VERSION 5.8 ;
BUSBITCHARS "[]" ;
DIVIDERCHAR "/" ;
UNITS
    DATABASE MICRONS 1000 ;
END UNITS

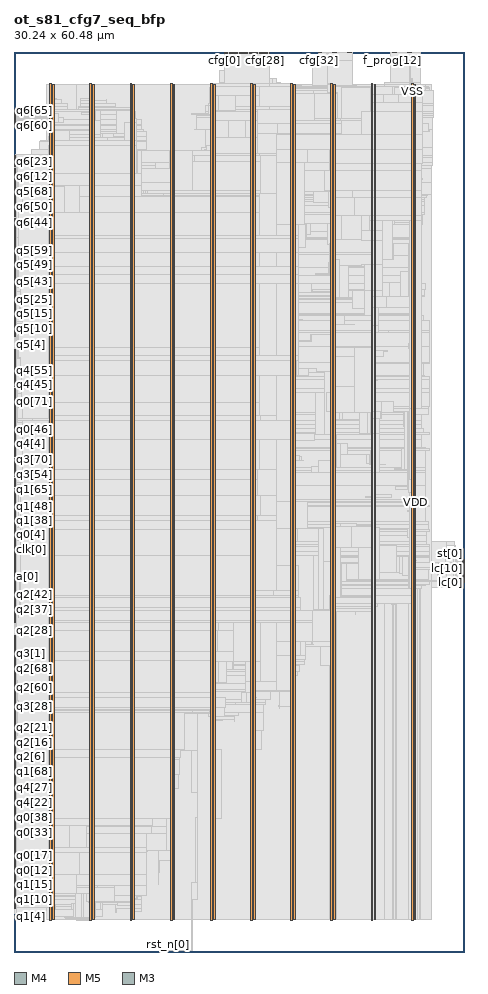
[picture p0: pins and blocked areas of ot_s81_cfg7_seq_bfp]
MACRO ot_s81_cfg7_seq_bfp
  FOREIGN ot_s81_cfg7_seq_bfp 0 0 ;
  CLASS BLOCK ;
  SIZE 30.24 BY 60.48 ;
  PIN a[0]
    DIRECTION OUTPUT ;
    USE SIGNAL ;
    PORT
      LAYER M4 ;
        RECT  0 25.2 0.084 25.224 ;
    END
  END a[0]
  PIN a[10]
    DIRECTION OUTPUT ;
    USE SIGNAL ;
    PORT
      LAYER M4 ;
        RECT  0 26.16 0.084 26.184 ;
    END
  END a[10]
  PIN a[11]
    DIRECTION OUTPUT ;
    USE SIGNAL ;
    PORT
      LAYER M4 ;
        RECT  0 26.256 0.084 26.28 ;
    END
  END a[11]
  PIN a[1]
    DIRECTION OUTPUT ;
    USE SIGNAL ;
    PORT
      LAYER M4 ;
        RECT  0 25.296 0.084 25.32 ;
    END
  END a[1]
  PIN a[2]
    DIRECTION OUTPUT ;
    USE SIGNAL ;
    PORT
      LAYER M4 ;
        RECT  0 25.392 0.084 25.416 ;
    END
  END a[2]
  PIN a[3]
    DIRECTION OUTPUT ;
    USE SIGNAL ;
    PORT
      LAYER M4 ;
        RECT  0 25.488 0.084 25.512 ;
    END
  END a[3]
  PIN a[4]
    DIRECTION OUTPUT ;
    USE SIGNAL ;
    PORT
      LAYER M4 ;
        RECT  0 25.584 0.084 25.608 ;
    END
  END a[4]
  PIN a[5]
    DIRECTION OUTPUT ;
    USE SIGNAL ;
    PORT
      LAYER M4 ;
        RECT  0 25.68 0.084 25.704 ;
    END
  END a[5]
  PIN a[6]
    DIRECTION OUTPUT ;
    USE SIGNAL ;
    PORT
      LAYER M4 ;
        RECT  0 25.776 0.084 25.8 ;
    END
  END a[6]
  PIN a[7]
    DIRECTION OUTPUT ;
    USE SIGNAL ;
    PORT
      LAYER M4 ;
        RECT  0 25.872 0.084 25.896 ;
    END
  END a[7]
  PIN a[8]
    DIRECTION OUTPUT ;
    USE SIGNAL ;
    PORT
      LAYER M4 ;
        RECT  0 25.968 0.084 25.992 ;
    END
  END a[8]
  PIN a[9]
    DIRECTION OUTPUT ;
    USE SIGNAL ;
    PORT
      LAYER M4 ;
        RECT  0 26.064 0.084 26.088 ;
    END
  END a[9]
  PIN ce0[0]
    DIRECTION OUTPUT ;
    USE SIGNAL ;
    PORT
      LAYER M4 ;
        RECT  0 26.352 0.084 26.376 ;
    END
  END ce0[0]
  PIN ce1[0]
    DIRECTION OUTPUT ;
    USE SIGNAL ;
    PORT
      LAYER M4 ;
        RECT  0 26.448 0.084 26.472 ;
    END
  END ce1[0]
  PIN ce2[0]
    DIRECTION OUTPUT ;
    USE SIGNAL ;
    PORT
      LAYER M4 ;
        RECT  0 26.544 0.084 26.568 ;
    END
  END ce2[0]
  PIN ce3[0]
    DIRECTION OUTPUT ;
    USE SIGNAL ;
    PORT
      LAYER M4 ;
        RECT  0 26.64 0.084 26.664 ;
    END
  END ce3[0]
  PIN ce4[0]
    DIRECTION OUTPUT ;
    USE SIGNAL ;
    PORT
      LAYER M4 ;
        RECT  0 26.736 0.084 26.76 ;
    END
  END ce4[0]
  PIN ce5[0]
    DIRECTION OUTPUT ;
    USE SIGNAL ;
    PORT
      LAYER M4 ;
        RECT  0 26.832 0.084 26.856 ;
    END
  END ce5[0]
  PIN ce6[0]
    DIRECTION OUTPUT ;
    USE SIGNAL ;
    PORT
      LAYER M4 ;
        RECT  0 26.928 0.084 26.952 ;
    END
  END ce6[0]
  PIN cfg[0]
    DIRECTION OUTPUT ;
    USE SIGNAL ;
    PORT
      LAYER M5 ;
        RECT  14.16 60.396 14.184 60.48 ;
    END
  END cfg[0]
  PIN cfg[10]
    DIRECTION OUTPUT ;
    USE SIGNAL ;
    PORT
      LAYER M5 ;
        RECT  15.12 60.396 15.144 60.48 ;
    END
  END cfg[10]
  PIN cfg[11]
    DIRECTION OUTPUT ;
    USE SIGNAL ;
    PORT
      LAYER M5 ;
        RECT  15.216 60.396 15.24 60.48 ;
    END
  END cfg[11]
  PIN cfg[12]
    DIRECTION OUTPUT ;
    USE SIGNAL ;
    PORT
      LAYER M5 ;
        RECT  15.312 60.396 15.336 60.48 ;
    END
  END cfg[12]
  PIN cfg[13]
    DIRECTION OUTPUT ;
    USE SIGNAL ;
    PORT
      LAYER M5 ;
        RECT  15.408 60.396 15.432 60.48 ;
    END
  END cfg[13]
  PIN cfg[14]
    DIRECTION OUTPUT ;
    USE SIGNAL ;
    PORT
      LAYER M5 ;
        RECT  15.504 60.396 15.528 60.48 ;
    END
  END cfg[14]
  PIN cfg[15]
    DIRECTION OUTPUT ;
    USE SIGNAL ;
    PORT
      LAYER M5 ;
        RECT  15.6 60.396 15.624 60.48 ;
    END
  END cfg[15]
  PIN cfg[16]
    DIRECTION OUTPUT ;
    USE SIGNAL ;
    PORT
      LAYER M5 ;
        RECT  15.696 60.396 15.72 60.48 ;
    END
  END cfg[16]
  PIN cfg[17]
    DIRECTION OUTPUT ;
    USE SIGNAL ;
    PORT
      LAYER M5 ;
        RECT  15.792 60.396 15.816 60.48 ;
    END
  END cfg[17]
  PIN cfg[18]
    DIRECTION OUTPUT ;
    USE SIGNAL ;
    PORT
      LAYER M5 ;
        RECT  15.888 60.396 15.912 60.48 ;
    END
  END cfg[18]
  PIN cfg[19]
    DIRECTION OUTPUT ;
    USE SIGNAL ;
    PORT
      LAYER M5 ;
        RECT  15.984 60.396 16.008 60.48 ;
    END
  END cfg[19]
  PIN cfg[1]
    DIRECTION OUTPUT ;
    USE SIGNAL ;
    PORT
      LAYER M5 ;
        RECT  14.256 60.396 14.28 60.48 ;
    END
  END cfg[1]
  PIN cfg[20]
    DIRECTION OUTPUT ;
    USE SIGNAL ;
    PORT
      LAYER M5 ;
        RECT  16.08 60.396 16.104 60.48 ;
    END
  END cfg[20]
  PIN cfg[21]
    DIRECTION OUTPUT ;
    USE SIGNAL ;
    PORT
      LAYER M5 ;
        RECT  16.176 60.396 16.2 60.48 ;
    END
  END cfg[21]
  PIN cfg[22]
    DIRECTION OUTPUT ;
    USE SIGNAL ;
    PORT
      LAYER M5 ;
        RECT  16.272 60.396 16.296 60.48 ;
    END
  END cfg[22]
  PIN cfg[23]
    DIRECTION OUTPUT ;
    USE SIGNAL ;
    PORT
      LAYER M5 ;
        RECT  16.368 60.396 16.392 60.48 ;
    END
  END cfg[23]
  PIN cfg[24]
    DIRECTION OUTPUT ;
    USE SIGNAL ;
    PORT
      LAYER M5 ;
        RECT  16.464 60.396 16.488 60.48 ;
    END
  END cfg[24]
  PIN cfg[25]
    DIRECTION OUTPUT ;
    USE SIGNAL ;
    PORT
      LAYER M5 ;
        RECT  16.56 60.396 16.584 60.48 ;
    END
  END cfg[25]
  PIN cfg[26]
    DIRECTION OUTPUT ;
    USE SIGNAL ;
    PORT
      LAYER M5 ;
        RECT  16.656 60.396 16.68 60.48 ;
    END
  END cfg[26]
  PIN cfg[27]
    DIRECTION OUTPUT ;
    USE SIGNAL ;
    PORT
      LAYER M5 ;
        RECT  16.752 60.396 16.776 60.48 ;
    END
  END cfg[27]
  PIN cfg[28]
    DIRECTION OUTPUT ;
    USE SIGNAL ;
    PORT
      LAYER M5 ;
        RECT  16.848 60.396 16.872 60.48 ;
    END
  END cfg[28]
  PIN cfg[29]
    DIRECTION OUTPUT ;
    USE SIGNAL ;
    PORT
      LAYER M5 ;
        RECT  16.944 60.396 16.968 60.48 ;
    END
  END cfg[29]
  PIN cfg[2]
    DIRECTION OUTPUT ;
    USE SIGNAL ;
    PORT
      LAYER M5 ;
        RECT  14.352 60.396 14.376 60.48 ;
    END
  END cfg[2]
  PIN cfg[30]
    DIRECTION OUTPUT ;
    USE SIGNAL ;
    PORT
      LAYER M5 ;
        RECT  17.04 60.396 17.064 60.48 ;
    END
  END cfg[30]
  PIN cfg[31]
    DIRECTION OUTPUT ;
    USE SIGNAL ;
    PORT
      LAYER M5 ;
        RECT  17.136 60.396 17.16 60.48 ;
    END
  END cfg[31]
  PIN cfg[32]
    DIRECTION OUTPUT ;
    USE SIGNAL ;
    PORT
      LAYER M3 ;
        RECT  20.484 60.443 20.502 60.48 ;
    END
  END cfg[32]
  PIN cfg[33]
    DIRECTION OUTPUT ;
    USE SIGNAL ;
    PORT
      LAYER M3 ;
        RECT  20.556 60.443 20.574 60.48 ;
    END
  END cfg[33]
  PIN cfg[34]
    DIRECTION OUTPUT ;
    USE SIGNAL ;
    PORT
      LAYER M3 ;
        RECT  20.628 60.443 20.646 60.48 ;
    END
  END cfg[34]
  PIN cfg[35]
    DIRECTION OUTPUT ;
    USE SIGNAL ;
    PORT
      LAYER M3 ;
        RECT  20.7 60.443 20.718 60.48 ;
    END
  END cfg[35]
  PIN cfg[36]
    DIRECTION OUTPUT ;
    USE SIGNAL ;
    PORT
      LAYER M3 ;
        RECT  20.772 60.443 20.79 60.48 ;
    END
  END cfg[36]
  PIN cfg[37]
    DIRECTION OUTPUT ;
    USE SIGNAL ;
    PORT
      LAYER M3 ;
        RECT  20.844 60.443 20.862 60.48 ;
    END
  END cfg[37]
  PIN cfg[38]
    DIRECTION OUTPUT ;
    USE SIGNAL ;
    PORT
      LAYER M3 ;
        RECT  20.916 60.443 20.934 60.48 ;
    END
  END cfg[38]
  PIN cfg[39]
    DIRECTION OUTPUT ;
    USE SIGNAL ;
    PORT
      LAYER M3 ;
        RECT  20.988 60.443 21.006 60.48 ;
    END
  END cfg[39]
  PIN cfg[3]
    DIRECTION OUTPUT ;
    USE SIGNAL ;
    PORT
      LAYER M5 ;
        RECT  14.448 60.396 14.472 60.48 ;
    END
  END cfg[3]
  PIN cfg[40]
    DIRECTION OUTPUT ;
    USE SIGNAL ;
    PORT
      LAYER M3 ;
        RECT  21.06 60.443 21.078 60.48 ;
    END
  END cfg[40]
  PIN cfg[41]
    DIRECTION OUTPUT ;
    USE SIGNAL ;
    PORT
      LAYER M3 ;
        RECT  21.132 60.443 21.15 60.48 ;
    END
  END cfg[41]
  PIN cfg[42]
    DIRECTION OUTPUT ;
    USE SIGNAL ;
    PORT
      LAYER M3 ;
        RECT  21.204 60.443 21.222 60.48 ;
    END
  END cfg[42]
  PIN cfg[43]
    DIRECTION OUTPUT ;
    USE SIGNAL ;
    PORT
      LAYER M3 ;
        RECT  21.276 60.443 21.294 60.48 ;
    END
  END cfg[43]
  PIN cfg[44]
    DIRECTION OUTPUT ;
    USE SIGNAL ;
    PORT
      LAYER M3 ;
        RECT  21.348 60.443 21.366 60.48 ;
    END
  END cfg[44]
  PIN cfg[45]
    DIRECTION OUTPUT ;
    USE SIGNAL ;
    PORT
      LAYER M3 ;
        RECT  21.42 60.443 21.438 60.48 ;
    END
  END cfg[45]
  PIN cfg[46]
    DIRECTION OUTPUT ;
    USE SIGNAL ;
    PORT
      LAYER M3 ;
        RECT  21.492 60.443 21.51 60.48 ;
    END
  END cfg[46]
  PIN cfg[47]
    DIRECTION OUTPUT ;
    USE SIGNAL ;
    PORT
      LAYER M3 ;
        RECT  21.564 60.443 21.582 60.48 ;
    END
  END cfg[47]
  PIN cfg[48]
    DIRECTION OUTPUT ;
    USE SIGNAL ;
    PORT
      LAYER M3 ;
        RECT  21.636 60.443 21.654 60.48 ;
    END
  END cfg[48]
  PIN cfg[49]
    DIRECTION OUTPUT ;
    USE SIGNAL ;
    PORT
      LAYER M3 ;
        RECT  21.708 60.443 21.726 60.48 ;
    END
  END cfg[49]
  PIN cfg[4]
    DIRECTION OUTPUT ;
    USE SIGNAL ;
    PORT
      LAYER M5 ;
        RECT  14.544 60.396 14.568 60.48 ;
    END
  END cfg[4]
  PIN cfg[50]
    DIRECTION OUTPUT ;
    USE SIGNAL ;
    PORT
      LAYER M3 ;
        RECT  21.78 60.443 21.798 60.48 ;
    END
  END cfg[50]
  PIN cfg[51]
    DIRECTION OUTPUT ;
    USE SIGNAL ;
    PORT
      LAYER M3 ;
        RECT  21.852 60.443 21.87 60.48 ;
    END
  END cfg[51]
  PIN cfg[52]
    DIRECTION OUTPUT ;
    USE SIGNAL ;
    PORT
      LAYER M3 ;
        RECT  21.924 60.443 21.942 60.48 ;
    END
  END cfg[52]
  PIN cfg[53]
    DIRECTION OUTPUT ;
    USE SIGNAL ;
    PORT
      LAYER M3 ;
        RECT  21.996 60.443 22.014 60.48 ;
    END
  END cfg[53]
  PIN cfg[5]
    DIRECTION OUTPUT ;
    USE SIGNAL ;
    PORT
      LAYER M5 ;
        RECT  14.64 60.396 14.664 60.48 ;
    END
  END cfg[5]
  PIN cfg[6]
    DIRECTION OUTPUT ;
    USE SIGNAL ;
    PORT
      LAYER M5 ;
        RECT  14.736 60.396 14.76 60.48 ;
    END
  END cfg[6]
  PIN cfg[7]
    DIRECTION OUTPUT ;
    USE SIGNAL ;
    PORT
      LAYER M5 ;
        RECT  14.832 60.396 14.856 60.48 ;
    END
  END cfg[7]
  PIN cfg[8]
    DIRECTION OUTPUT ;
    USE SIGNAL ;
    PORT
      LAYER M5 ;
        RECT  14.928 60.396 14.952 60.48 ;
    END
  END cfg[8]
  PIN cfg[9]
    DIRECTION OUTPUT ;
    USE SIGNAL ;
    PORT
      LAYER M5 ;
        RECT  15.024 60.396 15.048 60.48 ;
    END
  END cfg[9]
  PIN clk[0]
    DIRECTION INPUT ;
    USE SIGNAL ;
    PORT
      LAYER M4 ;
        RECT  0 27.024 0.084 27.048 ;
    END
  END clk[0]
  PIN f_prog[0]
    DIRECTION OUTPUT ;
    USE SIGNAL ;
    PORT
      LAYER M3 ;
        RECT  22.068 60.443 22.086 60.48 ;
    END
  END f_prog[0]
  PIN f_prog[10]
    DIRECTION OUTPUT ;
    USE SIGNAL ;
    PORT
      LAYER M3 ;
        RECT  25.308 60.443 25.326 60.48 ;
    END
  END f_prog[10]
  PIN f_prog[11]
    DIRECTION OUTPUT ;
    USE SIGNAL ;
    PORT
      LAYER M3 ;
        RECT  25.38 60.443 25.398 60.48 ;
    END
  END f_prog[11]
  PIN f_prog[12]
    DIRECTION OUTPUT ;
    USE SIGNAL ;
    PORT
      LAYER M3 ;
        RECT  25.452 60.443 25.47 60.48 ;
    END
  END f_prog[12]
  PIN f_prog[13]
    DIRECTION OUTPUT ;
    USE SIGNAL ;
    PORT
      LAYER M3 ;
        RECT  25.524 60.443 25.542 60.48 ;
    END
  END f_prog[13]
  PIN f_prog[14]
    DIRECTION OUTPUT ;
    USE SIGNAL ;
    PORT
      LAYER M3 ;
        RECT  25.596 60.443 25.614 60.48 ;
    END
  END f_prog[14]
  PIN f_prog[15]
    DIRECTION OUTPUT ;
    USE SIGNAL ;
    PORT
      LAYER M3 ;
        RECT  25.668 60.443 25.686 60.48 ;
    END
  END f_prog[15]
  PIN f_prog[16]
    DIRECTION OUTPUT ;
    USE SIGNAL ;
    PORT
      LAYER M3 ;
        RECT  25.74 60.443 25.758 60.48 ;
    END
  END f_prog[16]
  PIN f_prog[17]
    DIRECTION OUTPUT ;
    USE SIGNAL ;
    PORT
      LAYER M3 ;
        RECT  25.812 60.443 25.83 60.48 ;
    END
  END f_prog[17]
  PIN f_prog[18]
    DIRECTION OUTPUT ;
    USE SIGNAL ;
    PORT
      LAYER M3 ;
        RECT  25.884 60.443 25.902 60.48 ;
    END
  END f_prog[18]
  PIN f_prog[19]
    DIRECTION OUTPUT ;
    USE SIGNAL ;
    PORT
      LAYER M3 ;
        RECT  25.956 60.443 25.974 60.48 ;
    END
  END f_prog[19]
  PIN f_prog[1]
    DIRECTION OUTPUT ;
    USE SIGNAL ;
    PORT
      LAYER M3 ;
        RECT  22.14 60.443 22.158 60.48 ;
    END
  END f_prog[1]
  PIN f_prog[20]
    DIRECTION OUTPUT ;
    USE SIGNAL ;
    PORT
      LAYER M3 ;
        RECT  26.028 60.443 26.046 60.48 ;
    END
  END f_prog[20]
  PIN f_prog[21]
    DIRECTION OUTPUT ;
    USE SIGNAL ;
    PORT
      LAYER M3 ;
        RECT  26.1 60.443 26.118 60.48 ;
    END
  END f_prog[21]
  PIN f_prog[22]
    DIRECTION OUTPUT ;
    USE SIGNAL ;
    PORT
      LAYER M3 ;
        RECT  26.172 60.443 26.19 60.48 ;
    END
  END f_prog[22]
  PIN f_prog[23]
    DIRECTION OUTPUT ;
    USE SIGNAL ;
    PORT
      LAYER M3 ;
        RECT  26.244 60.443 26.262 60.48 ;
    END
  END f_prog[23]
  PIN f_prog[24]
    DIRECTION OUTPUT ;
    USE SIGNAL ;
    PORT
      LAYER M3 ;
        RECT  26.316 60.443 26.334 60.48 ;
    END
  END f_prog[24]
  PIN f_prog[25]
    DIRECTION OUTPUT ;
    USE SIGNAL ;
    PORT
      LAYER M3 ;
        RECT  26.388 60.443 26.406 60.48 ;
    END
  END f_prog[25]
  PIN f_prog[26]
    DIRECTION OUTPUT ;
    USE SIGNAL ;
    PORT
      LAYER M3 ;
        RECT  26.46 60.443 26.478 60.48 ;
    END
  END f_prog[26]
  PIN f_prog[27]
    DIRECTION OUTPUT ;
    USE SIGNAL ;
    PORT
      LAYER M3 ;
        RECT  26.532 60.443 26.55 60.48 ;
    END
  END f_prog[27]
  PIN f_prog[28]
    DIRECTION OUTPUT ;
    USE SIGNAL ;
    PORT
      LAYER M3 ;
        RECT  26.604 60.443 26.622 60.48 ;
    END
  END f_prog[28]
  PIN f_prog[29]
    DIRECTION OUTPUT ;
    USE SIGNAL ;
    PORT
      LAYER M3 ;
        RECT  26.676 60.443 26.694 60.48 ;
    END
  END f_prog[29]
  PIN f_prog[2]
    DIRECTION OUTPUT ;
    USE SIGNAL ;
    PORT
      LAYER M3 ;
        RECT  22.212 60.443 22.23 60.48 ;
    END
  END f_prog[2]
  PIN f_prog[30]
    DIRECTION OUTPUT ;
    USE SIGNAL ;
    PORT
      LAYER M3 ;
        RECT  26.748 60.443 26.766 60.48 ;
    END
  END f_prog[30]
  PIN f_prog[31]
    DIRECTION OUTPUT ;
    USE SIGNAL ;
    PORT
      LAYER M3 ;
        RECT  26.82 60.443 26.838 60.48 ;
    END
  END f_prog[31]
  PIN f_prog[32]
    DIRECTION OUTPUT ;
    USE SIGNAL ;
    PORT
      LAYER M3 ;
        RECT  26.892 60.443 26.91 60.48 ;
    END
  END f_prog[32]
  PIN f_prog[33]
    DIRECTION OUTPUT ;
    USE SIGNAL ;
    PORT
      LAYER M3 ;
        RECT  26.964 60.443 26.982 60.48 ;
    END
  END f_prog[33]
  PIN f_prog[34]
    DIRECTION OUTPUT ;
    USE SIGNAL ;
    PORT
      LAYER M3 ;
        RECT  27.036 60.443 27.054 60.48 ;
    END
  END f_prog[34]
  PIN f_prog[35]
    DIRECTION OUTPUT ;
    USE SIGNAL ;
    PORT
      LAYER M3 ;
        RECT  27.108 60.443 27.126 60.48 ;
    END
  END f_prog[35]
  PIN f_prog[36]
    DIRECTION OUTPUT ;
    USE SIGNAL ;
    PORT
      LAYER M3 ;
        RECT  27.18 60.443 27.198 60.48 ;
    END
  END f_prog[36]
  PIN f_prog[37]
    DIRECTION OUTPUT ;
    USE SIGNAL ;
    PORT
      LAYER M3 ;
        RECT  27.252 60.443 27.27 60.48 ;
    END
  END f_prog[37]
  PIN f_prog[3]
    DIRECTION OUTPUT ;
    USE SIGNAL ;
    PORT
      LAYER M3 ;
        RECT  22.284 60.443 22.302 60.48 ;
    END
  END f_prog[3]
  PIN f_prog[4]
    DIRECTION OUTPUT ;
    USE SIGNAL ;
    PORT
      LAYER M3 ;
        RECT  22.356 60.443 22.374 60.48 ;
    END
  END f_prog[4]
  PIN f_prog[5]
    DIRECTION OUTPUT ;
    USE SIGNAL ;
    PORT
      LAYER M3 ;
        RECT  22.428 60.443 22.446 60.48 ;
    END
  END f_prog[5]
  PIN f_prog[6]
    DIRECTION OUTPUT ;
    USE SIGNAL ;
    PORT
      LAYER M3 ;
        RECT  22.5 60.443 22.518 60.48 ;
    END
  END f_prog[6]
  PIN f_prog[7]
    DIRECTION OUTPUT ;
    USE SIGNAL ;
    PORT
      LAYER M3 ;
        RECT  22.572 60.443 22.59 60.48 ;
    END
  END f_prog[7]
  PIN f_prog[8]
    DIRECTION OUTPUT ;
    USE SIGNAL ;
    PORT
      LAYER M3 ;
        RECT  22.644 60.443 22.662 60.48 ;
    END
  END f_prog[8]
  PIN f_prog[9]
    DIRECTION OUTPUT ;
    USE SIGNAL ;
    PORT
      LAYER M3 ;
        RECT  22.716 60.443 22.734 60.48 ;
    END
  END f_prog[9]
  PIN go_e[0]
    DIRECTION OUTPUT ;
    USE SIGNAL ;
    PORT
      LAYER M3 ;
        RECT  27.324 60.443 27.342 60.48 ;
    END
  END go_e[0]
  PIN lc[0]
    DIRECTION INPUT ;
    USE SIGNAL ;
    PORT
      LAYER M4 ;
        RECT  30.156 24.816 30.24 24.84 ;
    END
  END lc[0]
  PIN lc[10]
    DIRECTION INPUT ;
    USE SIGNAL ;
    PORT
      LAYER M4 ;
        RECT  30.156 25.776 30.24 25.8 ;
    END
  END lc[10]
  PIN lc[11]
    DIRECTION INPUT ;
    USE SIGNAL ;
    PORT
      LAYER M4 ;
        RECT  30.156 25.872 30.24 25.896 ;
    END
  END lc[11]
  PIN lc[12]
    DIRECTION INPUT ;
    USE SIGNAL ;
    PORT
      LAYER M4 ;
        RECT  30.156 25.968 30.24 25.992 ;
    END
  END lc[12]
  PIN lc[13]
    DIRECTION INPUT ;
    USE SIGNAL ;
    PORT
      LAYER M4 ;
        RECT  30.156 26.064 30.24 26.088 ;
    END
  END lc[13]
  PIN lc[14]
    DIRECTION INPUT ;
    USE SIGNAL ;
    PORT
      LAYER M4 ;
        RECT  30.156 26.16 30.24 26.184 ;
    END
  END lc[14]
  PIN lc[1]
    DIRECTION INPUT ;
    USE SIGNAL ;
    PORT
      LAYER M4 ;
        RECT  30.156 24.912 30.24 24.936 ;
    END
  END lc[1]
  PIN lc[2]
    DIRECTION INPUT ;
    USE SIGNAL ;
    PORT
      LAYER M4 ;
        RECT  30.156 25.008 30.24 25.032 ;
    END
  END lc[2]
  PIN lc[3]
    DIRECTION INPUT ;
    USE SIGNAL ;
    PORT
      LAYER M4 ;
        RECT  30.156 25.104 30.24 25.128 ;
    END
  END lc[3]
  PIN lc[4]
    DIRECTION INPUT ;
    USE SIGNAL ;
    PORT
      LAYER M4 ;
        RECT  30.156 25.2 30.24 25.224 ;
    END
  END lc[4]
  PIN lc[5]
    DIRECTION INPUT ;
    USE SIGNAL ;
    PORT
      LAYER M4 ;
        RECT  30.156 25.296 30.24 25.32 ;
    END
  END lc[5]
  PIN lc[6]
    DIRECTION INPUT ;
    USE SIGNAL ;
    PORT
      LAYER M4 ;
        RECT  30.156 25.392 30.24 25.416 ;
    END
  END lc[6]
  PIN lc[7]
    DIRECTION INPUT ;
    USE SIGNAL ;
    PORT
      LAYER M4 ;
        RECT  30.156 25.488 30.24 25.512 ;
    END
  END lc[7]
  PIN lc[8]
    DIRECTION INPUT ;
    USE SIGNAL ;
    PORT
      LAYER M4 ;
        RECT  30.156 25.584 30.24 25.608 ;
    END
  END lc[8]
  PIN lc[9]
    DIRECTION INPUT ;
    USE SIGNAL ;
    PORT
      LAYER M4 ;
        RECT  30.156 25.68 30.24 25.704 ;
    END
  END lc[9]
  PIN q0[0]
    DIRECTION INPUT ;
    USE SIGNAL ;
    PORT
      LAYER M4 ;
        RECT  0 27.12 0.084 27.144 ;
    END
  END q0[0]
  PIN q0[10]
    DIRECTION INPUT ;
    USE SIGNAL ;
    PORT
      LAYER M4 ;
        RECT  0 28.08 0.084 28.104 ;
    END
  END q0[10]
  PIN q0[11]
    DIRECTION INPUT ;
    USE SIGNAL ;
    PORT
      LAYER M4 ;
        RECT  0 28.176 0.084 28.2 ;
    END
  END q0[11]
  PIN q0[12]
    DIRECTION INPUT ;
    USE SIGNAL ;
    PORT
      LAYER M4 ;
        RECT  0 6 0.084 6.024 ;
    END
  END q0[12]
  PIN q0[13]
    DIRECTION INPUT ;
    USE SIGNAL ;
    PORT
      LAYER M4 ;
        RECT  0 6.096 0.084 6.12 ;
    END
  END q0[13]
  PIN q0[14]
    DIRECTION INPUT ;
    USE SIGNAL ;
    PORT
      LAYER M4 ;
        RECT  0 6.192 0.084 6.216 ;
    END
  END q0[14]
  PIN q0[15]
    DIRECTION INPUT ;
    USE SIGNAL ;
    PORT
      LAYER M4 ;
        RECT  0 6.288 0.084 6.312 ;
    END
  END q0[15]
  PIN q0[16]
    DIRECTION INPUT ;
    USE SIGNAL ;
    PORT
      LAYER M4 ;
        RECT  0 6.384 0.084 6.408 ;
    END
  END q0[16]
  PIN q0[17]
    DIRECTION INPUT ;
    USE SIGNAL ;
    PORT
      LAYER M4 ;
        RECT  0 6.48 0.084 6.504 ;
    END
  END q0[17]
  PIN q0[18]
    DIRECTION INPUT ;
    USE SIGNAL ;
    PORT
      LAYER M4 ;
        RECT  0 6.576 0.084 6.6 ;
    END
  END q0[18]
  PIN q0[19]
    DIRECTION INPUT ;
    USE SIGNAL ;
    PORT
      LAYER M4 ;
        RECT  0 6.672 0.084 6.696 ;
    END
  END q0[19]
  PIN q0[1]
    DIRECTION INPUT ;
    USE SIGNAL ;
    PORT
      LAYER M4 ;
        RECT  0 27.216 0.084 27.24 ;
    END
  END q0[1]
  PIN q0[20]
    DIRECTION INPUT ;
    USE SIGNAL ;
    PORT
      LAYER M4 ;
        RECT  0 6.768 0.084 6.792 ;
    END
  END q0[20]
  PIN q0[21]
    DIRECTION INPUT ;
    USE SIGNAL ;
    PORT
      LAYER M4 ;
        RECT  0 6.864 0.084 6.888 ;
    END
  END q0[21]
  PIN q0[22]
    DIRECTION INPUT ;
    USE SIGNAL ;
    PORT
      LAYER M4 ;
        RECT  0 6.96 0.084 6.984 ;
    END
  END q0[22]
  PIN q0[23]
    DIRECTION INPUT ;
    USE SIGNAL ;
    PORT
      LAYER M4 ;
        RECT  0 7.056 0.084 7.08 ;
    END
  END q0[23]
  PIN q0[24]
    DIRECTION INPUT ;
    USE SIGNAL ;
    PORT
      LAYER M4 ;
        RECT  0 7.152 0.084 7.176 ;
    END
  END q0[24]
  PIN q0[25]
    DIRECTION INPUT ;
    USE SIGNAL ;
    PORT
      LAYER M4 ;
        RECT  0 7.248 0.084 7.272 ;
    END
  END q0[25]
  PIN q0[26]
    DIRECTION INPUT ;
    USE SIGNAL ;
    PORT
      LAYER M4 ;
        RECT  0 7.344 0.084 7.368 ;
    END
  END q0[26]
  PIN q0[27]
    DIRECTION INPUT ;
    USE SIGNAL ;
    PORT
      LAYER M4 ;
        RECT  0 7.44 0.084 7.464 ;
    END
  END q0[27]
  PIN q0[28]
    DIRECTION INPUT ;
    USE SIGNAL ;
    PORT
      LAYER M4 ;
        RECT  0 7.536 0.084 7.56 ;
    END
  END q0[28]
  PIN q0[29]
    DIRECTION INPUT ;
    USE SIGNAL ;
    PORT
      LAYER M4 ;
        RECT  0 7.632 0.084 7.656 ;
    END
  END q0[29]
  PIN q0[2]
    DIRECTION INPUT ;
    USE SIGNAL ;
    PORT
      LAYER M4 ;
        RECT  0 27.312 0.084 27.336 ;
    END
  END q0[2]
  PIN q0[30]
    DIRECTION INPUT ;
    USE SIGNAL ;
    PORT
      LAYER M4 ;
        RECT  0 7.728 0.084 7.752 ;
    END
  END q0[30]
  PIN q0[31]
    DIRECTION INPUT ;
    USE SIGNAL ;
    PORT
      LAYER M4 ;
        RECT  0 7.824 0.084 7.848 ;
    END
  END q0[31]
  PIN q0[32]
    DIRECTION INPUT ;
    USE SIGNAL ;
    PORT
      LAYER M4 ;
        RECT  0 7.92 0.084 7.944 ;
    END
  END q0[32]
  PIN q0[33]
    DIRECTION INPUT ;
    USE SIGNAL ;
    PORT
      LAYER M4 ;
        RECT  0 8.016 0.084 8.04 ;
    END
  END q0[33]
  PIN q0[34]
    DIRECTION INPUT ;
    USE SIGNAL ;
    PORT
      LAYER M4 ;
        RECT  0 8.112 0.084 8.136 ;
    END
  END q0[34]
  PIN q0[35]
    DIRECTION INPUT ;
    USE SIGNAL ;
    PORT
      LAYER M4 ;
        RECT  0 8.208 0.084 8.232 ;
    END
  END q0[35]
  PIN q0[36]
    DIRECTION INPUT ;
    USE SIGNAL ;
    PORT
      LAYER M4 ;
        RECT  0 8.304 0.084 8.328 ;
    END
  END q0[36]
  PIN q0[37]
    DIRECTION INPUT ;
    USE SIGNAL ;
    PORT
      LAYER M4 ;
        RECT  0 8.4 0.084 8.424 ;
    END
  END q0[37]
  PIN q0[38]
    DIRECTION INPUT ;
    USE SIGNAL ;
    PORT
      LAYER M4 ;
        RECT  0 8.496 0.084 8.52 ;
    END
  END q0[38]
  PIN q0[39]
    DIRECTION INPUT ;
    USE SIGNAL ;
    PORT
      LAYER M4 ;
        RECT  0 8.592 0.084 8.616 ;
    END
  END q0[39]
  PIN q0[3]
    DIRECTION INPUT ;
    USE SIGNAL ;
    PORT
      LAYER M4 ;
        RECT  0 27.408 0.084 27.432 ;
    END
  END q0[3]
  PIN q0[40]
    DIRECTION INPUT ;
    USE SIGNAL ;
    PORT
      LAYER M4 ;
        RECT  0 8.688 0.084 8.712 ;
    END
  END q0[40]
  PIN q0[41]
    DIRECTION INPUT ;
    USE SIGNAL ;
    PORT
      LAYER M4 ;
        RECT  0 8.784 0.084 8.808 ;
    END
  END q0[41]
  PIN q0[42]
    DIRECTION INPUT ;
    USE SIGNAL ;
    PORT
      LAYER M4 ;
        RECT  0 8.88 0.084 8.904 ;
    END
  END q0[42]
  PIN q0[43]
    DIRECTION INPUT ;
    USE SIGNAL ;
    PORT
      LAYER M4 ;
        RECT  0 8.976 0.084 9 ;
    END
  END q0[43]
  PIN q0[44]
    DIRECTION INPUT ;
    USE SIGNAL ;
    PORT
      LAYER M4 ;
        RECT  0 34.416 0.084 34.44 ;
    END
  END q0[44]
  PIN q0[45]
    DIRECTION INPUT ;
    USE SIGNAL ;
    PORT
      LAYER M4 ;
        RECT  0 34.512 0.084 34.536 ;
    END
  END q0[45]
  PIN q0[46]
    DIRECTION INPUT ;
    USE SIGNAL ;
    PORT
      LAYER M4 ;
        RECT  0 34.608 0.084 34.632 ;
    END
  END q0[46]
  PIN q0[47]
    DIRECTION INPUT ;
    USE SIGNAL ;
    PORT
      LAYER M4 ;
        RECT  0 34.704 0.084 34.728 ;
    END
  END q0[47]
  PIN q0[48]
    DIRECTION INPUT ;
    USE SIGNAL ;
    PORT
      LAYER M4 ;
        RECT  0 34.8 0.084 34.824 ;
    END
  END q0[48]
  PIN q0[49]
    DIRECTION INPUT ;
    USE SIGNAL ;
    PORT
      LAYER M4 ;
        RECT  0 34.896 0.084 34.92 ;
    END
  END q0[49]
  PIN q0[4]
    DIRECTION INPUT ;
    USE SIGNAL ;
    PORT
      LAYER M4 ;
        RECT  0 27.504 0.084 27.528 ;
    END
  END q0[4]
  PIN q0[50]
    DIRECTION INPUT ;
    USE SIGNAL ;
    PORT
      LAYER M4 ;
        RECT  0 34.992 0.084 35.016 ;
    END
  END q0[50]
  PIN q0[51]
    DIRECTION INPUT ;
    USE SIGNAL ;
    PORT
      LAYER M4 ;
        RECT  0 35.088 0.084 35.112 ;
    END
  END q0[51]
  PIN q0[52]
    DIRECTION INPUT ;
    USE SIGNAL ;
    PORT
      LAYER M4 ;
        RECT  0 35.184 0.084 35.208 ;
    END
  END q0[52]
  PIN q0[53]
    DIRECTION INPUT ;
    USE SIGNAL ;
    PORT
      LAYER M4 ;
        RECT  0 35.28 0.084 35.304 ;
    END
  END q0[53]
  PIN q0[54]
    DIRECTION INPUT ;
    USE SIGNAL ;
    PORT
      LAYER M4 ;
        RECT  0 35.376 0.084 35.4 ;
    END
  END q0[54]
  PIN q0[55]
    DIRECTION INPUT ;
    USE SIGNAL ;
    PORT
      LAYER M4 ;
        RECT  0 35.472 0.084 35.496 ;
    END
  END q0[55]
  PIN q0[56]
    DIRECTION INPUT ;
    USE SIGNAL ;
    PORT
      LAYER M4 ;
        RECT  0 35.568 0.084 35.592 ;
    END
  END q0[56]
  PIN q0[57]
    DIRECTION INPUT ;
    USE SIGNAL ;
    PORT
      LAYER M4 ;
        RECT  0 35.664 0.084 35.688 ;
    END
  END q0[57]
  PIN q0[58]
    DIRECTION INPUT ;
    USE SIGNAL ;
    PORT
      LAYER M4 ;
        RECT  0 35.76 0.084 35.784 ;
    END
  END q0[58]
  PIN q0[59]
    DIRECTION INPUT ;
    USE SIGNAL ;
    PORT
      LAYER M4 ;
        RECT  0 35.856 0.084 35.88 ;
    END
  END q0[59]
  PIN q0[5]
    DIRECTION INPUT ;
    USE SIGNAL ;
    PORT
      LAYER M4 ;
        RECT  0 27.6 0.084 27.624 ;
    END
  END q0[5]
  PIN q0[60]
    DIRECTION INPUT ;
    USE SIGNAL ;
    PORT
      LAYER M4 ;
        RECT  0 35.952 0.084 35.976 ;
    END
  END q0[60]
  PIN q0[61]
    DIRECTION INPUT ;
    USE SIGNAL ;
    PORT
      LAYER M4 ;
        RECT  0 36.048 0.084 36.072 ;
    END
  END q0[61]
  PIN q0[62]
    DIRECTION INPUT ;
    USE SIGNAL ;
    PORT
      LAYER M4 ;
        RECT  0 36.144 0.084 36.168 ;
    END
  END q0[62]
  PIN q0[63]
    DIRECTION INPUT ;
    USE SIGNAL ;
    PORT
      LAYER M4 ;
        RECT  0 36.24 0.084 36.264 ;
    END
  END q0[63]
  PIN q0[64]
    DIRECTION INPUT ;
    USE SIGNAL ;
    PORT
      LAYER M4 ;
        RECT  0 36.336 0.084 36.36 ;
    END
  END q0[64]
  PIN q0[65]
    DIRECTION INPUT ;
    USE SIGNAL ;
    PORT
      LAYER M4 ;
        RECT  0 36.432 0.084 36.456 ;
    END
  END q0[65]
  PIN q0[66]
    DIRECTION INPUT ;
    USE SIGNAL ;
    PORT
      LAYER M4 ;
        RECT  0 36.528 0.084 36.552 ;
    END
  END q0[66]
  PIN q0[67]
    DIRECTION INPUT ;
    USE SIGNAL ;
    PORT
      LAYER M4 ;
        RECT  0 36.624 0.084 36.648 ;
    END
  END q0[67]
  PIN q0[68]
    DIRECTION INPUT ;
    USE SIGNAL ;
    PORT
      LAYER M4 ;
        RECT  0 36.72 0.084 36.744 ;
    END
  END q0[68]
  PIN q0[69]
    DIRECTION INPUT ;
    USE SIGNAL ;
    PORT
      LAYER M4 ;
        RECT  0 36.816 0.084 36.84 ;
    END
  END q0[69]
  PIN q0[6]
    DIRECTION INPUT ;
    USE SIGNAL ;
    PORT
      LAYER M4 ;
        RECT  0 27.696 0.084 27.72 ;
    END
  END q0[6]
  PIN q0[70]
    DIRECTION INPUT ;
    USE SIGNAL ;
    PORT
      LAYER M4 ;
        RECT  0 36.912 0.084 36.936 ;
    END
  END q0[70]
  PIN q0[71]
    DIRECTION INPUT ;
    USE SIGNAL ;
    PORT
      LAYER M4 ;
        RECT  0 37.008 0.084 37.032 ;
    END
  END q0[71]
  PIN q0[7]
    DIRECTION INPUT ;
    USE SIGNAL ;
    PORT
      LAYER M4 ;
        RECT  0 27.792 0.084 27.816 ;
    END
  END q0[7]
  PIN q0[8]
    DIRECTION INPUT ;
    USE SIGNAL ;
    PORT
      LAYER M4 ;
        RECT  0 27.888 0.084 27.912 ;
    END
  END q0[8]
  PIN q0[9]
    DIRECTION INPUT ;
    USE SIGNAL ;
    PORT
      LAYER M4 ;
        RECT  0 27.984 0.084 28.008 ;
    END
  END q0[9]
  PIN q1[0]
    DIRECTION INPUT ;
    USE SIGNAL ;
    PORT
      LAYER M4 ;
        RECT  0 37.104 0.084 37.128 ;
    END
  END q1[0]
  PIN q1[10]
    DIRECTION INPUT ;
    USE SIGNAL ;
    PORT
      LAYER M4 ;
        RECT  0 3.504 0.084 3.528 ;
    END
  END q1[10]
  PIN q1[11]
    DIRECTION INPUT ;
    USE SIGNAL ;
    PORT
      LAYER M4 ;
        RECT  0 3.6 0.084 3.624 ;
    END
  END q1[11]
  PIN q1[12]
    DIRECTION INPUT ;
    USE SIGNAL ;
    PORT
      LAYER M4 ;
        RECT  0 3.696 0.084 3.72 ;
    END
  END q1[12]
  PIN q1[13]
    DIRECTION INPUT ;
    USE SIGNAL ;
    PORT
      LAYER M4 ;
        RECT  0 3.792 0.084 3.816 ;
    END
  END q1[13]
  PIN q1[14]
    DIRECTION INPUT ;
    USE SIGNAL ;
    PORT
      LAYER M4 ;
        RECT  0 3.888 0.084 3.912 ;
    END
  END q1[14]
  PIN q1[15]
    DIRECTION INPUT ;
    USE SIGNAL ;
    PORT
      LAYER M4 ;
        RECT  0 3.984 0.084 4.008 ;
    END
  END q1[15]
  PIN q1[16]
    DIRECTION INPUT ;
    USE SIGNAL ;
    PORT
      LAYER M4 ;
        RECT  0 4.08 0.084 4.104 ;
    END
  END q1[16]
  PIN q1[17]
    DIRECTION INPUT ;
    USE SIGNAL ;
    PORT
      LAYER M4 ;
        RECT  0 4.176 0.084 4.2 ;
    END
  END q1[17]
  PIN q1[18]
    DIRECTION INPUT ;
    USE SIGNAL ;
    PORT
      LAYER M4 ;
        RECT  0 4.272 0.084 4.296 ;
    END
  END q1[18]
  PIN q1[19]
    DIRECTION INPUT ;
    USE SIGNAL ;
    PORT
      LAYER M4 ;
        RECT  0 4.368 0.084 4.392 ;
    END
  END q1[19]
  PIN q1[1]
    DIRECTION INPUT ;
    USE SIGNAL ;
    PORT
      LAYER M4 ;
        RECT  0 37.2 0.084 37.224 ;
    END
  END q1[1]
  PIN q1[20]
    DIRECTION INPUT ;
    USE SIGNAL ;
    PORT
      LAYER M4 ;
        RECT  0 4.464 0.084 4.488 ;
    END
  END q1[20]
  PIN q1[21]
    DIRECTION INPUT ;
    USE SIGNAL ;
    PORT
      LAYER M4 ;
        RECT  0 4.56 0.084 4.584 ;
    END
  END q1[21]
  PIN q1[22]
    DIRECTION INPUT ;
    USE SIGNAL ;
    PORT
      LAYER M4 ;
        RECT  0 4.656 0.084 4.68 ;
    END
  END q1[22]
  PIN q1[23]
    DIRECTION INPUT ;
    USE SIGNAL ;
    PORT
      LAYER M4 ;
        RECT  0 4.752 0.084 4.776 ;
    END
  END q1[23]
  PIN q1[24]
    DIRECTION INPUT ;
    USE SIGNAL ;
    PORT
      LAYER M4 ;
        RECT  0 4.848 0.084 4.872 ;
    END
  END q1[24]
  PIN q1[25]
    DIRECTION INPUT ;
    USE SIGNAL ;
    PORT
      LAYER M4 ;
        RECT  0 4.944 0.084 4.968 ;
    END
  END q1[25]
  PIN q1[26]
    DIRECTION INPUT ;
    USE SIGNAL ;
    PORT
      LAYER M4 ;
        RECT  0 5.04 0.084 5.064 ;
    END
  END q1[26]
  PIN q1[27]
    DIRECTION INPUT ;
    USE SIGNAL ;
    PORT
      LAYER M4 ;
        RECT  0 5.136 0.084 5.16 ;
    END
  END q1[27]
  PIN q1[28]
    DIRECTION INPUT ;
    USE SIGNAL ;
    PORT
      LAYER M4 ;
        RECT  0 5.232 0.084 5.256 ;
    END
  END q1[28]
  PIN q1[29]
    DIRECTION INPUT ;
    USE SIGNAL ;
    PORT
      LAYER M4 ;
        RECT  0 5.328 0.084 5.352 ;
    END
  END q1[29]
  PIN q1[2]
    DIRECTION INPUT ;
    USE SIGNAL ;
    PORT
      LAYER M4 ;
        RECT  0 37.296 0.084 37.32 ;
    END
  END q1[2]
  PIN q1[30]
    DIRECTION INPUT ;
    USE SIGNAL ;
    PORT
      LAYER M4 ;
        RECT  0 5.424 0.084 5.448 ;
    END
  END q1[30]
  PIN q1[31]
    DIRECTION INPUT ;
    USE SIGNAL ;
    PORT
      LAYER M4 ;
        RECT  0 5.52 0.084 5.544 ;
    END
  END q1[31]
  PIN q1[32]
    DIRECTION INPUT ;
    USE SIGNAL ;
    PORT
      LAYER M4 ;
        RECT  0 5.616 0.084 5.64 ;
    END
  END q1[32]
  PIN q1[33]
    DIRECTION INPUT ;
    USE SIGNAL ;
    PORT
      LAYER M4 ;
        RECT  0 5.712 0.084 5.736 ;
    END
  END q1[33]
  PIN q1[34]
    DIRECTION INPUT ;
    USE SIGNAL ;
    PORT
      LAYER M4 ;
        RECT  0 5.808 0.084 5.832 ;
    END
  END q1[34]
  PIN q1[35]
    DIRECTION INPUT ;
    USE SIGNAL ;
    PORT
      LAYER M4 ;
        RECT  0 5.904 0.084 5.928 ;
    END
  END q1[35]
  PIN q1[36]
    DIRECTION INPUT ;
    USE SIGNAL ;
    PORT
      LAYER M4 ;
        RECT  0 28.272 0.084 28.296 ;
    END
  END q1[36]
  PIN q1[37]
    DIRECTION INPUT ;
    USE SIGNAL ;
    PORT
      LAYER M4 ;
        RECT  0 28.368 0.084 28.392 ;
    END
  END q1[37]
  PIN q1[38]
    DIRECTION INPUT ;
    USE SIGNAL ;
    PORT
      LAYER M4 ;
        RECT  0 28.464 0.084 28.488 ;
    END
  END q1[38]
  PIN q1[39]
    DIRECTION INPUT ;
    USE SIGNAL ;
    PORT
      LAYER M4 ;
        RECT  0 28.56 0.084 28.584 ;
    END
  END q1[39]
  PIN q1[3]
    DIRECTION INPUT ;
    USE SIGNAL ;
    PORT
      LAYER M4 ;
        RECT  0 37.392 0.084 37.416 ;
    END
  END q1[3]
  PIN q1[40]
    DIRECTION INPUT ;
    USE SIGNAL ;
    PORT
      LAYER M4 ;
        RECT  0 28.656 0.084 28.68 ;
    END
  END q1[40]
  PIN q1[41]
    DIRECTION INPUT ;
    USE SIGNAL ;
    PORT
      LAYER M4 ;
        RECT  0 28.752 0.084 28.776 ;
    END
  END q1[41]
  PIN q1[42]
    DIRECTION INPUT ;
    USE SIGNAL ;
    PORT
      LAYER M4 ;
        RECT  0 28.848 0.084 28.872 ;
    END
  END q1[42]
  PIN q1[43]
    DIRECTION INPUT ;
    USE SIGNAL ;
    PORT
      LAYER M4 ;
        RECT  0 28.944 0.084 28.968 ;
    END
  END q1[43]
  PIN q1[44]
    DIRECTION INPUT ;
    USE SIGNAL ;
    PORT
      LAYER M4 ;
        RECT  0 29.04 0.084 29.064 ;
    END
  END q1[44]
  PIN q1[45]
    DIRECTION INPUT ;
    USE SIGNAL ;
    PORT
      LAYER M4 ;
        RECT  0 29.136 0.084 29.16 ;
    END
  END q1[45]
  PIN q1[46]
    DIRECTION INPUT ;
    USE SIGNAL ;
    PORT
      LAYER M4 ;
        RECT  0 29.232 0.084 29.256 ;
    END
  END q1[46]
  PIN q1[47]
    DIRECTION INPUT ;
    USE SIGNAL ;
    PORT
      LAYER M4 ;
        RECT  0 29.328 0.084 29.352 ;
    END
  END q1[47]
  PIN q1[48]
    DIRECTION INPUT ;
    USE SIGNAL ;
    PORT
      LAYER M4 ;
        RECT  0 29.424 0.084 29.448 ;
    END
  END q1[48]
  PIN q1[49]
    DIRECTION INPUT ;
    USE SIGNAL ;
    PORT
      LAYER M4 ;
        RECT  0 29.52 0.084 29.544 ;
    END
  END q1[49]
  PIN q1[4]
    DIRECTION INPUT ;
    USE SIGNAL ;
    PORT
      LAYER M4 ;
        RECT  0 2.928 0.084 2.952 ;
    END
  END q1[4]
  PIN q1[50]
    DIRECTION INPUT ;
    USE SIGNAL ;
    PORT
      LAYER M4 ;
        RECT  0 29.616 0.084 29.64 ;
    END
  END q1[50]
  PIN q1[51]
    DIRECTION INPUT ;
    USE SIGNAL ;
    PORT
      LAYER M4 ;
        RECT  0 29.712 0.084 29.736 ;
    END
  END q1[51]
  PIN q1[52]
    DIRECTION INPUT ;
    USE SIGNAL ;
    PORT
      LAYER M4 ;
        RECT  0 29.808 0.084 29.832 ;
    END
  END q1[52]
  PIN q1[53]
    DIRECTION INPUT ;
    USE SIGNAL ;
    PORT
      LAYER M4 ;
        RECT  0 29.904 0.084 29.928 ;
    END
  END q1[53]
  PIN q1[54]
    DIRECTION INPUT ;
    USE SIGNAL ;
    PORT
      LAYER M4 ;
        RECT  0 30 0.084 30.024 ;
    END
  END q1[54]
  PIN q1[55]
    DIRECTION INPUT ;
    USE SIGNAL ;
    PORT
      LAYER M4 ;
        RECT  0 30.096 0.084 30.12 ;
    END
  END q1[55]
  PIN q1[56]
    DIRECTION INPUT ;
    USE SIGNAL ;
    PORT
      LAYER M4 ;
        RECT  0 30.192 0.084 30.216 ;
    END
  END q1[56]
  PIN q1[57]
    DIRECTION INPUT ;
    USE SIGNAL ;
    PORT
      LAYER M4 ;
        RECT  0 30.288 0.084 30.312 ;
    END
  END q1[57]
  PIN q1[58]
    DIRECTION INPUT ;
    USE SIGNAL ;
    PORT
      LAYER M4 ;
        RECT  0 30.384 0.084 30.408 ;
    END
  END q1[58]
  PIN q1[59]
    DIRECTION INPUT ;
    USE SIGNAL ;
    PORT
      LAYER M4 ;
        RECT  0 30.48 0.084 30.504 ;
    END
  END q1[59]
  PIN q1[5]
    DIRECTION INPUT ;
    USE SIGNAL ;
    PORT
      LAYER M4 ;
        RECT  0 3.024 0.084 3.048 ;
    END
  END q1[5]
  PIN q1[60]
    DIRECTION INPUT ;
    USE SIGNAL ;
    PORT
      LAYER M4 ;
        RECT  0 30.576 0.084 30.6 ;
    END
  END q1[60]
  PIN q1[61]
    DIRECTION INPUT ;
    USE SIGNAL ;
    PORT
      LAYER M4 ;
        RECT  0 30.672 0.084 30.696 ;
    END
  END q1[61]
  PIN q1[62]
    DIRECTION INPUT ;
    USE SIGNAL ;
    PORT
      LAYER M4 ;
        RECT  0 30.768 0.084 30.792 ;
    END
  END q1[62]
  PIN q1[63]
    DIRECTION INPUT ;
    USE SIGNAL ;
    PORT
      LAYER M4 ;
        RECT  0 30.864 0.084 30.888 ;
    END
  END q1[63]
  PIN q1[64]
    DIRECTION INPUT ;
    USE SIGNAL ;
    PORT
      LAYER M4 ;
        RECT  0 30.96 0.084 30.984 ;
    END
  END q1[64]
  PIN q1[65]
    DIRECTION INPUT ;
    USE SIGNAL ;
    PORT
      LAYER M4 ;
        RECT  0 31.056 0.084 31.08 ;
    END
  END q1[65]
  PIN q1[66]
    DIRECTION INPUT ;
    USE SIGNAL ;
    PORT
      LAYER M4 ;
        RECT  0 31.152 0.084 31.176 ;
    END
  END q1[66]
  PIN q1[67]
    DIRECTION INPUT ;
    USE SIGNAL ;
    PORT
      LAYER M4 ;
        RECT  0 31.248 0.084 31.272 ;
    END
  END q1[67]
  PIN q1[68]
    DIRECTION INPUT ;
    USE SIGNAL ;
    PORT
      LAYER M4 ;
        RECT  0 12.144 0.084 12.168 ;
    END
  END q1[68]
  PIN q1[69]
    DIRECTION INPUT ;
    USE SIGNAL ;
    PORT
      LAYER M4 ;
        RECT  0 12.24 0.084 12.264 ;
    END
  END q1[69]
  PIN q1[6]
    DIRECTION INPUT ;
    USE SIGNAL ;
    PORT
      LAYER M4 ;
        RECT  0 3.12 0.084 3.144 ;
    END
  END q1[6]
  PIN q1[70]
    DIRECTION INPUT ;
    USE SIGNAL ;
    PORT
      LAYER M4 ;
        RECT  0 12.336 0.084 12.36 ;
    END
  END q1[70]
  PIN q1[71]
    DIRECTION INPUT ;
    USE SIGNAL ;
    PORT
      LAYER M4 ;
        RECT  0 12.432 0.084 12.456 ;
    END
  END q1[71]
  PIN q1[7]
    DIRECTION INPUT ;
    USE SIGNAL ;
    PORT
      LAYER M4 ;
        RECT  0 3.216 0.084 3.24 ;
    END
  END q1[7]
  PIN q1[8]
    DIRECTION INPUT ;
    USE SIGNAL ;
    PORT
      LAYER M4 ;
        RECT  0 3.312 0.084 3.336 ;
    END
  END q1[8]
  PIN q1[9]
    DIRECTION INPUT ;
    USE SIGNAL ;
    PORT
      LAYER M4 ;
        RECT  0 3.408 0.084 3.432 ;
    END
  END q1[9]
  PIN q2[0]
    DIRECTION INPUT ;
    USE SIGNAL ;
    PORT
      LAYER M4 ;
        RECT  0 12.528 0.084 12.552 ;
    END
  END q2[0]
  PIN q2[10]
    DIRECTION INPUT ;
    USE SIGNAL ;
    PORT
      LAYER M4 ;
        RECT  0 13.488 0.084 13.512 ;
    END
  END q2[10]
  PIN q2[11]
    DIRECTION INPUT ;
    USE SIGNAL ;
    PORT
      LAYER M4 ;
        RECT  0 13.584 0.084 13.608 ;
    END
  END q2[11]
  PIN q2[12]
    DIRECTION INPUT ;
    USE SIGNAL ;
    PORT
      LAYER M4 ;
        RECT  0 13.68 0.084 13.704 ;
    END
  END q2[12]
  PIN q2[13]
    DIRECTION INPUT ;
    USE SIGNAL ;
    PORT
      LAYER M4 ;
        RECT  0 13.776 0.084 13.8 ;
    END
  END q2[13]
  PIN q2[14]
    DIRECTION INPUT ;
    USE SIGNAL ;
    PORT
      LAYER M4 ;
        RECT  0 13.872 0.084 13.896 ;
    END
  END q2[14]
  PIN q2[15]
    DIRECTION INPUT ;
    USE SIGNAL ;
    PORT
      LAYER M4 ;
        RECT  0 13.968 0.084 13.992 ;
    END
  END q2[15]
  PIN q2[16]
    DIRECTION INPUT ;
    USE SIGNAL ;
    PORT
      LAYER M4 ;
        RECT  0 14.064 0.084 14.088 ;
    END
  END q2[16]
  PIN q2[17]
    DIRECTION INPUT ;
    USE SIGNAL ;
    PORT
      LAYER M4 ;
        RECT  0 14.16 0.084 14.184 ;
    END
  END q2[17]
  PIN q2[18]
    DIRECTION INPUT ;
    USE SIGNAL ;
    PORT
      LAYER M4 ;
        RECT  0 14.256 0.084 14.28 ;
    END
  END q2[18]
  PIN q2[19]
    DIRECTION INPUT ;
    USE SIGNAL ;
    PORT
      LAYER M4 ;
        RECT  0 14.352 0.084 14.376 ;
    END
  END q2[19]
  PIN q2[1]
    DIRECTION INPUT ;
    USE SIGNAL ;
    PORT
      LAYER M4 ;
        RECT  0 12.624 0.084 12.648 ;
    END
  END q2[1]
  PIN q2[20]
    DIRECTION INPUT ;
    USE SIGNAL ;
    PORT
      LAYER M4 ;
        RECT  0 14.448 0.084 14.472 ;
    END
  END q2[20]
  PIN q2[21]
    DIRECTION INPUT ;
    USE SIGNAL ;
    PORT
      LAYER M4 ;
        RECT  0 14.544 0.084 14.568 ;
    END
  END q2[21]
  PIN q2[22]
    DIRECTION INPUT ;
    USE SIGNAL ;
    PORT
      LAYER M4 ;
        RECT  0 14.64 0.084 14.664 ;
    END
  END q2[22]
  PIN q2[23]
    DIRECTION INPUT ;
    USE SIGNAL ;
    PORT
      LAYER M4 ;
        RECT  0 14.736 0.084 14.76 ;
    END
  END q2[23]
  PIN q2[24]
    DIRECTION INPUT ;
    USE SIGNAL ;
    PORT
      LAYER M4 ;
        RECT  0 14.832 0.084 14.856 ;
    END
  END q2[24]
  PIN q2[25]
    DIRECTION INPUT ;
    USE SIGNAL ;
    PORT
      LAYER M4 ;
        RECT  0 14.928 0.084 14.952 ;
    END
  END q2[25]
  PIN q2[26]
    DIRECTION INPUT ;
    USE SIGNAL ;
    PORT
      LAYER M4 ;
        RECT  0 15.024 0.084 15.048 ;
    END
  END q2[26]
  PIN q2[27]
    DIRECTION INPUT ;
    USE SIGNAL ;
    PORT
      LAYER M4 ;
        RECT  0 15.12 0.084 15.144 ;
    END
  END q2[27]
  PIN q2[28]
    DIRECTION INPUT ;
    USE SIGNAL ;
    PORT
      LAYER M4 ;
        RECT  0 22.128 0.084 22.152 ;
    END
  END q2[28]
  PIN q2[29]
    DIRECTION INPUT ;
    USE SIGNAL ;
    PORT
      LAYER M4 ;
        RECT  0 22.224 0.084 22.248 ;
    END
  END q2[29]
  PIN q2[2]
    DIRECTION INPUT ;
    USE SIGNAL ;
    PORT
      LAYER M4 ;
        RECT  0 12.72 0.084 12.744 ;
    END
  END q2[2]
  PIN q2[30]
    DIRECTION INPUT ;
    USE SIGNAL ;
    PORT
      LAYER M4 ;
        RECT  0 22.32 0.084 22.344 ;
    END
  END q2[30]
  PIN q2[31]
    DIRECTION INPUT ;
    USE SIGNAL ;
    PORT
      LAYER M4 ;
        RECT  0 22.416 0.084 22.44 ;
    END
  END q2[31]
  PIN q2[32]
    DIRECTION INPUT ;
    USE SIGNAL ;
    PORT
      LAYER M4 ;
        RECT  0 22.512 0.084 22.536 ;
    END
  END q2[32]
  PIN q2[33]
    DIRECTION INPUT ;
    USE SIGNAL ;
    PORT
      LAYER M4 ;
        RECT  0 22.608 0.084 22.632 ;
    END
  END q2[33]
  PIN q2[34]
    DIRECTION INPUT ;
    USE SIGNAL ;
    PORT
      LAYER M4 ;
        RECT  0 22.704 0.084 22.728 ;
    END
  END q2[34]
  PIN q2[35]
    DIRECTION INPUT ;
    USE SIGNAL ;
    PORT
      LAYER M4 ;
        RECT  0 22.8 0.084 22.824 ;
    END
  END q2[35]
  PIN q2[36]
    DIRECTION INPUT ;
    USE SIGNAL ;
    PORT
      LAYER M4 ;
        RECT  0 22.896 0.084 22.92 ;
    END
  END q2[36]
  PIN q2[37]
    DIRECTION INPUT ;
    USE SIGNAL ;
    PORT
      LAYER M4 ;
        RECT  0 22.992 0.084 23.016 ;
    END
  END q2[37]
  PIN q2[38]
    DIRECTION INPUT ;
    USE SIGNAL ;
    PORT
      LAYER M4 ;
        RECT  0 23.088 0.084 23.112 ;
    END
  END q2[38]
  PIN q2[39]
    DIRECTION INPUT ;
    USE SIGNAL ;
    PORT
      LAYER M4 ;
        RECT  0 23.184 0.084 23.208 ;
    END
  END q2[39]
  PIN q2[3]
    DIRECTION INPUT ;
    USE SIGNAL ;
    PORT
      LAYER M4 ;
        RECT  0 12.816 0.084 12.84 ;
    END
  END q2[3]
  PIN q2[40]
    DIRECTION INPUT ;
    USE SIGNAL ;
    PORT
      LAYER M4 ;
        RECT  0 23.28 0.084 23.304 ;
    END
  END q2[40]
  PIN q2[41]
    DIRECTION INPUT ;
    USE SIGNAL ;
    PORT
      LAYER M4 ;
        RECT  0 23.376 0.084 23.4 ;
    END
  END q2[41]
  PIN q2[42]
    DIRECTION INPUT ;
    USE SIGNAL ;
    PORT
      LAYER M4 ;
        RECT  0 23.472 0.084 23.496 ;
    END
  END q2[42]
  PIN q2[43]
    DIRECTION INPUT ;
    USE SIGNAL ;
    PORT
      LAYER M4 ;
        RECT  0 23.568 0.084 23.592 ;
    END
  END q2[43]
  PIN q2[44]
    DIRECTION INPUT ;
    USE SIGNAL ;
    PORT
      LAYER M4 ;
        RECT  0 23.664 0.084 23.688 ;
    END
  END q2[44]
  PIN q2[45]
    DIRECTION INPUT ;
    USE SIGNAL ;
    PORT
      LAYER M4 ;
        RECT  0 23.76 0.084 23.784 ;
    END
  END q2[45]
  PIN q2[46]
    DIRECTION INPUT ;
    USE SIGNAL ;
    PORT
      LAYER M4 ;
        RECT  0 23.856 0.084 23.88 ;
    END
  END q2[46]
  PIN q2[47]
    DIRECTION INPUT ;
    USE SIGNAL ;
    PORT
      LAYER M4 ;
        RECT  0 23.952 0.084 23.976 ;
    END
  END q2[47]
  PIN q2[48]
    DIRECTION INPUT ;
    USE SIGNAL ;
    PORT
      LAYER M4 ;
        RECT  0 24.048 0.084 24.072 ;
    END
  END q2[48]
  PIN q2[49]
    DIRECTION INPUT ;
    USE SIGNAL ;
    PORT
      LAYER M4 ;
        RECT  0 24.144 0.084 24.168 ;
    END
  END q2[49]
  PIN q2[4]
    DIRECTION INPUT ;
    USE SIGNAL ;
    PORT
      LAYER M4 ;
        RECT  0 12.912 0.084 12.936 ;
    END
  END q2[4]
  PIN q2[50]
    DIRECTION INPUT ;
    USE SIGNAL ;
    PORT
      LAYER M4 ;
        RECT  0 24.24 0.084 24.264 ;
    END
  END q2[50]
  PIN q2[51]
    DIRECTION INPUT ;
    USE SIGNAL ;
    PORT
      LAYER M4 ;
        RECT  0 24.336 0.084 24.36 ;
    END
  END q2[51]
  PIN q2[52]
    DIRECTION INPUT ;
    USE SIGNAL ;
    PORT
      LAYER M4 ;
        RECT  0 24.432 0.084 24.456 ;
    END
  END q2[52]
  PIN q2[53]
    DIRECTION INPUT ;
    USE SIGNAL ;
    PORT
      LAYER M4 ;
        RECT  0 24.528 0.084 24.552 ;
    END
  END q2[53]
  PIN q2[54]
    DIRECTION INPUT ;
    USE SIGNAL ;
    PORT
      LAYER M4 ;
        RECT  0 24.624 0.084 24.648 ;
    END
  END q2[54]
  PIN q2[55]
    DIRECTION INPUT ;
    USE SIGNAL ;
    PORT
      LAYER M4 ;
        RECT  0 24.72 0.084 24.744 ;
    END
  END q2[55]
  PIN q2[56]
    DIRECTION INPUT ;
    USE SIGNAL ;
    PORT
      LAYER M4 ;
        RECT  0 24.816 0.084 24.84 ;
    END
  END q2[56]
  PIN q2[57]
    DIRECTION INPUT ;
    USE SIGNAL ;
    PORT
      LAYER M4 ;
        RECT  0 24.912 0.084 24.936 ;
    END
  END q2[57]
  PIN q2[58]
    DIRECTION INPUT ;
    USE SIGNAL ;
    PORT
      LAYER M4 ;
        RECT  0 25.008 0.084 25.032 ;
    END
  END q2[58]
  PIN q2[59]
    DIRECTION INPUT ;
    USE SIGNAL ;
    PORT
      LAYER M4 ;
        RECT  0 25.104 0.084 25.128 ;
    END
  END q2[59]
  PIN q2[5]
    DIRECTION INPUT ;
    USE SIGNAL ;
    PORT
      LAYER M4 ;
        RECT  0 13.008 0.084 13.032 ;
    END
  END q2[5]
  PIN q2[60]
    DIRECTION INPUT ;
    USE SIGNAL ;
    PORT
      LAYER M4 ;
        RECT  0 18.288 0.084 18.312 ;
    END
  END q2[60]
  PIN q2[61]
    DIRECTION INPUT ;
    USE SIGNAL ;
    PORT
      LAYER M4 ;
        RECT  0 18.384 0.084 18.408 ;
    END
  END q2[61]
  PIN q2[62]
    DIRECTION INPUT ;
    USE SIGNAL ;
    PORT
      LAYER M4 ;
        RECT  0 18.48 0.084 18.504 ;
    END
  END q2[62]
  PIN q2[63]
    DIRECTION INPUT ;
    USE SIGNAL ;
    PORT
      LAYER M4 ;
        RECT  0 18.576 0.084 18.6 ;
    END
  END q2[63]
  PIN q2[64]
    DIRECTION INPUT ;
    USE SIGNAL ;
    PORT
      LAYER M4 ;
        RECT  0 18.672 0.084 18.696 ;
    END
  END q2[64]
  PIN q2[65]
    DIRECTION INPUT ;
    USE SIGNAL ;
    PORT
      LAYER M4 ;
        RECT  0 18.768 0.084 18.792 ;
    END
  END q2[65]
  PIN q2[66]
    DIRECTION INPUT ;
    USE SIGNAL ;
    PORT
      LAYER M4 ;
        RECT  0 18.864 0.084 18.888 ;
    END
  END q2[66]
  PIN q2[67]
    DIRECTION INPUT ;
    USE SIGNAL ;
    PORT
      LAYER M4 ;
        RECT  0 18.96 0.084 18.984 ;
    END
  END q2[67]
  PIN q2[68]
    DIRECTION INPUT ;
    USE SIGNAL ;
    PORT
      LAYER M4 ;
        RECT  0 19.056 0.084 19.08 ;
    END
  END q2[68]
  PIN q2[69]
    DIRECTION INPUT ;
    USE SIGNAL ;
    PORT
      LAYER M4 ;
        RECT  0 19.152 0.084 19.176 ;
    END
  END q2[69]
  PIN q2[6]
    DIRECTION INPUT ;
    USE SIGNAL ;
    PORT
      LAYER M4 ;
        RECT  0 13.104 0.084 13.128 ;
    END
  END q2[6]
  PIN q2[70]
    DIRECTION INPUT ;
    USE SIGNAL ;
    PORT
      LAYER M4 ;
        RECT  0 19.248 0.084 19.272 ;
    END
  END q2[70]
  PIN q2[71]
    DIRECTION INPUT ;
    USE SIGNAL ;
    PORT
      LAYER M4 ;
        RECT  0 19.344 0.084 19.368 ;
    END
  END q2[71]
  PIN q2[7]
    DIRECTION INPUT ;
    USE SIGNAL ;
    PORT
      LAYER M4 ;
        RECT  0 13.2 0.084 13.224 ;
    END
  END q2[7]
  PIN q2[8]
    DIRECTION INPUT ;
    USE SIGNAL ;
    PORT
      LAYER M4 ;
        RECT  0 13.296 0.084 13.32 ;
    END
  END q2[8]
  PIN q2[9]
    DIRECTION INPUT ;
    USE SIGNAL ;
    PORT
      LAYER M4 ;
        RECT  0 13.392 0.084 13.416 ;
    END
  END q2[9]
  PIN q3[0]
    DIRECTION INPUT ;
    USE SIGNAL ;
    PORT
      LAYER M4 ;
        RECT  0 19.44 0.084 19.464 ;
    END
  END q3[0]
  PIN q3[10]
    DIRECTION INPUT ;
    USE SIGNAL ;
    PORT
      LAYER M4 ;
        RECT  0 20.4 0.084 20.424 ;
    END
  END q3[10]
  PIN q3[11]
    DIRECTION INPUT ;
    USE SIGNAL ;
    PORT
      LAYER M4 ;
        RECT  0 20.496 0.084 20.52 ;
    END
  END q3[11]
  PIN q3[12]
    DIRECTION INPUT ;
    USE SIGNAL ;
    PORT
      LAYER M4 ;
        RECT  0 20.592 0.084 20.616 ;
    END
  END q3[12]
  PIN q3[13]
    DIRECTION INPUT ;
    USE SIGNAL ;
    PORT
      LAYER M4 ;
        RECT  0 20.688 0.084 20.712 ;
    END
  END q3[13]
  PIN q3[14]
    DIRECTION INPUT ;
    USE SIGNAL ;
    PORT
      LAYER M4 ;
        RECT  0 20.784 0.084 20.808 ;
    END
  END q3[14]
  PIN q3[15]
    DIRECTION INPUT ;
    USE SIGNAL ;
    PORT
      LAYER M4 ;
        RECT  0 20.88 0.084 20.904 ;
    END
  END q3[15]
  PIN q3[16]
    DIRECTION INPUT ;
    USE SIGNAL ;
    PORT
      LAYER M4 ;
        RECT  0 20.976 0.084 21 ;
    END
  END q3[16]
  PIN q3[17]
    DIRECTION INPUT ;
    USE SIGNAL ;
    PORT
      LAYER M4 ;
        RECT  0 21.072 0.084 21.096 ;
    END
  END q3[17]
  PIN q3[18]
    DIRECTION INPUT ;
    USE SIGNAL ;
    PORT
      LAYER M4 ;
        RECT  0 21.168 0.084 21.192 ;
    END
  END q3[18]
  PIN q3[19]
    DIRECTION INPUT ;
    USE SIGNAL ;
    PORT
      LAYER M4 ;
        RECT  0 21.264 0.084 21.288 ;
    END
  END q3[19]
  PIN q3[1]
    DIRECTION INPUT ;
    USE SIGNAL ;
    PORT
      LAYER M4 ;
        RECT  0 19.536 0.084 19.56 ;
    END
  END q3[1]
  PIN q3[20]
    DIRECTION INPUT ;
    USE SIGNAL ;
    PORT
      LAYER M4 ;
        RECT  0 15.216 0.084 15.24 ;
    END
  END q3[20]
  PIN q3[21]
    DIRECTION INPUT ;
    USE SIGNAL ;
    PORT
      LAYER M4 ;
        RECT  0 15.312 0.084 15.336 ;
    END
  END q3[21]
  PIN q3[22]
    DIRECTION INPUT ;
    USE SIGNAL ;
    PORT
      LAYER M4 ;
        RECT  0 15.408 0.084 15.432 ;
    END
  END q3[22]
  PIN q3[23]
    DIRECTION INPUT ;
    USE SIGNAL ;
    PORT
      LAYER M4 ;
        RECT  0 15.504 0.084 15.528 ;
    END
  END q3[23]
  PIN q3[24]
    DIRECTION INPUT ;
    USE SIGNAL ;
    PORT
      LAYER M4 ;
        RECT  0 15.6 0.084 15.624 ;
    END
  END q3[24]
  PIN q3[25]
    DIRECTION INPUT ;
    USE SIGNAL ;
    PORT
      LAYER M4 ;
        RECT  0 15.696 0.084 15.72 ;
    END
  END q3[25]
  PIN q3[26]
    DIRECTION INPUT ;
    USE SIGNAL ;
    PORT
      LAYER M4 ;
        RECT  0 15.792 0.084 15.816 ;
    END
  END q3[26]
  PIN q3[27]
    DIRECTION INPUT ;
    USE SIGNAL ;
    PORT
      LAYER M4 ;
        RECT  0 15.888 0.084 15.912 ;
    END
  END q3[27]
  PIN q3[28]
    DIRECTION INPUT ;
    USE SIGNAL ;
    PORT
      LAYER M4 ;
        RECT  0 15.984 0.084 16.008 ;
    END
  END q3[28]
  PIN q3[29]
    DIRECTION INPUT ;
    USE SIGNAL ;
    PORT
      LAYER M4 ;
        RECT  0 16.08 0.084 16.104 ;
    END
  END q3[29]
  PIN q3[2]
    DIRECTION INPUT ;
    USE SIGNAL ;
    PORT
      LAYER M4 ;
        RECT  0 19.632 0.084 19.656 ;
    END
  END q3[2]
  PIN q3[30]
    DIRECTION INPUT ;
    USE SIGNAL ;
    PORT
      LAYER M4 ;
        RECT  0 16.176 0.084 16.2 ;
    END
  END q3[30]
  PIN q3[31]
    DIRECTION INPUT ;
    USE SIGNAL ;
    PORT
      LAYER M4 ;
        RECT  0 16.272 0.084 16.296 ;
    END
  END q3[31]
  PIN q3[32]
    DIRECTION INPUT ;
    USE SIGNAL ;
    PORT
      LAYER M4 ;
        RECT  0 16.368 0.084 16.392 ;
    END
  END q3[32]
  PIN q3[33]
    DIRECTION INPUT ;
    USE SIGNAL ;
    PORT
      LAYER M4 ;
        RECT  0 16.464 0.084 16.488 ;
    END
  END q3[33]
  PIN q3[34]
    DIRECTION INPUT ;
    USE SIGNAL ;
    PORT
      LAYER M4 ;
        RECT  0 16.56 0.084 16.584 ;
    END
  END q3[34]
  PIN q3[35]
    DIRECTION INPUT ;
    USE SIGNAL ;
    PORT
      LAYER M4 ;
        RECT  0 16.656 0.084 16.68 ;
    END
  END q3[35]
  PIN q3[36]
    DIRECTION INPUT ;
    USE SIGNAL ;
    PORT
      LAYER M4 ;
        RECT  0 16.752 0.084 16.776 ;
    END
  END q3[36]
  PIN q3[37]
    DIRECTION INPUT ;
    USE SIGNAL ;
    PORT
      LAYER M4 ;
        RECT  0 16.848 0.084 16.872 ;
    END
  END q3[37]
  PIN q3[38]
    DIRECTION INPUT ;
    USE SIGNAL ;
    PORT
      LAYER M4 ;
        RECT  0 16.944 0.084 16.968 ;
    END
  END q3[38]
  PIN q3[39]
    DIRECTION INPUT ;
    USE SIGNAL ;
    PORT
      LAYER M4 ;
        RECT  0 17.04 0.084 17.064 ;
    END
  END q3[39]
  PIN q3[3]
    DIRECTION INPUT ;
    USE SIGNAL ;
    PORT
      LAYER M4 ;
        RECT  0 19.728 0.084 19.752 ;
    END
  END q3[3]
  PIN q3[40]
    DIRECTION INPUT ;
    USE SIGNAL ;
    PORT
      LAYER M4 ;
        RECT  0 17.136 0.084 17.16 ;
    END
  END q3[40]
  PIN q3[41]
    DIRECTION INPUT ;
    USE SIGNAL ;
    PORT
      LAYER M4 ;
        RECT  0 17.232 0.084 17.256 ;
    END
  END q3[41]
  PIN q3[42]
    DIRECTION INPUT ;
    USE SIGNAL ;
    PORT
      LAYER M4 ;
        RECT  0 17.328 0.084 17.352 ;
    END
  END q3[42]
  PIN q3[43]
    DIRECTION INPUT ;
    USE SIGNAL ;
    PORT
      LAYER M4 ;
        RECT  0 17.424 0.084 17.448 ;
    END
  END q3[43]
  PIN q3[44]
    DIRECTION INPUT ;
    USE SIGNAL ;
    PORT
      LAYER M4 ;
        RECT  0 17.52 0.084 17.544 ;
    END
  END q3[44]
  PIN q3[45]
    DIRECTION INPUT ;
    USE SIGNAL ;
    PORT
      LAYER M4 ;
        RECT  0 17.616 0.084 17.64 ;
    END
  END q3[45]
  PIN q3[46]
    DIRECTION INPUT ;
    USE SIGNAL ;
    PORT
      LAYER M4 ;
        RECT  0 17.712 0.084 17.736 ;
    END
  END q3[46]
  PIN q3[47]
    DIRECTION INPUT ;
    USE SIGNAL ;
    PORT
      LAYER M4 ;
        RECT  0 17.808 0.084 17.832 ;
    END
  END q3[47]
  PIN q3[48]
    DIRECTION INPUT ;
    USE SIGNAL ;
    PORT
      LAYER M4 ;
        RECT  0 17.904 0.084 17.928 ;
    END
  END q3[48]
  PIN q3[49]
    DIRECTION INPUT ;
    USE SIGNAL ;
    PORT
      LAYER M4 ;
        RECT  0 18 0.084 18.024 ;
    END
  END q3[49]
  PIN q3[4]
    DIRECTION INPUT ;
    USE SIGNAL ;
    PORT
      LAYER M4 ;
        RECT  0 19.824 0.084 19.848 ;
    END
  END q3[4]
  PIN q3[50]
    DIRECTION INPUT ;
    USE SIGNAL ;
    PORT
      LAYER M4 ;
        RECT  0 18.096 0.084 18.12 ;
    END
  END q3[50]
  PIN q3[51]
    DIRECTION INPUT ;
    USE SIGNAL ;
    PORT
      LAYER M4 ;
        RECT  0 18.192 0.084 18.216 ;
    END
  END q3[51]
  PIN q3[52]
    DIRECTION INPUT ;
    USE SIGNAL ;
    PORT
      LAYER M4 ;
        RECT  0 31.344 0.084 31.368 ;
    END
  END q3[52]
  PIN q3[53]
    DIRECTION INPUT ;
    USE SIGNAL ;
    PORT
      LAYER M4 ;
        RECT  0 31.44 0.084 31.464 ;
    END
  END q3[53]
  PIN q3[54]
    DIRECTION INPUT ;
    USE SIGNAL ;
    PORT
      LAYER M4 ;
        RECT  0 31.536 0.084 31.56 ;
    END
  END q3[54]
  PIN q3[55]
    DIRECTION INPUT ;
    USE SIGNAL ;
    PORT
      LAYER M4 ;
        RECT  0 31.632 0.084 31.656 ;
    END
  END q3[55]
  PIN q3[56]
    DIRECTION INPUT ;
    USE SIGNAL ;
    PORT
      LAYER M4 ;
        RECT  0 31.728 0.084 31.752 ;
    END
  END q3[56]
  PIN q3[57]
    DIRECTION INPUT ;
    USE SIGNAL ;
    PORT
      LAYER M4 ;
        RECT  0 31.824 0.084 31.848 ;
    END
  END q3[57]
  PIN q3[58]
    DIRECTION INPUT ;
    USE SIGNAL ;
    PORT
      LAYER M4 ;
        RECT  0 31.92 0.084 31.944 ;
    END
  END q3[58]
  PIN q3[59]
    DIRECTION INPUT ;
    USE SIGNAL ;
    PORT
      LAYER M4 ;
        RECT  0 32.016 0.084 32.04 ;
    END
  END q3[59]
  PIN q3[5]
    DIRECTION INPUT ;
    USE SIGNAL ;
    PORT
      LAYER M4 ;
        RECT  0 19.92 0.084 19.944 ;
    END
  END q3[5]
  PIN q3[60]
    DIRECTION INPUT ;
    USE SIGNAL ;
    PORT
      LAYER M4 ;
        RECT  0 32.112 0.084 32.136 ;
    END
  END q3[60]
  PIN q3[61]
    DIRECTION INPUT ;
    USE SIGNAL ;
    PORT
      LAYER M4 ;
        RECT  0 32.208 0.084 32.232 ;
    END
  END q3[61]
  PIN q3[62]
    DIRECTION INPUT ;
    USE SIGNAL ;
    PORT
      LAYER M4 ;
        RECT  0 32.304 0.084 32.328 ;
    END
  END q3[62]
  PIN q3[63]
    DIRECTION INPUT ;
    USE SIGNAL ;
    PORT
      LAYER M4 ;
        RECT  0 32.4 0.084 32.424 ;
    END
  END q3[63]
  PIN q3[64]
    DIRECTION INPUT ;
    USE SIGNAL ;
    PORT
      LAYER M4 ;
        RECT  0 32.496 0.084 32.52 ;
    END
  END q3[64]
  PIN q3[65]
    DIRECTION INPUT ;
    USE SIGNAL ;
    PORT
      LAYER M4 ;
        RECT  0 32.592 0.084 32.616 ;
    END
  END q3[65]
  PIN q3[66]
    DIRECTION INPUT ;
    USE SIGNAL ;
    PORT
      LAYER M4 ;
        RECT  0 32.688 0.084 32.712 ;
    END
  END q3[66]
  PIN q3[67]
    DIRECTION INPUT ;
    USE SIGNAL ;
    PORT
      LAYER M4 ;
        RECT  0 32.784 0.084 32.808 ;
    END
  END q3[67]
  PIN q3[68]
    DIRECTION INPUT ;
    USE SIGNAL ;
    PORT
      LAYER M4 ;
        RECT  0 32.88 0.084 32.904 ;
    END
  END q3[68]
  PIN q3[69]
    DIRECTION INPUT ;
    USE SIGNAL ;
    PORT
      LAYER M4 ;
        RECT  0 32.976 0.084 33 ;
    END
  END q3[69]
  PIN q3[6]
    DIRECTION INPUT ;
    USE SIGNAL ;
    PORT
      LAYER M4 ;
        RECT  0 20.016 0.084 20.04 ;
    END
  END q3[6]
  PIN q3[70]
    DIRECTION INPUT ;
    USE SIGNAL ;
    PORT
      LAYER M4 ;
        RECT  0 33.072 0.084 33.096 ;
    END
  END q3[70]
  PIN q3[71]
    DIRECTION INPUT ;
    USE SIGNAL ;
    PORT
      LAYER M4 ;
        RECT  0 33.168 0.084 33.192 ;
    END
  END q3[71]
  PIN q3[7]
    DIRECTION INPUT ;
    USE SIGNAL ;
    PORT
      LAYER M4 ;
        RECT  0 20.112 0.084 20.136 ;
    END
  END q3[7]
  PIN q3[8]
    DIRECTION INPUT ;
    USE SIGNAL ;
    PORT
      LAYER M4 ;
        RECT  0 20.208 0.084 20.232 ;
    END
  END q3[8]
  PIN q3[9]
    DIRECTION INPUT ;
    USE SIGNAL ;
    PORT
      LAYER M4 ;
        RECT  0 20.304 0.084 20.328 ;
    END
  END q3[9]
  PIN q4[0]
    DIRECTION INPUT ;
    USE SIGNAL ;
    PORT
      LAYER M4 ;
        RECT  0 33.264 0.084 33.288 ;
    END
  END q4[0]
  PIN q4[10]
    DIRECTION INPUT ;
    USE SIGNAL ;
    PORT
      LAYER M4 ;
        RECT  0 34.224 0.084 34.248 ;
    END
  END q4[10]
  PIN q4[11]
    DIRECTION INPUT ;
    USE SIGNAL ;
    PORT
      LAYER M4 ;
        RECT  0 34.32 0.084 34.344 ;
    END
  END q4[11]
  PIN q4[12]
    DIRECTION INPUT ;
    USE SIGNAL ;
    PORT
      LAYER M4 ;
        RECT  0 9.072 0.084 9.096 ;
    END
  END q4[12]
  PIN q4[13]
    DIRECTION INPUT ;
    USE SIGNAL ;
    PORT
      LAYER M4 ;
        RECT  0 9.168 0.084 9.192 ;
    END
  END q4[13]
  PIN q4[14]
    DIRECTION INPUT ;
    USE SIGNAL ;
    PORT
      LAYER M4 ;
        RECT  0 9.264 0.084 9.288 ;
    END
  END q4[14]
  PIN q4[15]
    DIRECTION INPUT ;
    USE SIGNAL ;
    PORT
      LAYER M4 ;
        RECT  0 9.36 0.084 9.384 ;
    END
  END q4[15]
  PIN q4[16]
    DIRECTION INPUT ;
    USE SIGNAL ;
    PORT
      LAYER M4 ;
        RECT  0 9.456 0.084 9.48 ;
    END
  END q4[16]
  PIN q4[17]
    DIRECTION INPUT ;
    USE SIGNAL ;
    PORT
      LAYER M4 ;
        RECT  0 9.552 0.084 9.576 ;
    END
  END q4[17]
  PIN q4[18]
    DIRECTION INPUT ;
    USE SIGNAL ;
    PORT
      LAYER M4 ;
        RECT  0 9.648 0.084 9.672 ;
    END
  END q4[18]
  PIN q4[19]
    DIRECTION INPUT ;
    USE SIGNAL ;
    PORT
      LAYER M4 ;
        RECT  0 9.744 0.084 9.768 ;
    END
  END q4[19]
  PIN q4[1]
    DIRECTION INPUT ;
    USE SIGNAL ;
    PORT
      LAYER M4 ;
        RECT  0 33.36 0.084 33.384 ;
    END
  END q4[1]
  PIN q4[20]
    DIRECTION INPUT ;
    USE SIGNAL ;
    PORT
      LAYER M4 ;
        RECT  0 9.84 0.084 9.864 ;
    END
  END q4[20]
  PIN q4[21]
    DIRECTION INPUT ;
    USE SIGNAL ;
    PORT
      LAYER M4 ;
        RECT  0 9.936 0.084 9.96 ;
    END
  END q4[21]
  PIN q4[22]
    DIRECTION INPUT ;
    USE SIGNAL ;
    PORT
      LAYER M4 ;
        RECT  0 10.032 0.084 10.056 ;
    END
  END q4[22]
  PIN q4[23]
    DIRECTION INPUT ;
    USE SIGNAL ;
    PORT
      LAYER M4 ;
        RECT  0 10.128 0.084 10.152 ;
    END
  END q4[23]
  PIN q4[24]
    DIRECTION INPUT ;
    USE SIGNAL ;
    PORT
      LAYER M4 ;
        RECT  0 10.224 0.084 10.248 ;
    END
  END q4[24]
  PIN q4[25]
    DIRECTION INPUT ;
    USE SIGNAL ;
    PORT
      LAYER M4 ;
        RECT  0 10.32 0.084 10.344 ;
    END
  END q4[25]
  PIN q4[26]
    DIRECTION INPUT ;
    USE SIGNAL ;
    PORT
      LAYER M4 ;
        RECT  0 10.416 0.084 10.44 ;
    END
  END q4[26]
  PIN q4[27]
    DIRECTION INPUT ;
    USE SIGNAL ;
    PORT
      LAYER M4 ;
        RECT  0 10.512 0.084 10.536 ;
    END
  END q4[27]
  PIN q4[28]
    DIRECTION INPUT ;
    USE SIGNAL ;
    PORT
      LAYER M4 ;
        RECT  0 10.608 0.084 10.632 ;
    END
  END q4[28]
  PIN q4[29]
    DIRECTION INPUT ;
    USE SIGNAL ;
    PORT
      LAYER M4 ;
        RECT  0 10.704 0.084 10.728 ;
    END
  END q4[29]
  PIN q4[2]
    DIRECTION INPUT ;
    USE SIGNAL ;
    PORT
      LAYER M4 ;
        RECT  0 33.456 0.084 33.48 ;
    END
  END q4[2]
  PIN q4[30]
    DIRECTION INPUT ;
    USE SIGNAL ;
    PORT
      LAYER M4 ;
        RECT  0 10.8 0.084 10.824 ;
    END
  END q4[30]
  PIN q4[31]
    DIRECTION INPUT ;
    USE SIGNAL ;
    PORT
      LAYER M4 ;
        RECT  0 10.896 0.084 10.92 ;
    END
  END q4[31]
  PIN q4[32]
    DIRECTION INPUT ;
    USE SIGNAL ;
    PORT
      LAYER M4 ;
        RECT  0 10.992 0.084 11.016 ;
    END
  END q4[32]
  PIN q4[33]
    DIRECTION INPUT ;
    USE SIGNAL ;
    PORT
      LAYER M4 ;
        RECT  0 11.088 0.084 11.112 ;
    END
  END q4[33]
  PIN q4[34]
    DIRECTION INPUT ;
    USE SIGNAL ;
    PORT
      LAYER M4 ;
        RECT  0 11.184 0.084 11.208 ;
    END
  END q4[34]
  PIN q4[35]
    DIRECTION INPUT ;
    USE SIGNAL ;
    PORT
      LAYER M4 ;
        RECT  0 11.28 0.084 11.304 ;
    END
  END q4[35]
  PIN q4[36]
    DIRECTION INPUT ;
    USE SIGNAL ;
    PORT
      LAYER M4 ;
        RECT  0 11.376 0.084 11.4 ;
    END
  END q4[36]
  PIN q4[37]
    DIRECTION INPUT ;
    USE SIGNAL ;
    PORT
      LAYER M4 ;
        RECT  0 11.472 0.084 11.496 ;
    END
  END q4[37]
  PIN q4[38]
    DIRECTION INPUT ;
    USE SIGNAL ;
    PORT
      LAYER M4 ;
        RECT  0 11.568 0.084 11.592 ;
    END
  END q4[38]
  PIN q4[39]
    DIRECTION INPUT ;
    USE SIGNAL ;
    PORT
      LAYER M4 ;
        RECT  0 11.664 0.084 11.688 ;
    END
  END q4[39]
  PIN q4[3]
    DIRECTION INPUT ;
    USE SIGNAL ;
    PORT
      LAYER M4 ;
        RECT  0 33.552 0.084 33.576 ;
    END
  END q4[3]
  PIN q4[40]
    DIRECTION INPUT ;
    USE SIGNAL ;
    PORT
      LAYER M4 ;
        RECT  0 11.76 0.084 11.784 ;
    END
  END q4[40]
  PIN q4[41]
    DIRECTION INPUT ;
    USE SIGNAL ;
    PORT
      LAYER M4 ;
        RECT  0 11.856 0.084 11.88 ;
    END
  END q4[41]
  PIN q4[42]
    DIRECTION INPUT ;
    USE SIGNAL ;
    PORT
      LAYER M4 ;
        RECT  0 11.952 0.084 11.976 ;
    END
  END q4[42]
  PIN q4[43]
    DIRECTION INPUT ;
    USE SIGNAL ;
    PORT
      LAYER M4 ;
        RECT  0 12.048 0.084 12.072 ;
    END
  END q4[43]
  PIN q4[44]
    DIRECTION INPUT ;
    USE SIGNAL ;
    PORT
      LAYER M4 ;
        RECT  0 37.488 0.084 37.512 ;
    END
  END q4[44]
  PIN q4[45]
    DIRECTION INPUT ;
    USE SIGNAL ;
    PORT
      LAYER M4 ;
        RECT  0 37.584 0.084 37.608 ;
    END
  END q4[45]
  PIN q4[46]
    DIRECTION INPUT ;
    USE SIGNAL ;
    PORT
      LAYER M4 ;
        RECT  0 37.68 0.084 37.704 ;
    END
  END q4[46]
  PIN q4[47]
    DIRECTION INPUT ;
    USE SIGNAL ;
    PORT
      LAYER M4 ;
        RECT  0 37.776 0.084 37.8 ;
    END
  END q4[47]
  PIN q4[48]
    DIRECTION INPUT ;
    USE SIGNAL ;
    PORT
      LAYER M4 ;
        RECT  0 37.872 0.084 37.896 ;
    END
  END q4[48]
  PIN q4[49]
    DIRECTION INPUT ;
    USE SIGNAL ;
    PORT
      LAYER M4 ;
        RECT  0 37.968 0.084 37.992 ;
    END
  END q4[49]
  PIN q4[4]
    DIRECTION INPUT ;
    USE SIGNAL ;
    PORT
      LAYER M4 ;
        RECT  0 33.648 0.084 33.672 ;
    END
  END q4[4]
  PIN q4[50]
    DIRECTION INPUT ;
    USE SIGNAL ;
    PORT
      LAYER M4 ;
        RECT  0 38.064 0.084 38.088 ;
    END
  END q4[50]
  PIN q4[51]
    DIRECTION INPUT ;
    USE SIGNAL ;
    PORT
      LAYER M4 ;
        RECT  0 38.16 0.084 38.184 ;
    END
  END q4[51]
  PIN q4[52]
    DIRECTION INPUT ;
    USE SIGNAL ;
    PORT
      LAYER M4 ;
        RECT  0 38.256 0.084 38.28 ;
    END
  END q4[52]
  PIN q4[53]
    DIRECTION INPUT ;
    USE SIGNAL ;
    PORT
      LAYER M4 ;
        RECT  0 38.352 0.084 38.376 ;
    END
  END q4[53]
  PIN q4[54]
    DIRECTION INPUT ;
    USE SIGNAL ;
    PORT
      LAYER M4 ;
        RECT  0 38.448 0.084 38.472 ;
    END
  END q4[54]
  PIN q4[55]
    DIRECTION INPUT ;
    USE SIGNAL ;
    PORT
      LAYER M4 ;
        RECT  0 38.544 0.084 38.568 ;
    END
  END q4[55]
  PIN q4[56]
    DIRECTION INPUT ;
    USE SIGNAL ;
    PORT
      LAYER M4 ;
        RECT  0 38.64 0.084 38.664 ;
    END
  END q4[56]
  PIN q4[57]
    DIRECTION INPUT ;
    USE SIGNAL ;
    PORT
      LAYER M4 ;
        RECT  0 38.736 0.084 38.76 ;
    END
  END q4[57]
  PIN q4[58]
    DIRECTION INPUT ;
    USE SIGNAL ;
    PORT
      LAYER M4 ;
        RECT  0 38.832 0.084 38.856 ;
    END
  END q4[58]
  PIN q4[59]
    DIRECTION INPUT ;
    USE SIGNAL ;
    PORT
      LAYER M4 ;
        RECT  0 38.928 0.084 38.952 ;
    END
  END q4[59]
  PIN q4[5]
    DIRECTION INPUT ;
    USE SIGNAL ;
    PORT
      LAYER M4 ;
        RECT  0 33.744 0.084 33.768 ;
    END
  END q4[5]
  PIN q4[60]
    DIRECTION INPUT ;
    USE SIGNAL ;
    PORT
      LAYER M4 ;
        RECT  0 39.024 0.084 39.048 ;
    END
  END q4[60]
  PIN q4[61]
    DIRECTION INPUT ;
    USE SIGNAL ;
    PORT
      LAYER M4 ;
        RECT  0 39.12 0.084 39.144 ;
    END
  END q4[61]
  PIN q4[62]
    DIRECTION INPUT ;
    USE SIGNAL ;
    PORT
      LAYER M4 ;
        RECT  0 39.216 0.084 39.24 ;
    END
  END q4[62]
  PIN q4[63]
    DIRECTION INPUT ;
    USE SIGNAL ;
    PORT
      LAYER M4 ;
        RECT  0 39.312 0.084 39.336 ;
    END
  END q4[63]
  PIN q4[64]
    DIRECTION INPUT ;
    USE SIGNAL ;
    PORT
      LAYER M4 ;
        RECT  0 39.408 0.084 39.432 ;
    END
  END q4[64]
  PIN q4[65]
    DIRECTION INPUT ;
    USE SIGNAL ;
    PORT
      LAYER M4 ;
        RECT  0 39.504 0.084 39.528 ;
    END
  END q4[65]
  PIN q4[66]
    DIRECTION INPUT ;
    USE SIGNAL ;
    PORT
      LAYER M4 ;
        RECT  0 39.6 0.084 39.624 ;
    END
  END q4[66]
  PIN q4[67]
    DIRECTION INPUT ;
    USE SIGNAL ;
    PORT
      LAYER M4 ;
        RECT  0 39.696 0.084 39.72 ;
    END
  END q4[67]
  PIN q4[68]
    DIRECTION INPUT ;
    USE SIGNAL ;
    PORT
      LAYER M4 ;
        RECT  0 39.792 0.084 39.816 ;
    END
  END q4[68]
  PIN q4[69]
    DIRECTION INPUT ;
    USE SIGNAL ;
    PORT
      LAYER M4 ;
        RECT  0 39.888 0.084 39.912 ;
    END
  END q4[69]
  PIN q4[6]
    DIRECTION INPUT ;
    USE SIGNAL ;
    PORT
      LAYER M4 ;
        RECT  0 33.84 0.084 33.864 ;
    END
  END q4[6]
  PIN q4[70]
    DIRECTION INPUT ;
    USE SIGNAL ;
    PORT
      LAYER M4 ;
        RECT  0 39.984 0.084 40.008 ;
    END
  END q4[70]
  PIN q4[71]
    DIRECTION INPUT ;
    USE SIGNAL ;
    PORT
      LAYER M4 ;
        RECT  0 40.08 0.084 40.104 ;
    END
  END q4[71]
  PIN q4[7]
    DIRECTION INPUT ;
    USE SIGNAL ;
    PORT
      LAYER M4 ;
        RECT  0 33.936 0.084 33.96 ;
    END
  END q4[7]
  PIN q4[8]
    DIRECTION INPUT ;
    USE SIGNAL ;
    PORT
      LAYER M4 ;
        RECT  0 34.032 0.084 34.056 ;
    END
  END q4[8]
  PIN q4[9]
    DIRECTION INPUT ;
    USE SIGNAL ;
    PORT
      LAYER M4 ;
        RECT  0 34.128 0.084 34.152 ;
    END
  END q4[9]
  PIN q5[0]
    DIRECTION INPUT ;
    USE SIGNAL ;
    PORT
      LAYER M4 ;
        RECT  0 40.176 0.084 40.2 ;
    END
  END q5[0]
  PIN q5[10]
    DIRECTION INPUT ;
    USE SIGNAL ;
    PORT
      LAYER M4 ;
        RECT  0 41.904 0.084 41.928 ;
    END
  END q5[10]
  PIN q5[11]
    DIRECTION INPUT ;
    USE SIGNAL ;
    PORT
      LAYER M4 ;
        RECT  0 42 0.084 42.024 ;
    END
  END q5[11]
  PIN q5[12]
    DIRECTION INPUT ;
    USE SIGNAL ;
    PORT
      LAYER M4 ;
        RECT  0 42.096 0.084 42.12 ;
    END
  END q5[12]
  PIN q5[13]
    DIRECTION INPUT ;
    USE SIGNAL ;
    PORT
      LAYER M4 ;
        RECT  0 42.192 0.084 42.216 ;
    END
  END q5[13]
  PIN q5[14]
    DIRECTION INPUT ;
    USE SIGNAL ;
    PORT
      LAYER M4 ;
        RECT  0 42.288 0.084 42.312 ;
    END
  END q5[14]
  PIN q5[15]
    DIRECTION INPUT ;
    USE SIGNAL ;
    PORT
      LAYER M4 ;
        RECT  0 42.384 0.084 42.408 ;
    END
  END q5[15]
  PIN q5[16]
    DIRECTION INPUT ;
    USE SIGNAL ;
    PORT
      LAYER M4 ;
        RECT  0 42.48 0.084 42.504 ;
    END
  END q5[16]
  PIN q5[17]
    DIRECTION INPUT ;
    USE SIGNAL ;
    PORT
      LAYER M4 ;
        RECT  0 42.576 0.084 42.6 ;
    END
  END q5[17]
  PIN q5[18]
    DIRECTION INPUT ;
    USE SIGNAL ;
    PORT
      LAYER M4 ;
        RECT  0 42.672 0.084 42.696 ;
    END
  END q5[18]
  PIN q5[19]
    DIRECTION INPUT ;
    USE SIGNAL ;
    PORT
      LAYER M4 ;
        RECT  0 42.768 0.084 42.792 ;
    END
  END q5[19]
  PIN q5[1]
    DIRECTION INPUT ;
    USE SIGNAL ;
    PORT
      LAYER M4 ;
        RECT  0 40.272 0.084 40.296 ;
    END
  END q5[1]
  PIN q5[20]
    DIRECTION INPUT ;
    USE SIGNAL ;
    PORT
      LAYER M4 ;
        RECT  0 42.864 0.084 42.888 ;
    END
  END q5[20]
  PIN q5[21]
    DIRECTION INPUT ;
    USE SIGNAL ;
    PORT
      LAYER M4 ;
        RECT  0 42.96 0.084 42.984 ;
    END
  END q5[21]
  PIN q5[22]
    DIRECTION INPUT ;
    USE SIGNAL ;
    PORT
      LAYER M4 ;
        RECT  0 43.056 0.084 43.08 ;
    END
  END q5[22]
  PIN q5[23]
    DIRECTION INPUT ;
    USE SIGNAL ;
    PORT
      LAYER M4 ;
        RECT  0 43.152 0.084 43.176 ;
    END
  END q5[23]
  PIN q5[24]
    DIRECTION INPUT ;
    USE SIGNAL ;
    PORT
      LAYER M4 ;
        RECT  0 43.248 0.084 43.272 ;
    END
  END q5[24]
  PIN q5[25]
    DIRECTION INPUT ;
    USE SIGNAL ;
    PORT
      LAYER M4 ;
        RECT  0 43.344 0.084 43.368 ;
    END
  END q5[25]
  PIN q5[26]
    DIRECTION INPUT ;
    USE SIGNAL ;
    PORT
      LAYER M4 ;
        RECT  0 43.44 0.084 43.464 ;
    END
  END q5[26]
  PIN q5[27]
    DIRECTION INPUT ;
    USE SIGNAL ;
    PORT
      LAYER M4 ;
        RECT  0 43.536 0.084 43.56 ;
    END
  END q5[27]
  PIN q5[28]
    DIRECTION INPUT ;
    USE SIGNAL ;
    PORT
      LAYER M4 ;
        RECT  0 43.632 0.084 43.656 ;
    END
  END q5[28]
  PIN q5[29]
    DIRECTION INPUT ;
    USE SIGNAL ;
    PORT
      LAYER M4 ;
        RECT  0 43.728 0.084 43.752 ;
    END
  END q5[29]
  PIN q5[2]
    DIRECTION INPUT ;
    USE SIGNAL ;
    PORT
      LAYER M4 ;
        RECT  0 40.368 0.084 40.392 ;
    END
  END q5[2]
  PIN q5[30]
    DIRECTION INPUT ;
    USE SIGNAL ;
    PORT
      LAYER M4 ;
        RECT  0 43.824 0.084 43.848 ;
    END
  END q5[30]
  PIN q5[31]
    DIRECTION INPUT ;
    USE SIGNAL ;
    PORT
      LAYER M4 ;
        RECT  0 43.92 0.084 43.944 ;
    END
  END q5[31]
  PIN q5[32]
    DIRECTION INPUT ;
    USE SIGNAL ;
    PORT
      LAYER M4 ;
        RECT  0 44.016 0.084 44.04 ;
    END
  END q5[32]
  PIN q5[33]
    DIRECTION INPUT ;
    USE SIGNAL ;
    PORT
      LAYER M4 ;
        RECT  0 44.112 0.084 44.136 ;
    END
  END q5[33]
  PIN q5[34]
    DIRECTION INPUT ;
    USE SIGNAL ;
    PORT
      LAYER M4 ;
        RECT  0 44.208 0.084 44.232 ;
    END
  END q5[34]
  PIN q5[35]
    DIRECTION INPUT ;
    USE SIGNAL ;
    PORT
      LAYER M4 ;
        RECT  0 44.304 0.084 44.328 ;
    END
  END q5[35]
  PIN q5[36]
    DIRECTION INPUT ;
    USE SIGNAL ;
    PORT
      LAYER M4 ;
        RECT  0 44.4 0.084 44.424 ;
    END
  END q5[36]
  PIN q5[37]
    DIRECTION INPUT ;
    USE SIGNAL ;
    PORT
      LAYER M4 ;
        RECT  0 44.496 0.084 44.52 ;
    END
  END q5[37]
  PIN q5[38]
    DIRECTION INPUT ;
    USE SIGNAL ;
    PORT
      LAYER M4 ;
        RECT  0 44.592 0.084 44.616 ;
    END
  END q5[38]
  PIN q5[39]
    DIRECTION INPUT ;
    USE SIGNAL ;
    PORT
      LAYER M4 ;
        RECT  0 44.688 0.084 44.712 ;
    END
  END q5[39]
  PIN q5[3]
    DIRECTION INPUT ;
    USE SIGNAL ;
    PORT
      LAYER M4 ;
        RECT  0 40.464 0.084 40.488 ;
    END
  END q5[3]
  PIN q5[40]
    DIRECTION INPUT ;
    USE SIGNAL ;
    PORT
      LAYER M4 ;
        RECT  0 44.784 0.084 44.808 ;
    END
  END q5[40]
  PIN q5[41]
    DIRECTION INPUT ;
    USE SIGNAL ;
    PORT
      LAYER M4 ;
        RECT  0 44.88 0.084 44.904 ;
    END
  END q5[41]
  PIN q5[42]
    DIRECTION INPUT ;
    USE SIGNAL ;
    PORT
      LAYER M4 ;
        RECT  0 44.976 0.084 45 ;
    END
  END q5[42]
  PIN q5[43]
    DIRECTION INPUT ;
    USE SIGNAL ;
    PORT
      LAYER M4 ;
        RECT  0 45.072 0.084 45.096 ;
    END
  END q5[43]
  PIN q5[44]
    DIRECTION INPUT ;
    USE SIGNAL ;
    PORT
      LAYER M4 ;
        RECT  0 45.168 0.084 45.192 ;
    END
  END q5[44]
  PIN q5[45]
    DIRECTION INPUT ;
    USE SIGNAL ;
    PORT
      LAYER M4 ;
        RECT  0 45.264 0.084 45.288 ;
    END
  END q5[45]
  PIN q5[46]
    DIRECTION INPUT ;
    USE SIGNAL ;
    PORT
      LAYER M4 ;
        RECT  0 45.36 0.084 45.384 ;
    END
  END q5[46]
  PIN q5[47]
    DIRECTION INPUT ;
    USE SIGNAL ;
    PORT
      LAYER M4 ;
        RECT  0 45.456 0.084 45.48 ;
    END
  END q5[47]
  PIN q5[48]
    DIRECTION INPUT ;
    USE SIGNAL ;
    PORT
      LAYER M4 ;
        RECT  0 45.552 0.084 45.576 ;
    END
  END q5[48]
  PIN q5[49]
    DIRECTION INPUT ;
    USE SIGNAL ;
    PORT
      LAYER M4 ;
        RECT  0 45.648 0.084 45.672 ;
    END
  END q5[49]
  PIN q5[4]
    DIRECTION INPUT ;
    USE SIGNAL ;
    PORT
      LAYER M4 ;
        RECT  0 41.328 0.084 41.352 ;
    END
  END q5[4]
  PIN q5[50]
    DIRECTION INPUT ;
    USE SIGNAL ;
    PORT
      LAYER M4 ;
        RECT  0 45.744 0.084 45.768 ;
    END
  END q5[50]
  PIN q5[51]
    DIRECTION INPUT ;
    USE SIGNAL ;
    PORT
      LAYER M4 ;
        RECT  0 45.84 0.084 45.864 ;
    END
  END q5[51]
  PIN q5[52]
    DIRECTION INPUT ;
    USE SIGNAL ;
    PORT
      LAYER M4 ;
        RECT  0 45.936 0.084 45.96 ;
    END
  END q5[52]
  PIN q5[53]
    DIRECTION INPUT ;
    USE SIGNAL ;
    PORT
      LAYER M4 ;
        RECT  0 46.032 0.084 46.056 ;
    END
  END q5[53]
  PIN q5[54]
    DIRECTION INPUT ;
    USE SIGNAL ;
    PORT
      LAYER M4 ;
        RECT  0 46.128 0.084 46.152 ;
    END
  END q5[54]
  PIN q5[55]
    DIRECTION INPUT ;
    USE SIGNAL ;
    PORT
      LAYER M4 ;
        RECT  0 46.224 0.084 46.248 ;
    END
  END q5[55]
  PIN q5[56]
    DIRECTION INPUT ;
    USE SIGNAL ;
    PORT
      LAYER M4 ;
        RECT  0 46.32 0.084 46.344 ;
    END
  END q5[56]
  PIN q5[57]
    DIRECTION INPUT ;
    USE SIGNAL ;
    PORT
      LAYER M4 ;
        RECT  0 46.416 0.084 46.44 ;
    END
  END q5[57]
  PIN q5[58]
    DIRECTION INPUT ;
    USE SIGNAL ;
    PORT
      LAYER M4 ;
        RECT  0 46.512 0.084 46.536 ;
    END
  END q5[58]
  PIN q5[59]
    DIRECTION INPUT ;
    USE SIGNAL ;
    PORT
      LAYER M4 ;
        RECT  0 46.608 0.084 46.632 ;
    END
  END q5[59]
  PIN q5[5]
    DIRECTION INPUT ;
    USE SIGNAL ;
    PORT
      LAYER M4 ;
        RECT  0 41.424 0.084 41.448 ;
    END
  END q5[5]
  PIN q5[60]
    DIRECTION INPUT ;
    USE SIGNAL ;
    PORT
      LAYER M4 ;
        RECT  0 46.704 0.084 46.728 ;
    END
  END q5[60]
  PIN q5[61]
    DIRECTION INPUT ;
    USE SIGNAL ;
    PORT
      LAYER M4 ;
        RECT  0 46.8 0.084 46.824 ;
    END
  END q5[61]
  PIN q5[62]
    DIRECTION INPUT ;
    USE SIGNAL ;
    PORT
      LAYER M4 ;
        RECT  0 46.896 0.084 46.92 ;
    END
  END q5[62]
  PIN q5[63]
    DIRECTION INPUT ;
    USE SIGNAL ;
    PORT
      LAYER M4 ;
        RECT  0 46.992 0.084 47.016 ;
    END
  END q5[63]
  PIN q5[64]
    DIRECTION INPUT ;
    USE SIGNAL ;
    PORT
      LAYER M4 ;
        RECT  0 47.088 0.084 47.112 ;
    END
  END q5[64]
  PIN q5[65]
    DIRECTION INPUT ;
    USE SIGNAL ;
    PORT
      LAYER M4 ;
        RECT  0 47.184 0.084 47.208 ;
    END
  END q5[65]
  PIN q5[66]
    DIRECTION INPUT ;
    USE SIGNAL ;
    PORT
      LAYER M4 ;
        RECT  0 47.28 0.084 47.304 ;
    END
  END q5[66]
  PIN q5[67]
    DIRECTION INPUT ;
    USE SIGNAL ;
    PORT
      LAYER M4 ;
        RECT  0 47.376 0.084 47.4 ;
    END
  END q5[67]
  PIN q5[68]
    DIRECTION INPUT ;
    USE SIGNAL ;
    PORT
      LAYER M4 ;
        RECT  0 50.544 0.084 50.568 ;
    END
  END q5[68]
  PIN q5[69]
    DIRECTION INPUT ;
    USE SIGNAL ;
    PORT
      LAYER M4 ;
        RECT  0 50.64 0.084 50.664 ;
    END
  END q5[69]
  PIN q5[6]
    DIRECTION INPUT ;
    USE SIGNAL ;
    PORT
      LAYER M4 ;
        RECT  0 41.52 0.084 41.544 ;
    END
  END q5[6]
  PIN q5[70]
    DIRECTION INPUT ;
    USE SIGNAL ;
    PORT
      LAYER M4 ;
        RECT  0 50.736 0.084 50.76 ;
    END
  END q5[70]
  PIN q5[71]
    DIRECTION INPUT ;
    USE SIGNAL ;
    PORT
      LAYER M4 ;
        RECT  0 50.832 0.084 50.856 ;
    END
  END q5[71]
  PIN q5[7]
    DIRECTION INPUT ;
    USE SIGNAL ;
    PORT
      LAYER M4 ;
        RECT  0 41.616 0.084 41.64 ;
    END
  END q5[7]
  PIN q5[8]
    DIRECTION INPUT ;
    USE SIGNAL ;
    PORT
      LAYER M4 ;
        RECT  0 41.712 0.084 41.736 ;
    END
  END q5[8]
  PIN q5[9]
    DIRECTION INPUT ;
    USE SIGNAL ;
    PORT
      LAYER M4 ;
        RECT  0 41.808 0.084 41.832 ;
    END
  END q5[9]
  PIN q6[0]
    DIRECTION INPUT ;
    USE SIGNAL ;
    PORT
      LAYER M4 ;
        RECT  0 50.928 0.084 50.952 ;
    END
  END q6[0]
  PIN q6[10]
    DIRECTION INPUT ;
    USE SIGNAL ;
    PORT
      LAYER M4 ;
        RECT  0 51.888 0.084 51.912 ;
    END
  END q6[10]
  PIN q6[11]
    DIRECTION INPUT ;
    USE SIGNAL ;
    PORT
      LAYER M4 ;
        RECT  0 51.984 0.084 52.008 ;
    END
  END q6[11]
  PIN q6[12]
    DIRECTION INPUT ;
    USE SIGNAL ;
    PORT
      LAYER M4 ;
        RECT  0 52.08 0.084 52.104 ;
    END
  END q6[12]
  PIN q6[13]
    DIRECTION INPUT ;
    USE SIGNAL ;
    PORT
      LAYER M4 ;
        RECT  0 52.176 0.084 52.2 ;
    END
  END q6[13]
  PIN q6[14]
    DIRECTION INPUT ;
    USE SIGNAL ;
    PORT
      LAYER M4 ;
        RECT  0 52.272 0.084 52.296 ;
    END
  END q6[14]
  PIN q6[15]
    DIRECTION INPUT ;
    USE SIGNAL ;
    PORT
      LAYER M4 ;
        RECT  0 52.368 0.084 52.392 ;
    END
  END q6[15]
  PIN q6[16]
    DIRECTION INPUT ;
    USE SIGNAL ;
    PORT
      LAYER M4 ;
        RECT  0 52.464 0.084 52.488 ;
    END
  END q6[16]
  PIN q6[17]
    DIRECTION INPUT ;
    USE SIGNAL ;
    PORT
      LAYER M4 ;
        RECT  0 52.56 0.084 52.584 ;
    END
  END q6[17]
  PIN q6[18]
    DIRECTION INPUT ;
    USE SIGNAL ;
    PORT
      LAYER M4 ;
        RECT  0 52.656 0.084 52.68 ;
    END
  END q6[18]
  PIN q6[19]
    DIRECTION INPUT ;
    USE SIGNAL ;
    PORT
      LAYER M4 ;
        RECT  0 52.752 0.084 52.776 ;
    END
  END q6[19]
  PIN q6[1]
    DIRECTION INPUT ;
    USE SIGNAL ;
    PORT
      LAYER M4 ;
        RECT  0 51.024 0.084 51.048 ;
    END
  END q6[1]
  PIN q6[20]
    DIRECTION INPUT ;
    USE SIGNAL ;
    PORT
      LAYER M4 ;
        RECT  0 52.848 0.084 52.872 ;
    END
  END q6[20]
  PIN q6[21]
    DIRECTION INPUT ;
    USE SIGNAL ;
    PORT
      LAYER M4 ;
        RECT  0 52.944 0.084 52.968 ;
    END
  END q6[21]
  PIN q6[22]
    DIRECTION INPUT ;
    USE SIGNAL ;
    PORT
      LAYER M4 ;
        RECT  0 53.04 0.084 53.064 ;
    END
  END q6[22]
  PIN q6[23]
    DIRECTION INPUT ;
    USE SIGNAL ;
    PORT
      LAYER M4 ;
        RECT  0 53.136 0.084 53.16 ;
    END
  END q6[23]
  PIN q6[24]
    DIRECTION INPUT ;
    USE SIGNAL ;
    PORT
      LAYER M4 ;
        RECT  0 53.232 0.084 53.256 ;
    END
  END q6[24]
  PIN q6[25]
    DIRECTION INPUT ;
    USE SIGNAL ;
    PORT
      LAYER M4 ;
        RECT  0 53.328 0.084 53.352 ;
    END
  END q6[25]
  PIN q6[26]
    DIRECTION INPUT ;
    USE SIGNAL ;
    PORT
      LAYER M4 ;
        RECT  0 53.424 0.084 53.448 ;
    END
  END q6[26]
  PIN q6[27]
    DIRECTION INPUT ;
    USE SIGNAL ;
    PORT
      LAYER M4 ;
        RECT  0 53.52 0.084 53.544 ;
    END
  END q6[27]
  PIN q6[28]
    DIRECTION INPUT ;
    USE SIGNAL ;
    PORT
      LAYER M4 ;
        RECT  0 47.472 0.084 47.496 ;
    END
  END q6[28]
  PIN q6[29]
    DIRECTION INPUT ;
    USE SIGNAL ;
    PORT
      LAYER M4 ;
        RECT  0 47.568 0.084 47.592 ;
    END
  END q6[29]
  PIN q6[2]
    DIRECTION INPUT ;
    USE SIGNAL ;
    PORT
      LAYER M4 ;
        RECT  0 51.12 0.084 51.144 ;
    END
  END q6[2]
  PIN q6[30]
    DIRECTION INPUT ;
    USE SIGNAL ;
    PORT
      LAYER M4 ;
        RECT  0 47.664 0.084 47.688 ;
    END
  END q6[30]
  PIN q6[31]
    DIRECTION INPUT ;
    USE SIGNAL ;
    PORT
      LAYER M4 ;
        RECT  0 47.76 0.084 47.784 ;
    END
  END q6[31]
  PIN q6[32]
    DIRECTION INPUT ;
    USE SIGNAL ;
    PORT
      LAYER M4 ;
        RECT  0 47.856 0.084 47.88 ;
    END
  END q6[32]
  PIN q6[33]
    DIRECTION INPUT ;
    USE SIGNAL ;
    PORT
      LAYER M4 ;
        RECT  0 47.952 0.084 47.976 ;
    END
  END q6[33]
  PIN q6[34]
    DIRECTION INPUT ;
    USE SIGNAL ;
    PORT
      LAYER M4 ;
        RECT  0 48.048 0.084 48.072 ;
    END
  END q6[34]
  PIN q6[35]
    DIRECTION INPUT ;
    USE SIGNAL ;
    PORT
      LAYER M4 ;
        RECT  0 48.144 0.084 48.168 ;
    END
  END q6[35]
  PIN q6[36]
    DIRECTION INPUT ;
    USE SIGNAL ;
    PORT
      LAYER M4 ;
        RECT  0 48.24 0.084 48.264 ;
    END
  END q6[36]
  PIN q6[37]
    DIRECTION INPUT ;
    USE SIGNAL ;
    PORT
      LAYER M4 ;
        RECT  0 48.336 0.084 48.36 ;
    END
  END q6[37]
  PIN q6[38]
    DIRECTION INPUT ;
    USE SIGNAL ;
    PORT
      LAYER M4 ;
        RECT  0 48.432 0.084 48.456 ;
    END
  END q6[38]
  PIN q6[39]
    DIRECTION INPUT ;
    USE SIGNAL ;
    PORT
      LAYER M4 ;
        RECT  0 48.528 0.084 48.552 ;
    END
  END q6[39]
  PIN q6[3]
    DIRECTION INPUT ;
    USE SIGNAL ;
    PORT
      LAYER M4 ;
        RECT  0 51.216 0.084 51.24 ;
    END
  END q6[3]
  PIN q6[40]
    DIRECTION INPUT ;
    USE SIGNAL ;
    PORT
      LAYER M4 ;
        RECT  0 48.624 0.084 48.648 ;
    END
  END q6[40]
  PIN q6[41]
    DIRECTION INPUT ;
    USE SIGNAL ;
    PORT
      LAYER M4 ;
        RECT  0 48.72 0.084 48.744 ;
    END
  END q6[41]
  PIN q6[42]
    DIRECTION INPUT ;
    USE SIGNAL ;
    PORT
      LAYER M4 ;
        RECT  0 48.816 0.084 48.84 ;
    END
  END q6[42]
  PIN q6[43]
    DIRECTION INPUT ;
    USE SIGNAL ;
    PORT
      LAYER M4 ;
        RECT  0 48.912 0.084 48.936 ;
    END
  END q6[43]
  PIN q6[44]
    DIRECTION INPUT ;
    USE SIGNAL ;
    PORT
      LAYER M4 ;
        RECT  0 49.008 0.084 49.032 ;
    END
  END q6[44]
  PIN q6[45]
    DIRECTION INPUT ;
    USE SIGNAL ;
    PORT
      LAYER M4 ;
        RECT  0 49.104 0.084 49.128 ;
    END
  END q6[45]
  PIN q6[46]
    DIRECTION INPUT ;
    USE SIGNAL ;
    PORT
      LAYER M4 ;
        RECT  0 49.2 0.084 49.224 ;
    END
  END q6[46]
  PIN q6[47]
    DIRECTION INPUT ;
    USE SIGNAL ;
    PORT
      LAYER M4 ;
        RECT  0 49.296 0.084 49.32 ;
    END
  END q6[47]
  PIN q6[48]
    DIRECTION INPUT ;
    USE SIGNAL ;
    PORT
      LAYER M4 ;
        RECT  0 49.392 0.084 49.416 ;
    END
  END q6[48]
  PIN q6[49]
    DIRECTION INPUT ;
    USE SIGNAL ;
    PORT
      LAYER M4 ;
        RECT  0 49.488 0.084 49.512 ;
    END
  END q6[49]
  PIN q6[4]
    DIRECTION INPUT ;
    USE SIGNAL ;
    PORT
      LAYER M4 ;
        RECT  0 51.312 0.084 51.336 ;
    END
  END q6[4]
  PIN q6[50]
    DIRECTION INPUT ;
    USE SIGNAL ;
    PORT
      LAYER M4 ;
        RECT  0 49.584 0.084 49.608 ;
    END
  END q6[50]
  PIN q6[51]
    DIRECTION INPUT ;
    USE SIGNAL ;
    PORT
      LAYER M4 ;
        RECT  0 49.68 0.084 49.704 ;
    END
  END q6[51]
  PIN q6[52]
    DIRECTION INPUT ;
    USE SIGNAL ;
    PORT
      LAYER M4 ;
        RECT  0 49.776 0.084 49.8 ;
    END
  END q6[52]
  PIN q6[53]
    DIRECTION INPUT ;
    USE SIGNAL ;
    PORT
      LAYER M4 ;
        RECT  0 49.872 0.084 49.896 ;
    END
  END q6[53]
  PIN q6[54]
    DIRECTION INPUT ;
    USE SIGNAL ;
    PORT
      LAYER M4 ;
        RECT  0 49.968 0.084 49.992 ;
    END
  END q6[54]
  PIN q6[55]
    DIRECTION INPUT ;
    USE SIGNAL ;
    PORT
      LAYER M4 ;
        RECT  0 50.064 0.084 50.088 ;
    END
  END q6[55]
  PIN q6[56]
    DIRECTION INPUT ;
    USE SIGNAL ;
    PORT
      LAYER M4 ;
        RECT  0 50.16 0.084 50.184 ;
    END
  END q6[56]
  PIN q6[57]
    DIRECTION INPUT ;
    USE SIGNAL ;
    PORT
      LAYER M4 ;
        RECT  0 50.256 0.084 50.28 ;
    END
  END q6[57]
  PIN q6[58]
    DIRECTION INPUT ;
    USE SIGNAL ;
    PORT
      LAYER M4 ;
        RECT  0 50.352 0.084 50.376 ;
    END
  END q6[58]
  PIN q6[59]
    DIRECTION INPUT ;
    USE SIGNAL ;
    PORT
      LAYER M4 ;
        RECT  0 50.448 0.084 50.472 ;
    END
  END q6[59]
  PIN q6[5]
    DIRECTION INPUT ;
    USE SIGNAL ;
    PORT
      LAYER M4 ;
        RECT  0 51.408 0.084 51.432 ;
    END
  END q6[5]
  PIN q6[60]
    DIRECTION INPUT ;
    USE SIGNAL ;
    PORT
      LAYER M4 ;
        RECT  0 55.536 0.084 55.56 ;
    END
  END q6[60]
  PIN q6[61]
    DIRECTION INPUT ;
    USE SIGNAL ;
    PORT
      LAYER M4 ;
        RECT  0 55.632 0.084 55.656 ;
    END
  END q6[61]
  PIN q6[62]
    DIRECTION INPUT ;
    USE SIGNAL ;
    PORT
      LAYER M4 ;
        RECT  0 55.728 0.084 55.752 ;
    END
  END q6[62]
  PIN q6[63]
    DIRECTION INPUT ;
    USE SIGNAL ;
    PORT
      LAYER M4 ;
        RECT  0 55.824 0.084 55.848 ;
    END
  END q6[63]
  PIN q6[64]
    DIRECTION INPUT ;
    USE SIGNAL ;
    PORT
      LAYER M4 ;
        RECT  0 55.92 0.084 55.944 ;
    END
  END q6[64]
  PIN q6[65]
    DIRECTION INPUT ;
    USE SIGNAL ;
    PORT
      LAYER M4 ;
        RECT  0 56.016 0.084 56.04 ;
    END
  END q6[65]
  PIN q6[66]
    DIRECTION INPUT ;
    USE SIGNAL ;
    PORT
      LAYER M4 ;
        RECT  0 56.112 0.084 56.136 ;
    END
  END q6[66]
  PIN q6[67]
    DIRECTION INPUT ;
    USE SIGNAL ;
    PORT
      LAYER M4 ;
        RECT  0 56.208 0.084 56.232 ;
    END
  END q6[67]
  PIN q6[68]
    DIRECTION INPUT ;
    USE SIGNAL ;
    PORT
      LAYER M4 ;
        RECT  0 56.304 0.084 56.328 ;
    END
  END q6[68]
  PIN q6[69]
    DIRECTION INPUT ;
    USE SIGNAL ;
    PORT
      LAYER M4 ;
        RECT  0 56.4 0.084 56.424 ;
    END
  END q6[69]
  PIN q6[6]
    DIRECTION INPUT ;
    USE SIGNAL ;
    PORT
      LAYER M4 ;
        RECT  0 51.504 0.084 51.528 ;
    END
  END q6[6]
  PIN q6[70]
    DIRECTION INPUT ;
    USE SIGNAL ;
    PORT
      LAYER M4 ;
        RECT  0 56.496 0.084 56.52 ;
    END
  END q6[70]
  PIN q6[71]
    DIRECTION INPUT ;
    USE SIGNAL ;
    PORT
      LAYER M4 ;
        RECT  0 56.592 0.084 56.616 ;
    END
  END q6[71]
  PIN q6[7]
    DIRECTION INPUT ;
    USE SIGNAL ;
    PORT
      LAYER M4 ;
        RECT  0 51.6 0.084 51.624 ;
    END
  END q6[7]
  PIN q6[8]
    DIRECTION INPUT ;
    USE SIGNAL ;
    PORT
      LAYER M4 ;
        RECT  0 51.696 0.084 51.72 ;
    END
  END q6[8]
  PIN q6[9]
    DIRECTION INPUT ;
    USE SIGNAL ;
    PORT
      LAYER M4 ;
        RECT  0 51.792 0.084 51.816 ;
    END
  END q6[9]
  PIN rst_n[0]
    DIRECTION INPUT ;
    USE SIGNAL ;
    PORT
      LAYER M5 ;
        RECT  10.32 0 10.344 0.084 ;
    END
    PORT
      LAYER M5 ;
        RECT  10.32 0.016 10.344 0.131 ;
    END
  END rst_n[0]
  PIN st[0]
    DIRECTION OUTPUT ;
    USE SIGNAL ;
    PORT
      LAYER M4 ;
        RECT  30.156 26.256 30.24 26.28 ;
    END
  END st[0]
  PIN st[1]
    DIRECTION OUTPUT ;
    USE SIGNAL ;
    PORT
      LAYER M4 ;
        RECT  30.156 26.352 30.24 26.376 ;
    END
  END st[1]
  PIN VDD
    DIRECTION INOUT ;
    USE POWER ;
    PORT
      LAYER M5 ;
        RECT  26.892 2.151 27.012 58.329 ;
        RECT  24.192 2.151 24.312 58.329 ;
        RECT  21.492 2.151 21.612 58.329 ;
        RECT  18.792 2.151 18.912 58.329 ;
        RECT  16.092 2.151 16.212 58.329 ;
        RECT  13.392 2.151 13.512 58.329 ;
        RECT  10.692 2.151 10.812 58.329 ;
        RECT  7.992 2.151 8.112 58.329 ;
        RECT  5.292 2.151 5.412 58.329 ;
        RECT  2.592 2.151 2.712 58.329 ;
    END
  END VDD
  PIN VSS
    DIRECTION INOUT ;
    USE GROUND ;
    PORT
      LAYER M5 ;
        RECT  26.7 2.137 26.82 58.343 ;
        RECT  24 2.137 24.12 58.343 ;
        RECT  21.3 2.137 21.42 58.343 ;
        RECT  18.6 2.137 18.72 58.343 ;
        RECT  15.9 2.137 16.02 58.343 ;
        RECT  13.2 2.137 13.32 58.343 ;
        RECT  10.5 2.137 10.62 58.343 ;
        RECT  7.8 2.137 7.92 58.343 ;
        RECT  5.1 2.137 5.22 58.343 ;
        RECT  2.4 2.137 2.52 58.343 ;
    END
  END VSS
  # OT_OBS_CLOSED layer=M5 d_um=1.536 added=80
  OBS
    LAYER RVTN ;
     RECT  2.16 2.16 28.08 2.295 ;
     RECT  2.16 2.565 28.08 2.835 ;
     RECT  2.16 3.105 28.08 3.375 ;
     RECT  2.16 3.645 28.08 3.915 ;
     RECT  2.16 4.185 28.08 4.455 ;
     RECT  2.16 4.725 28.08 4.995 ;
     RECT  2.16 5.265 28.08 5.535 ;
     RECT  2.16 5.805 28.08 6.075 ;
     RECT  2.16 6.345 28.08 6.615 ;
     RECT  2.16 6.885 28.08 7.155 ;
     RECT  2.16 7.425 28.08 7.695 ;
     RECT  2.16 7.965 28.08 8.235 ;
     RECT  2.16 8.505 28.08 8.775 ;
     RECT  2.16 9.045 28.08 9.315 ;
     RECT  2.16 9.585 28.08 9.855 ;
     RECT  2.16 10.125 28.08 10.395 ;
     RECT  2.16 10.665 28.08 10.935 ;
     RECT  2.16 11.205 28.08 11.475 ;
     RECT  2.16 11.745 28.08 12.015 ;
     RECT  2.16 12.285 28.08 12.555 ;
     RECT  2.16 12.825 28.08 13.095 ;
     RECT  2.16 13.365 28.08 13.635 ;
     RECT  2.16 13.905 28.08 14.175 ;
     RECT  2.16 14.445 28.08 14.715 ;
     RECT  2.16 14.985 28.08 15.255 ;
     RECT  2.16 15.525 28.08 15.795 ;
     RECT  2.16 16.065 28.08 16.335 ;
     RECT  2.16 16.605 28.08 16.875 ;
     RECT  2.16 17.145 28.08 17.415 ;
     RECT  2.16 17.685 28.08 17.955 ;
     RECT  2.16 18.225 28.08 18.495 ;
     RECT  2.16 18.765 28.08 19.035 ;
     RECT  2.16 19.305 28.08 19.575 ;
     RECT  2.16 19.845 28.08 20.115 ;
     RECT  2.16 20.385 28.08 20.655 ;
     RECT  2.16 20.925 28.08 21.195 ;
     RECT  2.16 21.465 28.08 21.735 ;
     RECT  2.16 22.005 28.08 22.275 ;
     RECT  2.16 22.545 28.08 22.815 ;
     RECT  2.16 23.085 28.08 23.355 ;
     RECT  2.16 23.625 28.08 23.895 ;
     RECT  2.16 24.165 28.08 24.435 ;
     RECT  2.16 24.705 28.08 24.975 ;
     RECT  2.16 25.245 28.08 25.515 ;
     RECT  2.16 25.785 28.08 26.055 ;
     RECT  2.16 26.325 28.08 26.595 ;
     RECT  2.16 26.865 28.08 27.135 ;
     RECT  2.16 27.405 28.08 27.675 ;
     RECT  2.16 27.945 28.08 28.215 ;
     RECT  2.16 28.485 28.08 28.755 ;
     RECT  2.16 29.025 28.08 29.295 ;
     RECT  2.16 29.565 28.08 29.835 ;
     RECT  2.16 30.105 28.08 30.375 ;
     RECT  2.16 30.645 28.08 30.915 ;
     RECT  2.16 31.185 28.08 31.455 ;
     RECT  2.16 31.725 28.08 31.995 ;
     RECT  2.16 32.265 28.08 32.535 ;
     RECT  2.16 32.805 28.08 33.075 ;
     RECT  2.16 33.345 28.08 33.615 ;
     RECT  2.16 33.885 28.08 34.155 ;
     RECT  2.16 34.425 28.08 34.695 ;
     RECT  2.16 34.965 28.08 35.235 ;
     RECT  2.16 35.505 28.08 35.775 ;
     RECT  2.16 36.045 28.08 36.315 ;
     RECT  2.16 36.585 28.08 36.855 ;
     RECT  2.16 37.125 28.08 37.395 ;
     RECT  2.16 37.665 28.08 37.935 ;
     RECT  2.16 38.205 28.08 38.475 ;
     RECT  2.16 38.745 28.08 39.015 ;
     RECT  2.16 39.285 28.08 39.555 ;
     RECT  2.16 39.825 28.08 40.095 ;
     RECT  2.16 40.365 28.08 40.635 ;
     RECT  2.16 40.905 28.08 41.175 ;
     RECT  2.16 41.445 28.08 41.715 ;
     RECT  2.16 41.985 28.08 42.255 ;
     RECT  2.16 42.525 28.08 42.795 ;
     RECT  2.16 43.065 28.08 43.335 ;
     RECT  2.16 43.605 28.08 43.875 ;
     RECT  2.16 44.145 28.08 44.415 ;
     RECT  2.16 44.685 28.08 44.955 ;
     RECT  2.16 45.225 28.08 45.495 ;
     RECT  2.16 45.765 28.08 46.035 ;
     RECT  2.16 46.305 28.08 46.575 ;
     RECT  2.16 46.845 28.08 47.115 ;
     RECT  2.16 47.385 28.08 47.655 ;
     RECT  2.16 47.925 28.08 48.195 ;
     RECT  2.16 48.465 28.08 48.735 ;
     RECT  2.16 49.005 28.08 49.275 ;
     RECT  2.16 49.545 28.08 49.815 ;
     RECT  2.16 50.085 28.08 50.355 ;
     RECT  2.16 50.625 28.08 50.895 ;
     RECT  2.16 51.165 28.08 51.435 ;
     RECT  2.16 51.705 28.08 51.975 ;
     RECT  2.16 52.245 28.08 52.515 ;
     RECT  2.16 52.785 28.08 53.055 ;
     RECT  2.16 53.325 28.08 53.595 ;
     RECT  2.16 53.865 28.08 54.135 ;
     RECT  2.16 54.405 28.08 54.675 ;
     RECT  2.16 54.945 28.08 55.215 ;
     RECT  2.16 55.485 28.08 55.755 ;
     RECT  2.16 56.025 28.08 56.295 ;
     RECT  2.16 56.565 28.08 56.835 ;
     RECT  2.16 57.105 28.08 57.375 ;
     RECT  2.16 57.645 28.08 57.915 ;
     RECT  2.16 58.185 28.08 58.32 ;
    LAYER RVTP ;
     RECT  2.16 2.295 28.08 2.565 ;
     RECT  2.16 2.835 28.08 3.105 ;
     RECT  2.16 3.375 28.08 3.645 ;
     RECT  2.16 3.915 28.08 4.185 ;
     RECT  2.16 4.455 28.08 4.725 ;
     RECT  2.16 4.995 28.08 5.265 ;
     RECT  2.16 5.535 28.08 5.805 ;
     RECT  2.16 6.075 28.08 6.345 ;
     RECT  2.16 6.615 28.08 6.885 ;
     RECT  2.16 7.155 28.08 7.425 ;
     RECT  2.16 7.695 28.08 7.965 ;
     RECT  2.16 8.235 28.08 8.505 ;
     RECT  2.16 8.775 28.08 9.045 ;
     RECT  2.16 9.315 28.08 9.585 ;
     RECT  2.16 9.855 28.08 10.125 ;
     RECT  2.16 10.395 28.08 10.665 ;
     RECT  2.16 10.935 28.08 11.205 ;
     RECT  2.16 11.475 28.08 11.745 ;
     RECT  2.16 12.015 28.08 12.285 ;
     RECT  2.16 12.555 28.08 12.825 ;
     RECT  2.16 13.095 28.08 13.365 ;
     RECT  2.16 13.635 28.08 13.905 ;
     RECT  2.16 14.175 28.08 14.445 ;
     RECT  2.16 14.715 28.08 14.985 ;
     RECT  2.16 15.255 28.08 15.525 ;
     RECT  2.16 15.795 28.08 16.065 ;
     RECT  2.16 16.335 28.08 16.605 ;
     RECT  2.16 16.875 28.08 17.145 ;
     RECT  2.16 17.415 28.08 17.685 ;
     RECT  2.16 17.955 28.08 18.225 ;
     RECT  2.16 18.495 28.08 18.765 ;
     RECT  2.16 19.035 28.08 19.305 ;
     RECT  2.16 19.575 28.08 19.845 ;
     RECT  2.16 20.115 28.08 20.385 ;
     RECT  2.16 20.655 28.08 20.925 ;
     RECT  2.16 21.195 28.08 21.465 ;
     RECT  2.16 21.735 28.08 22.005 ;
     RECT  2.16 22.275 28.08 22.545 ;
     RECT  2.16 22.815 28.08 23.085 ;
     RECT  2.16 23.355 28.08 23.625 ;
     RECT  2.16 23.895 28.08 24.165 ;
     RECT  2.16 24.435 28.08 24.705 ;
     RECT  2.16 24.975 28.08 25.245 ;
     RECT  2.16 25.515 28.08 25.785 ;
     RECT  2.16 26.055 28.08 26.325 ;
     RECT  2.16 26.595 28.08 26.865 ;
     RECT  2.16 27.135 28.08 27.405 ;
     RECT  2.16 27.675 28.08 27.945 ;
     RECT  2.16 28.215 28.08 28.485 ;
     RECT  2.16 28.755 28.08 29.025 ;
     RECT  2.16 29.295 28.08 29.565 ;
     RECT  2.16 29.835 28.08 30.105 ;
     RECT  2.16 30.375 28.08 30.645 ;
     RECT  2.16 30.915 28.08 31.185 ;
     RECT  2.16 31.455 28.08 31.725 ;
     RECT  2.16 31.995 28.08 32.265 ;
     RECT  2.16 32.535 28.08 32.805 ;
     RECT  2.16 33.075 28.08 33.345 ;
     RECT  2.16 33.615 28.08 33.885 ;
     RECT  2.16 34.155 28.08 34.425 ;
     RECT  2.16 34.695 28.08 34.965 ;
     RECT  2.16 35.235 28.08 35.505 ;
     RECT  2.16 35.775 28.08 36.045 ;
     RECT  2.16 36.315 28.08 36.585 ;
     RECT  2.16 36.855 28.08 37.125 ;
     RECT  2.16 37.395 28.08 37.665 ;
     RECT  2.16 37.935 28.08 38.205 ;
     RECT  2.16 38.475 28.08 38.745 ;
     RECT  2.16 39.015 28.08 39.285 ;
     RECT  2.16 39.555 28.08 39.825 ;
     RECT  2.16 40.095 28.08 40.365 ;
     RECT  2.16 40.635 28.08 40.905 ;
     RECT  2.16 41.175 28.08 41.445 ;
     RECT  2.16 41.715 28.08 41.985 ;
     RECT  2.16 42.255 28.08 42.525 ;
     RECT  2.16 42.795 28.08 43.065 ;
     RECT  2.16 43.335 28.08 43.605 ;
     RECT  2.16 43.875 28.08 44.145 ;
     RECT  2.16 44.415 28.08 44.685 ;
     RECT  2.16 44.955 28.08 45.225 ;
     RECT  2.16 45.495 28.08 45.765 ;
     RECT  2.16 46.035 28.08 46.305 ;
     RECT  2.16 46.575 28.08 46.845 ;
     RECT  2.16 47.115 28.08 47.385 ;
     RECT  2.16 47.655 28.08 47.925 ;
     RECT  2.16 48.195 28.08 48.465 ;
     RECT  2.16 48.735 28.08 49.005 ;
     RECT  2.16 49.275 28.08 49.545 ;
     RECT  2.16 49.815 28.08 50.085 ;
     RECT  2.16 50.355 28.08 50.625 ;
     RECT  2.16 50.895 28.08 51.165 ;
     RECT  2.16 51.435 28.08 51.705 ;
     RECT  2.16 51.975 28.08 52.245 ;
     RECT  2.16 52.515 28.08 52.785 ;
     RECT  2.16 53.055 28.08 53.325 ;
     RECT  2.16 53.595 28.08 53.865 ;
     RECT  2.16 54.135 28.08 54.405 ;
     RECT  2.16 54.675 28.08 54.945 ;
     RECT  2.16 55.215 28.08 55.485 ;
     RECT  2.16 55.755 28.08 56.025 ;
     RECT  2.16 56.295 28.08 56.565 ;
     RECT  2.16 56.835 28.08 57.105 ;
     RECT  2.16 57.375 28.08 57.645 ;
     RECT  2.16 57.915 28.08 58.185 ;
    LAYER M1 ;
     RECT  2.16 2.151 28.08 58.329 ;
    LAYER M2 ;
     RECT  0.031 2.574 0.103 2.592 ;
     RECT  0.031 6.084 0.103 6.102 ;
     RECT  0.103 5.58 0.131 6.102 ;
     RECT  0.103 17.082 0.139 17.1 ;
     RECT  0.103 18.198 0.139 18.72 ;
     RECT  0.103 21.78 0.139 22.5 ;
     RECT  0.103 26.568 0.139 26.586 ;
     RECT  0.103 28.764 0.139 29.484 ;
     RECT  0.103 33.93 0.139 33.948 ;
     RECT  0.103 44.424 0.139 44.442 ;
     RECT  0.103 15.462 0.175 15.48 ;
     RECT  0.139 21.78 0.175 23.04 ;
     RECT  0.139 28.764 0.175 29.709 ;
     RECT  0.103 32.58 0.175 32.598 ;
     RECT  0.139 26.568 0.203 26.658 ;
     RECT  0.175 6.39 0.211 6.408 ;
     RECT  0.175 15.462 0.211 15.75 ;
     RECT  0.139 17.082 0.211 18.72 ;
     RECT  0.103 30.654 0.239 30.672 ;
     RECT  0.103 36.63 0.239 36.648 ;
     RECT  0.103 53.181 0.239 53.199 ;
     RECT  0.211 6.39 0.247 6.57 ;
     RECT  0.175 41.724 0.275 41.742 ;
     RECT  0.203 26.64 0.383 26.658 ;
     RECT  0.175 28.566 0.383 29.709 ;
     RECT  0.211 14.958 0.499 15.75 ;
     RECT  0.211 16.542 0.499 19.296 ;
     RECT  0.175 32.202 0.499 32.598 ;
     RECT  0.499 27.108 0.535 27.126 ;
     RECT  0.383 28.566 0.535 29.628 ;
     RECT  0.499 31.968 0.535 32.598 ;
     RECT  0.139 44.424 0.599 44.91 ;
     RECT  0.175 21.51 1.147 23.04 ;
     RECT  0.499 36.936 1.147 37.386 ;
     RECT  0.103 43.65 1.147 43.668 ;
     RECT  1.147 36.936 1.183 37.458 ;
     RECT  0.535 31.536 1.291 32.598 ;
     RECT  1.147 21.132 1.435 23.04 ;
     RECT  0.131 5.58 1.723 5.598 ;
     RECT  0.247 6.39 1.723 6.84 ;
     RECT  1.147 43.65 1.723 43.938 ;
     RECT  1.147 53.874 1.723 53.892 ;
     RECT  1.723 53.874 1.759 54.468 ;
     RECT  0.103 2.574 2.16 3.6 ;
     RECT  1.723 5.58 2.16 6.84 ;
     RECT  0.103 9.09 2.16 9.108 ;
     RECT  0.103 11.142 2.16 11.16 ;
     RECT  0.103 12.87 2.16 13.59 ;
     RECT  0.499 14.958 2.16 19.8 ;
     RECT  1.435 20.934 2.16 23.04 ;
     RECT  0.103 23.904 2.16 23.922 ;
     RECT  0.103 25.056 2.16 25.074 ;
     RECT  0.535 25.866 2.16 25.884 ;
     RECT  0.535 27.108 2.16 29.628 ;
     RECT  1.291 31.536 2.16 33.102 ;
     RECT  0.139 33.93 2.16 34.11 ;
     RECT  1.147 35.82 2.16 35.838 ;
     RECT  1.183 36.792 2.16 37.458 ;
     RECT  1.687 40.68 2.16 40.698 ;
     RECT  0.535 42.876 2.16 42.894 ;
     RECT  1.723 43.65 2.16 44.1 ;
     RECT  0.599 44.892 2.16 44.91 ;
     RECT  0.571 45.846 2.16 45.864 ;
     RECT  0.175 49.248 2.16 49.266 ;
     RECT  1.759 53.874 2.16 54.504 ;
     RECT  0.535 55.8 2.16 55.818 ;
     RECT  2.16 2.151 4.207 58.329 ;
     RECT  4.207 2.106 5.099 58.329 ;
     RECT  5.099 2.151 21.235 58.329 ;
     RECT  21.163 60.426 21.443 60.444 ;
     RECT  21.235 2.151 21.659 58.482 ;
     RECT  22.351 60.354 22.423 60.372 ;
     RECT  22.423 60.354 22.451 60.444 ;
     RECT  22.451 60.426 22.559 60.444 ;
     RECT  21.659 2.151 24.907 58.329 ;
     RECT  24.907 2.151 25.447 58.446 ;
     RECT  25.447 2.151 25.519 58.752 ;
     RECT  25.519 2.151 25.663 58.788 ;
     RECT  25.663 2.151 25.699 58.824 ;
     RECT  25.699 2.151 26.527 58.869 ;
     RECT  26.527 2.151 27.103 58.914 ;
     RECT  27.103 2.151 27.239 58.95 ;
     RECT  27.239 2.151 27.311 58.824 ;
     RECT  27.311 2.151 28.08 58.329 ;
     RECT  28.08 55.764 28.103 57.024 ;
     RECT  28.08 52.866 28.139 52.884 ;
     RECT  28.103 56.106 28.139 56.358 ;
     RECT  28.139 56.106 28.175 56.124 ;
     RECT  28.08 24.48 29.075 27.594 ;
     RECT  29.075 24.48 29.111 24.498 ;
     RECT  29.075 27.306 29.615 27.594 ;
     RECT  29.075 25.488 29.651 26.316 ;
     RECT  29.615 27.306 29.651 27.324 ;
     RECT  29.651 25.488 29.687 25.578 ;
     RECT  29.687 25.56 30.155 25.578 ;
    LAYER M3 ;
     RECT  5.076 2.101 5.094 2.143 ;
     RECT  4.212 2.101 4.23 2.191 ;
     RECT  5.076 2.143 5.205 2.191 ;
     RECT  3.78 2.191 5.205 2.263 ;
     RECT  3.492 2.263 5.205 2.299 ;
     RECT  3.492 2.299 5.454 2.335 ;
     RECT  2.415 2.143 2.505 2.371 ;
     RECT  3.42 2.335 5.454 2.371 ;
     RECT  7.815 2.143 7.905 2.413 ;
     RECT  10.515 2.143 10.605 2.413 ;
     RECT  13.215 2.143 13.305 2.413 ;
     RECT  15.915 2.143 16.005 2.413 ;
     RECT  18.615 2.143 18.705 2.413 ;
     RECT  21.315 2.143 21.405 2.413 ;
     RECT  24.015 2.143 24.105 2.413 ;
     RECT  26.715 2.143 26.805 2.413 ;
     RECT  0.036 2.569 0.054 2.605 ;
     RECT  7.815 2.413 8.097 2.731 ;
     RECT  2.415 2.371 5.958 2.911 ;
     RECT  6.84 2.641 6.858 2.911 ;
     RECT  7.815 2.731 8.55 2.911 ;
     RECT  2.376 2.911 5.958 3.181 ;
     RECT  6.84 2.911 8.55 3.181 ;
     RECT  0.036 2.605 0.198 3.341 ;
     RECT  2.376 3.181 8.55 3.499 ;
     RECT  11.952 0.091 11.97 3.541 ;
     RECT  2.34 3.499 8.55 3.721 ;
     RECT  2.304 3.721 8.55 3.787 ;
     RECT  0.036 3.341 0.126 4.267 ;
     RECT  2.268 3.787 8.55 4.363 ;
     RECT  0.036 4.267 0.162 4.445 ;
     RECT  2.232 4.363 8.55 4.651 ;
     RECT  11.952 3.541 12.33 4.685 ;
     RECT  1.728 4.651 8.55 4.801 ;
     RECT  1.728 4.801 8.766 4.919 ;
     RECT  0.036 4.445 0.126 5.179 ;
     RECT  9.72 4.531 9.738 5.341 ;
     RECT  0.036 5.179 0.162 5.645 ;
     RECT  1.728 4.919 8.658 5.873 ;
     RECT  1.764 5.873 8.658 5.881 ;
     RECT  0.036 5.645 0.126 6.107 ;
     RECT  9.72 5.341 9.774 6.151 ;
     RECT  10.515 2.413 10.797 6.151 ;
     RECT  1.764 5.881 8.694 6.341 ;
     RECT  0.108 6.107 0.126 6.385 ;
     RECT  0.108 6.385 0.198 6.547 ;
     RECT  2.232 6.341 8.694 6.667 ;
     RECT  2.232 6.667 8.802 6.781 ;
     RECT  0.108 6.547 0.234 6.797 ;
     RECT  0.18 6.797 0.234 6.817 ;
     RECT  2.232 6.781 8.982 6.893 ;
     RECT  0.18 6.817 0.27 6.989 ;
     RECT  0.216 6.989 0.27 7.757 ;
     RECT  2.304 6.893 8.982 7.771 ;
     RECT  9.72 6.151 10.797 7.771 ;
     RECT  2.304 7.771 10.797 7.915 ;
     RECT  2.268 7.915 10.797 7.933 ;
     RECT  0.144 8.155 0.162 8.333 ;
     RECT  2.196 7.933 10.797 8.621 ;
     RECT  13.215 2.413 13.497 8.941 ;
     RECT  12.168 4.685 12.33 9.005 ;
     RECT  0.108 9.085 0.126 9.581 ;
     RECT  2.268 8.621 10.797 10.085 ;
     RECT  0.144 9.931 0.45 10.109 ;
     RECT  0.144 10.109 0.378 10.157 ;
     RECT  12.312 9.005 12.33 10.705 ;
     RECT  2.304 10.085 10.797 11.011 ;
     RECT  0.144 10.157 0.162 11.137 ;
     RECT  0.108 11.137 0.162 11.597 ;
     RECT  2.304 11.011 11.07 11.947 ;
     RECT  0.144 11.597 0.162 12.865 ;
     RECT  2.304 11.947 11.106 12.907 ;
     RECT  2.268 12.907 11.106 13.099 ;
     RECT  0.108 12.865 0.162 13.195 ;
     RECT  2.268 13.099 11.142 13.325 ;
     RECT  0.108 13.195 0.342 13.405 ;
     RECT  1.152 11.227 1.17 13.405 ;
     RECT  0.108 13.405 1.17 13.435 ;
     RECT  2.304 13.325 11.142 13.531 ;
     RECT  11.916 10.705 12.33 13.531 ;
     RECT  13.215 8.941 13.95 13.595 ;
     RECT  15.915 2.413 16.197 13.639 ;
     RECT  0.108 13.435 1.206 13.997 ;
     RECT  0.108 13.997 0.126 14.669 ;
     RECT  1.152 13.997 1.206 14.765 ;
     RECT  15.915 13.639 16.65 14.881 ;
     RECT  0.18 14.953 0.234 15.115 ;
     RECT  0.18 15.115 0.342 15.457 ;
     RECT  0.108 15.457 0.342 15.565 ;
     RECT  1.188 14.765 1.206 15.565 ;
     RECT  13.215 13.595 13.497 15.565 ;
     RECT  13.215 15.565 14.022 15.601 ;
     RECT  14.832 15.493 14.85 15.601 ;
     RECT  0.108 15.565 1.206 15.791 ;
     RECT  13.215 15.601 14.85 15.835 ;
     RECT  13.068 15.835 14.85 15.871 ;
     RECT  13.068 15.871 15.102 15.899 ;
     RECT  2.304 13.531 12.33 16.025 ;
     RECT  13.14 15.899 15.102 16.069 ;
     RECT  15.915 14.881 16.758 16.069 ;
     RECT  0.108 15.791 0.558 16.301 ;
     RECT  17.82 16.375 17.838 16.541 ;
     RECT  13.14 16.069 16.758 16.645 ;
     RECT  0.144 16.301 0.558 16.795 ;
     RECT  13.14 16.645 16.902 16.799 ;
     RECT  0.144 16.795 1.17 16.925 ;
     RECT  13.215 16.799 16.902 16.951 ;
     RECT  0.144 16.925 0.558 17.077 ;
     RECT  0.108 17.077 0.558 17.165 ;
     RECT  2.376 16.025 12.33 17.323 ;
     RECT  2.304 17.323 12.33 17.419 ;
     RECT  2.196 17.419 12.33 17.483 ;
     RECT  13.215 16.951 17.262 17.491 ;
     RECT  13.215 17.491 17.406 17.611 ;
     RECT  2.304 17.483 12.33 17.653 ;
     RECT  13.215 17.611 17.478 17.653 ;
     RECT  0.144 17.165 0.558 17.741 ;
     RECT  18.615 2.413 18.897 17.995 ;
     RECT  2.304 17.653 17.478 18.031 ;
     RECT  18.252 17.995 18.897 18.031 ;
     RECT  0.144 17.741 0.342 18.125 ;
     RECT  0.144 18.125 0.234 18.193 ;
     RECT  2.304 18.031 18.897 18.571 ;
     RECT  2.304 18.571 19.062 18.841 ;
     RECT  0.108 18.193 0.234 19.181 ;
     RECT  2.304 18.841 19.17 19.228 ;
     RECT  21.315 2.413 21.597 19.237 ;
     RECT  2.268 19.228 19.17 19.309 ;
     RECT  1.44 18.379 1.458 19.339 ;
     RECT  2.268 19.309 19.494 19.535 ;
     RECT  0.144 19.181 0.234 19.613 ;
     RECT  1.152 19.339 1.458 19.615 ;
     RECT  2.304 19.535 19.494 19.651 ;
     RECT  0.324 19.615 1.458 20.237 ;
     RECT  0.144 20.347 0.162 20.525 ;
     RECT  2.304 19.651 19.566 20.551 ;
     RECT  20.628 19.237 21.597 20.551 ;
     RECT  1.152 20.237 1.458 20.957 ;
     RECT  1.152 20.957 1.17 21.155 ;
     RECT  0.18 21.505 0.198 21.667 ;
     RECT  0.18 21.667 0.27 21.775 ;
     RECT  2.304 20.551 21.597 22.009 ;
     RECT  2.268 22.009 21.597 22.855 ;
     RECT  22.932 22.711 22.95 22.855 ;
     RECT  0.108 21.775 0.27 22.891 ;
     RECT  2.268 22.855 23.022 22.891 ;
     RECT  24.015 2.413 24.297 22.891 ;
     RECT  0.108 22.891 0.342 23.069 ;
     RECT  2.268 22.891 24.297 23.083 ;
     RECT  2.196 23.083 24.297 23.251 ;
     RECT  25.488 23.251 25.506 23.359 ;
     RECT  2.196 23.251 24.426 23.395 ;
     RECT  25.38 23.359 25.65 23.395 ;
     RECT  2.196 23.395 25.974 23.431 ;
     RECT  26.715 2.413 26.997 23.431 ;
     RECT  0.108 23.069 0.27 23.789 ;
     RECT  2.196 23.431 26.997 23.927 ;
     RECT  2.268 23.927 26.997 24.403 ;
     RECT  2.268 24.403 27.378 24.601 ;
     RECT  2.268 24.601 27.666 24.673 ;
     RECT  29.088 24.475 29.106 24.745 ;
     RECT  2.268 24.673 27.954 24.907 ;
     RECT  1.98 24.907 27.954 24.941 ;
     RECT  29.052 24.745 29.106 24.943 ;
     RECT  1.152 24.715 1.17 25.003 ;
     RECT  1.98 24.941 27.882 25.003 ;
     RECT  0.108 23.789 0.234 25.099 ;
     RECT  0.108 25.099 0.342 25.229 ;
     RECT  29.016 24.943 29.106 25.477 ;
     RECT  30.132 25.387 30.15 25.477 ;
     RECT  29.016 25.477 30.15 25.583 ;
     RECT  1.152 25.003 27.882 25.675 ;
     RECT  29.016 25.583 29.646 25.675 ;
     RECT  0.324 25.229 0.342 25.861 ;
     RECT  1.152 25.675 29.646 25.861 ;
     RECT  0.324 25.861 29.646 26.189 ;
     RECT  0.324 26.189 27.918 26.203 ;
     RECT  0.18 26.203 27.918 26.539 ;
     RECT  0.144 26.539 27.918 26.563 ;
     RECT  29.016 26.189 29.646 26.591 ;
     RECT  0.108 26.563 27.918 26.669 ;
     RECT  29.052 26.591 29.646 26.933 ;
     RECT  0.144 26.669 27.918 26.941 ;
     RECT  0.144 26.941 27.954 27.245 ;
     RECT  29.592 26.933 29.646 27.329 ;
     RECT  0.324 27.245 27.954 27.365 ;
     RECT  1.728 27.365 27.738 27.599 ;
     RECT  29.592 27.329 29.61 27.599 ;
     RECT  1.98 27.599 27.738 27.977 ;
     RECT  0.324 27.365 0.558 28.027 ;
     RECT  2.196 27.977 27.738 28.291 ;
     RECT  2.196 28.291 27.954 28.409 ;
     RECT  0.144 28.027 0.558 28.651 ;
     RECT  2.196 28.409 27.882 28.715 ;
     RECT  0.144 28.651 0.63 28.747 ;
     RECT  2.304 28.715 27.882 28.949 ;
     RECT  0.108 28.747 0.63 29.489 ;
     RECT  0.144 29.489 0.63 29.714 ;
     RECT  0.18 29.714 0.63 29.837 ;
     RECT  2.304 28.949 27.63 29.911 ;
     RECT  2.304 29.911 27.954 30.029 ;
     RECT  2.304 30.029 27.63 30.187 ;
     RECT  2.268 30.187 27.63 30.307 ;
     RECT  0.216 29.837 0.63 30.331 ;
     RECT  2.232 30.307 27.63 30.413 ;
     RECT  0.216 30.331 1.242 30.461 ;
     RECT  0.216 30.461 1.17 30.649 ;
     RECT  0.108 30.649 1.17 30.653 ;
     RECT  2.304 30.413 27.63 31.339 ;
     RECT  0.108 30.653 0.63 32.011 ;
     RECT  0.108 32.011 0.666 32.141 ;
     RECT  2.268 31.339 27.63 32.203 ;
     RECT  2.232 32.203 27.63 32.341 ;
     RECT  2.232 32.341 27.666 32.567 ;
     RECT  0.108 32.141 0.522 32.603 ;
     RECT  0.504 32.603 0.522 32.909 ;
     RECT  1.296 32.299 1.314 33.107 ;
     RECT  2.304 32.567 27.666 33.691 ;
     RECT  2.304 33.691 27.954 33.809 ;
     RECT  2.304 33.809 27.63 33.881 ;
     RECT  0.108 33.925 0.126 34.027 ;
     RECT  1.152 33.979 1.17 34.109 ;
     RECT  0.108 34.027 0.342 34.157 ;
     RECT  2.304 33.881 27.414 34.465 ;
     RECT  0.108 34.157 0.162 34.637 ;
     RECT  2.268 34.465 27.414 34.771 ;
     RECT  2.268 34.771 27.954 34.889 ;
     RECT  0.144 34.637 0.162 35.131 ;
     RECT  0.144 35.131 0.198 35.179 ;
     RECT  2.268 34.889 27.486 35.195 ;
     RECT  1.26 35.131 1.278 35.227 ;
     RECT  0.144 35.179 0.342 35.309 ;
     RECT  1.152 35.227 1.278 35.419 ;
     RECT  2.268 35.195 27.378 35.437 ;
     RECT  2.232 35.437 27.378 35.693 ;
     RECT  0.144 35.309 0.162 35.741 ;
     RECT  1.152 35.419 1.386 35.741 ;
     RECT  1.152 35.741 1.17 35.843 ;
     RECT  2.268 35.693 27.378 36.121 ;
     RECT  2.268 36.121 27.846 36.517 ;
     RECT  0.324 36.523 0.342 36.616 ;
     RECT  0.108 36.616 0.342 36.653 ;
     RECT  2.196 36.517 27.846 36.661 ;
     RECT  2.196 36.661 27.954 36.689 ;
     RECT  0.144 36.653 0.342 36.931 ;
     RECT  1.188 36.787 1.206 36.931 ;
     RECT  2.196 36.689 22.266 36.941 ;
     RECT  0.144 36.931 1.206 36.959 ;
     RECT  2.268 36.941 22.266 37.085 ;
     RECT  0.144 36.959 1.17 37.373 ;
     RECT  0.216 37.373 1.17 37.421 ;
     RECT  0.504 37.421 1.17 37.463 ;
     RECT  23.148 36.689 27.954 37.579 ;
     RECT  0.504 37.463 0.558 37.709 ;
     RECT  2.268 37.085 22.014 37.867 ;
     RECT  22.86 37.579 27.954 37.867 ;
     RECT  0.504 37.709 0.522 37.997 ;
     RECT  2.268 37.867 27.954 38.443 ;
     RECT  1.692 38.443 27.954 38.669 ;
     RECT  1.692 38.669 27.558 38.705 ;
     RECT  22.68 38.705 27.558 38.741 ;
     RECT  0.144 38.827 0.162 39.115 ;
     RECT  0.144 39.115 0.342 39.245 ;
     RECT  22.68 38.741 27.486 39.559 ;
     RECT  1.692 38.705 21.942 39.631 ;
     RECT  22.68 39.559 27.954 39.631 ;
     RECT  0.144 39.245 0.162 40.253 ;
     RECT  0.108 40.459 0.126 40.685 ;
     RECT  1.692 39.631 27.954 40.703 ;
     RECT  2.304 40.703 27.954 41.611 ;
     RECT  0.18 41.707 0.198 41.719 ;
     RECT  2.268 41.611 27.954 41.747 ;
     RECT  0.18 41.719 0.27 41.885 ;
     RECT  0.18 41.885 0.198 41.981 ;
     RECT  2.304 41.747 27.954 42.449 ;
     RECT  2.304 42.449 27.486 42.755 ;
     RECT  1.152 42.091 1.17 42.763 ;
     RECT  2.304 42.755 27.378 42.763 ;
     RECT  1.152 42.763 27.378 42.871 ;
     RECT  0.54 42.871 27.378 42.899 ;
     RECT  0.54 42.899 27.27 43.645 ;
     RECT  0.108 43.645 27.27 43.843 ;
     RECT  0.108 43.843 27.342 43.943 ;
     RECT  1.728 43.943 27.342 44.041 ;
     RECT  1.728 44.041 27.594 44.105 ;
     RECT  0.108 43.943 0.594 44.447 ;
     RECT  2.268 44.105 27.594 44.491 ;
     RECT  2.268 44.491 27.666 44.915 ;
     RECT  2.268 44.915 27.342 45.451 ;
     RECT  0.144 44.447 0.594 45.869 ;
     RECT  2.232 45.451 27.342 45.995 ;
     RECT  0.144 45.869 0.198 46.445 ;
     RECT  2.304 45.995 27.342 46.843 ;
     RECT  2.196 46.843 27.342 47.021 ;
     RECT  0.18 46.445 0.198 47.419 ;
     RECT  0.18 47.419 0.234 47.467 ;
     RECT  0.144 47.467 0.234 47.597 ;
     RECT  0.144 47.597 0.162 47.645 ;
     RECT  2.304 47.021 27.342 47.851 ;
     RECT  2.196 47.851 27.342 47.957 ;
     RECT  2.304 47.957 27.342 48.001 ;
     RECT  0.432 48.523 0.45 48.619 ;
     RECT  0.36 48.619 0.45 48.701 ;
     RECT  0.36 48.701 0.378 48.715 ;
     RECT  0.144 48.715 0.378 48.749 ;
     RECT  2.304 48.001 27.414 48.901 ;
     RECT  0.144 48.749 0.342 48.989 ;
     RECT  2.304 48.901 27.45 49.549 ;
     RECT  2.304 49.549 27.558 49.675 ;
     RECT  2.268 49.675 27.558 50.152 ;
     RECT  2.232 50.152 27.558 50.431 ;
     RECT  0.18 48.989 0.342 50.443 ;
     RECT  2.232 50.431 27.594 50.585 ;
     RECT  2.268 50.585 27.594 50.701 ;
     RECT  2.268 50.701 27.738 50.863 ;
     RECT  2.268 50.863 27.81 50.935 ;
     RECT  0.144 50.443 0.342 51.245 ;
     RECT  0.144 51.245 0.162 51.677 ;
     RECT  2.268 50.935 28.026 51.691 ;
     RECT  0.324 52.267 0.342 52.397 ;
     RECT  2.196 51.691 28.026 52.619 ;
     RECT  2.196 52.619 9.522 52.853 ;
     RECT  10.44 52.619 28.026 52.861 ;
     RECT  10.44 52.861 28.134 53.069 ;
     RECT  0.108 53.131 0.126 53.176 ;
     RECT  0.108 53.176 0.234 53.204 ;
     RECT  0.144 53.204 0.234 53.309 ;
     RECT  10.515 53.069 28.134 53.357 ;
     RECT  2.196 52.853 9.486 53.393 ;
     RECT  1.152 51.787 1.17 53.419 ;
     RECT  2.196 53.393 8.91 53.419 ;
     RECT  11.808 53.357 28.134 53.519 ;
     RECT  11.808 53.519 11.826 53.555 ;
     RECT  0.144 53.309 0.162 53.597 ;
     RECT  1.152 53.419 8.91 53.897 ;
     RECT  12.6 53.519 28.134 54.095 ;
     RECT  1.728 53.897 8.91 54.473 ;
     RECT  1.764 54.473 8.91 54.509 ;
     RECT  2.34 54.509 8.91 54.779 ;
     RECT  2.415 54.779 8.91 55.139 ;
     RECT  2.415 55.139 8.73 55.247 ;
     RECT  12.132 55.243 12.15 55.255 ;
     RECT  12.888 54.095 28.134 55.255 ;
     RECT  12.132 55.255 28.134 55.283 ;
     RECT  2.415 55.247 8.55 55.525 ;
     RECT  2.412 55.525 8.55 55.627 ;
     RECT  0.54 55.795 0.558 55.949 ;
     RECT  2.304 55.627 8.55 55.949 ;
     RECT  12.276 55.283 28.134 56.101 ;
     RECT  12.276 56.101 28.17 56.219 ;
     RECT  12.816 56.219 28.17 56.327 ;
     RECT  0.324 56.203 0.342 56.333 ;
     RECT  11.916 56.299 11.934 56.363 ;
     RECT  2.304 55.949 8.19 56.489 ;
     RECT  12.852 56.327 28.17 56.489 ;
     RECT  2.304 56.489 8.097 56.597 ;
     RECT  4.356 56.597 8.097 56.759 ;
     RECT  2.304 56.597 3.618 56.795 ;
     RECT  4.356 56.759 6.822 56.795 ;
     RECT  12.888 56.489 28.17 56.903 ;
     RECT  2.415 56.795 3.618 57.029 ;
     RECT  4.5 56.795 6.822 57.029 ;
     RECT  13.068 56.903 28.17 57.029 ;
     RECT  4.5 57.029 6.21 57.209 ;
     RECT  2.415 57.029 3.186 57.299 ;
     RECT  6.192 57.209 6.21 57.299 ;
     RECT  2.415 57.299 2.862 57.335 ;
     RECT  4.5 57.209 5.397 57.335 ;
     RECT  13.104 57.029 28.17 57.875 ;
     RECT  13.14 57.875 28.17 57.917 ;
     RECT  13.14 57.917 27.954 58.019 ;
     RECT  2.415 57.335 2.697 58.067 ;
     RECT  5.115 57.335 5.397 58.067 ;
     RECT  7.815 56.759 8.097 58.067 ;
     RECT  10.515 53.357 10.797 58.067 ;
     RECT  13.14 58.019 27.918 58.109 ;
     RECT  13.215 58.109 24.105 58.145 ;
     RECT  24.912 58.109 27.846 58.145 ;
     RECT  23.976 58.145 24.105 58.157 ;
     RECT  24.912 58.145 27.666 58.157 ;
     RECT  13.215 58.145 19.314 58.205 ;
     RECT  18.615 58.205 19.314 58.217 ;
     RECT  20.052 58.145 23.022 58.253 ;
     RECT  18.615 58.217 19.062 58.289 ;
     RECT  24.912 58.157 27.63 58.289 ;
     RECT  2.415 58.067 2.505 58.337 ;
     RECT  5.115 58.067 5.205 58.337 ;
     RECT  7.815 58.067 7.905 58.337 ;
     RECT  10.515 58.067 10.605 58.337 ;
     RECT  13.215 58.205 17.874 58.337 ;
     RECT  18.615 58.289 18.705 58.337 ;
     RECT  24.015 58.157 24.105 58.337 ;
     RECT  13.788 58.337 17.874 58.397 ;
     RECT  13.788 58.397 16.506 58.445 ;
     RECT  17.64 58.397 17.874 58.445 ;
     RECT  24.912 58.289 27.342 58.451 ;
     RECT  17.64 58.445 17.658 58.685 ;
     RECT  13.788 58.445 16.326 59.261 ;
     RECT  14.436 59.261 15.462 59.885 ;
     RECT  20.052 58.253 22.734 59.885 ;
     RECT  16.308 59.261 16.326 60.139 ;
     RECT  14.904 59.885 15.462 60.365 ;
     RECT  16.308 60.139 16.47 60.365 ;
     RECT  20.484 59.885 22.734 60.443 ;
     RECT  20.502 60.443 20.556 60.461 ;
     RECT  20.574 60.443 20.628 60.461 ;
     RECT  20.646 60.443 20.7 60.461 ;
     RECT  20.718 60.443 20.772 60.461 ;
     RECT  20.79 60.443 20.844 60.461 ;
     RECT  20.862 60.443 20.916 60.461 ;
     RECT  20.934 60.443 20.988 60.461 ;
     RECT  21.006 60.443 21.06 60.461 ;
     RECT  21.078 60.443 21.132 60.461 ;
     RECT  21.15 60.443 21.204 60.461 ;
     RECT  21.222 60.443 21.276 60.461 ;
     RECT  21.294 60.443 21.348 60.461 ;
     RECT  21.366 60.443 21.42 60.461 ;
     RECT  21.438 60.443 21.492 60.461 ;
     RECT  21.51 60.443 21.564 60.461 ;
     RECT  21.582 60.443 21.636 60.461 ;
     RECT  21.654 60.443 21.708 60.461 ;
     RECT  21.726 60.443 21.78 60.461 ;
     RECT  21.798 60.443 21.852 60.461 ;
     RECT  21.87 60.443 21.924 60.461 ;
     RECT  21.942 60.443 21.996 60.461 ;
     RECT  22.014 60.443 22.068 60.461 ;
     RECT  22.086 60.443 22.14 60.461 ;
     RECT  22.158 60.443 22.212 60.461 ;
     RECT  22.23 60.443 22.284 60.461 ;
     RECT  22.302 60.443 22.356 60.461 ;
     RECT  22.374 60.443 22.428 60.461 ;
     RECT  22.446 60.443 22.5 60.461 ;
     RECT  22.518 60.443 22.572 60.461 ;
     RECT  22.59 60.443 22.644 60.461 ;
     RECT  22.662 60.443 22.716 60.461 ;
     RECT  25.308 58.451 27.342 60.443 ;
     RECT  25.326 60.443 25.38 60.461 ;
     RECT  25.398 60.443 25.452 60.461 ;
     RECT  25.47 60.443 25.524 60.461 ;
     RECT  25.542 60.443 25.596 60.461 ;
     RECT  25.614 60.443 25.668 60.461 ;
     RECT  25.686 60.443 25.74 60.461 ;
     RECT  25.758 60.443 25.812 60.461 ;
     RECT  25.83 60.443 25.884 60.461 ;
     RECT  25.902 60.443 25.956 60.461 ;
     RECT  25.974 60.443 26.028 60.461 ;
     RECT  26.046 60.443 26.1 60.461 ;
     RECT  26.118 60.443 26.172 60.461 ;
     RECT  26.19 60.443 26.244 60.461 ;
     RECT  26.262 60.443 26.316 60.461 ;
     RECT  26.334 60.443 26.388 60.461 ;
     RECT  26.406 60.443 26.46 60.461 ;
     RECT  26.478 60.443 26.532 60.461 ;
     RECT  26.55 60.443 26.604 60.461 ;
     RECT  26.622 60.443 26.676 60.461 ;
     RECT  26.694 60.443 26.748 60.461 ;
     RECT  26.766 60.443 26.82 60.461 ;
     RECT  26.838 60.443 26.892 60.461 ;
     RECT  26.91 60.443 26.964 60.461 ;
     RECT  26.982 60.443 27.036 60.461 ;
     RECT  27.054 60.443 27.108 60.461 ;
     RECT  27.126 60.443 27.18 60.461 ;
     RECT  27.198 60.443 27.252 60.461 ;
     RECT  27.27 60.443 27.324 60.461 ;
    LAYER M4 ;
     RECT  0.084 2.928 0.133 2.952 ;
     RECT  0.06 2.952 0.133 3.024 ;
     RECT  0.084 3.024 0.133 3.048 ;
     RECT  0.06 3.048 0.133 3.12 ;
     RECT  0.084 3.12 0.133 3.144 ;
     RECT  0.06 3.144 0.133 3.216 ;
     RECT  0.084 3.216 0.133 3.24 ;
     RECT  0.06 3.24 0.133 3.312 ;
     RECT  0.084 3.312 0.133 3.336 ;
     RECT  0.06 3.336 0.133 3.408 ;
     RECT  0.084 3.408 0.133 3.432 ;
     RECT  0.06 3.432 0.133 3.504 ;
     RECT  0.084 3.504 0.133 3.528 ;
     RECT  0.06 3.528 0.133 3.6 ;
     RECT  0.084 3.6 0.133 3.624 ;
     RECT  0.06 3.624 0.133 3.696 ;
     RECT  0.084 3.696 0.133 3.72 ;
     RECT  0.06 3.72 0.133 3.792 ;
     RECT  0.084 3.792 0.133 3.816 ;
     RECT  0.06 3.816 0.133 3.888 ;
     RECT  0.084 3.888 0.133 3.912 ;
     RECT  0.06 3.912 0.133 3.984 ;
     RECT  0.084 3.984 0.133 4.008 ;
     RECT  0.06 4.008 0.133 4.08 ;
     RECT  0.084 4.08 0.133 4.104 ;
     RECT  0.06 4.104 0.133 4.176 ;
     RECT  0.084 4.176 0.133 4.2 ;
     RECT  0.06 4.2 0.133 4.272 ;
     RECT  0.084 4.272 0.133 4.296 ;
     RECT  0.06 4.296 0.133 4.368 ;
     RECT  0.084 4.368 0.133 4.392 ;
     RECT  0.06 4.392 0.133 4.464 ;
     RECT  0.084 4.464 0.133 4.488 ;
     RECT  0.06 4.488 0.133 4.56 ;
     RECT  0.084 4.56 0.133 4.584 ;
     RECT  0.06 4.584 0.133 4.656 ;
     RECT  0.084 4.656 0.133 4.68 ;
     RECT  0.06 4.68 0.133 4.752 ;
     RECT  0.084 4.752 0.133 4.776 ;
     RECT  0.06 4.776 0.133 4.848 ;
     RECT  0.084 4.848 0.133 4.872 ;
     RECT  0.06 4.872 0.133 4.944 ;
     RECT  0.084 4.944 0.133 4.968 ;
     RECT  0.06 4.968 0.133 5.04 ;
     RECT  0.084 5.04 0.133 5.064 ;
     RECT  0.06 5.064 0.133 5.136 ;
     RECT  0.084 5.136 0.133 5.16 ;
     RECT  0.06 5.16 0.133 5.232 ;
     RECT  0.084 5.232 0.133 5.256 ;
     RECT  0.06 5.256 0.133 5.328 ;
     RECT  0.084 5.328 0.133 5.352 ;
     RECT  0.06 5.352 0.133 5.424 ;
     RECT  0.084 5.424 0.133 5.448 ;
     RECT  0.06 5.448 0.133 5.52 ;
     RECT  0.084 5.52 0.133 5.544 ;
     RECT  0.06 5.544 0.133 5.616 ;
     RECT  0.084 5.616 0.133 5.64 ;
     RECT  0.06 5.64 0.133 5.712 ;
     RECT  0.084 5.712 0.133 5.736 ;
     RECT  0.06 5.736 0.133 5.808 ;
     RECT  0.084 5.808 0.133 5.832 ;
     RECT  0.06 5.832 0.133 5.904 ;
     RECT  0.084 5.904 0.133 5.928 ;
     RECT  0.06 5.928 0.133 6 ;
     RECT  0.084 6 0.133 6.024 ;
     RECT  0.06 6.024 0.133 6.096 ;
     RECT  0.084 6.096 0.133 6.12 ;
     RECT  0.06 6.12 0.133 6.192 ;
     RECT  0.084 6.192 0.133 6.216 ;
     RECT  0.06 6.216 0.133 6.288 ;
     RECT  0.084 6.288 0.133 6.312 ;
     RECT  0.06 6.312 0.133 6.384 ;
     RECT  0.084 6.384 0.133 6.408 ;
     RECT  0.06 6.408 0.133 6.48 ;
     RECT  0.084 6.48 0.133 6.504 ;
     RECT  0.06 6.504 0.133 6.576 ;
     RECT  0.084 6.576 0.133 6.6 ;
     RECT  0.06 6.6 0.133 6.672 ;
     RECT  0.084 6.672 0.133 6.696 ;
     RECT  0.06 6.696 0.133 6.768 ;
     RECT  0.084 6.768 0.133 6.792 ;
     RECT  0.06 6.792 0.133 6.864 ;
     RECT  0.084 6.864 0.133 6.888 ;
     RECT  0.06 6.888 0.133 6.96 ;
     RECT  0.084 6.96 0.133 6.984 ;
     RECT  0.06 6.984 0.133 7.056 ;
     RECT  0.084 7.056 0.133 7.08 ;
     RECT  0.06 7.08 0.133 7.152 ;
     RECT  0.084 7.152 0.133 7.176 ;
     RECT  0.06 7.176 0.133 7.248 ;
     RECT  0.084 7.248 0.133 7.272 ;
     RECT  0.06 7.272 0.133 7.344 ;
     RECT  0.084 7.344 0.133 7.368 ;
     RECT  0.06 7.368 0.133 7.44 ;
     RECT  0.084 7.44 0.133 7.464 ;
     RECT  0.06 7.464 0.133 7.536 ;
     RECT  0.084 7.536 0.133 7.56 ;
     RECT  0.06 7.56 0.133 7.632 ;
     RECT  0.084 7.632 0.133 7.656 ;
     RECT  0.06 7.656 0.133 7.728 ;
     RECT  0.084 7.728 0.133 7.752 ;
     RECT  0.06 7.752 0.133 7.824 ;
     RECT  0.084 7.824 0.133 7.848 ;
     RECT  0.06 7.848 0.133 7.92 ;
     RECT  0.084 7.92 0.133 7.944 ;
     RECT  0.06 7.944 0.133 8.016 ;
     RECT  0.084 8.016 0.133 8.04 ;
     RECT  0.06 8.04 0.133 8.112 ;
     RECT  0.084 8.112 0.133 8.136 ;
     RECT  0.06 8.136 0.133 8.208 ;
     RECT  0.084 8.208 0.133 8.232 ;
     RECT  0.06 8.232 0.133 8.304 ;
     RECT  0.084 8.304 0.133 8.328 ;
     RECT  0.06 8.328 0.133 8.4 ;
     RECT  0.084 8.4 0.133 8.424 ;
     RECT  0.06 8.424 0.133 8.496 ;
     RECT  0.084 8.496 0.133 8.52 ;
     RECT  0.06 8.52 0.133 8.592 ;
     RECT  0.084 8.592 0.133 8.616 ;
     RECT  0.06 8.616 0.133 8.688 ;
     RECT  0.084 8.688 0.133 8.712 ;
     RECT  0.06 8.712 0.133 8.784 ;
     RECT  0.084 8.784 0.133 8.808 ;
     RECT  0.06 8.808 0.133 8.88 ;
     RECT  0.084 8.88 0.133 8.904 ;
     RECT  0.06 8.904 0.133 8.976 ;
     RECT  0.084 8.976 0.133 9 ;
     RECT  0.06 9 0.133 9.072 ;
     RECT  0.084 9.072 0.133 9.096 ;
     RECT  0.06 9.096 0.133 9.168 ;
     RECT  0.084 9.168 0.133 9.192 ;
     RECT  0.06 9.192 0.133 9.264 ;
     RECT  0.084 9.264 0.133 9.288 ;
     RECT  0.06 9.288 0.133 9.36 ;
     RECT  0.084 9.36 0.133 9.384 ;
     RECT  0.06 9.384 0.133 9.456 ;
     RECT  0.084 9.456 0.133 9.48 ;
     RECT  0.06 9.48 0.133 9.552 ;
     RECT  0.084 9.552 0.133 9.576 ;
     RECT  0.06 9.576 0.133 9.648 ;
     RECT  0.084 9.648 0.133 9.672 ;
     RECT  0.06 9.672 0.133 9.744 ;
     RECT  0.084 9.744 0.133 9.768 ;
     RECT  0.06 9.768 0.133 9.84 ;
     RECT  0.084 9.84 0.133 9.864 ;
     RECT  0.06 9.864 0.133 9.936 ;
     RECT  0.084 9.936 0.133 9.96 ;
     RECT  0.06 9.96 0.133 10.032 ;
     RECT  0.084 10.032 0.133 10.056 ;
     RECT  0.06 10.056 0.133 10.128 ;
     RECT  0.084 10.128 0.133 10.152 ;
     RECT  0.06 10.152 0.133 10.224 ;
     RECT  0.084 10.224 0.133 10.248 ;
     RECT  0.06 10.248 0.133 10.32 ;
     RECT  0.084 10.32 0.133 10.344 ;
     RECT  0.06 10.344 0.133 10.416 ;
     RECT  0.084 10.416 0.133 10.44 ;
     RECT  0.06 10.44 0.133 10.512 ;
     RECT  0.084 10.512 0.133 10.536 ;
     RECT  0.06 10.536 0.133 10.608 ;
     RECT  0.084 10.608 0.133 10.632 ;
     RECT  0.06 10.632 0.133 10.704 ;
     RECT  0.084 10.704 0.133 10.728 ;
     RECT  0.06 10.728 0.133 10.8 ;
     RECT  0.084 10.8 0.133 10.824 ;
     RECT  0.06 10.824 0.133 10.896 ;
     RECT  0.084 10.896 0.133 10.92 ;
     RECT  0.06 10.92 0.133 10.992 ;
     RECT  0.084 10.992 0.133 11.016 ;
     RECT  0.06 11.016 0.133 11.088 ;
     RECT  0.084 11.088 0.133 11.112 ;
     RECT  0.06 11.112 0.133 11.184 ;
     RECT  0.084 11.184 0.133 11.208 ;
     RECT  0.06 11.208 0.133 11.28 ;
     RECT  0.084 11.28 0.133 11.304 ;
     RECT  0.06 11.304 0.133 11.376 ;
     RECT  0.084 11.376 0.133 11.4 ;
     RECT  0.06 11.4 0.133 11.472 ;
     RECT  0.084 11.472 0.133 11.496 ;
     RECT  0.06 11.496 0.133 11.568 ;
     RECT  0.084 11.568 0.133 11.592 ;
     RECT  0.06 11.592 0.133 11.664 ;
     RECT  0.084 11.664 0.133 11.688 ;
     RECT  0.06 11.688 0.133 11.76 ;
     RECT  0.084 11.76 0.133 11.784 ;
     RECT  0.06 11.784 0.133 11.856 ;
     RECT  0.084 11.856 0.133 11.88 ;
     RECT  0.06 11.88 0.133 11.952 ;
     RECT  0.084 11.952 0.133 11.976 ;
     RECT  0.06 11.976 0.133 12.048 ;
     RECT  0.084 12.048 0.133 12.072 ;
     RECT  0.06 12.072 0.133 12.144 ;
     RECT  0.084 12.144 0.133 12.168 ;
     RECT  0.06 12.168 0.133 12.24 ;
     RECT  0.084 12.24 0.133 12.264 ;
     RECT  0.06 12.264 0.133 12.336 ;
     RECT  0.084 12.336 0.133 12.36 ;
     RECT  0.06 12.36 0.133 12.432 ;
     RECT  0.084 12.432 0.133 12.456 ;
     RECT  0.06 12.456 0.133 12.528 ;
     RECT  0.084 12.528 0.133 12.552 ;
     RECT  0.06 12.552 0.133 12.624 ;
     RECT  0.084 12.624 0.133 12.648 ;
     RECT  0.06 12.648 0.133 12.72 ;
     RECT  0.084 12.72 0.133 12.744 ;
     RECT  0.06 12.744 0.133 12.816 ;
     RECT  0.084 12.816 0.133 12.84 ;
     RECT  0.06 12.84 0.133 12.912 ;
     RECT  0.084 12.912 0.133 12.936 ;
     RECT  0.06 12.936 0.133 13.008 ;
     RECT  0.084 13.008 0.133 13.032 ;
     RECT  0.06 13.032 0.133 13.104 ;
     RECT  0.084 13.104 0.133 13.128 ;
     RECT  0.06 13.128 0.133 13.2 ;
     RECT  0.084 13.2 0.133 13.224 ;
     RECT  0.06 13.224 0.133 13.296 ;
     RECT  0.084 13.296 0.133 13.32 ;
     RECT  0.06 13.32 0.133 13.392 ;
     RECT  0.084 13.392 0.133 13.416 ;
     RECT  0.06 13.416 0.133 13.488 ;
     RECT  0.084 13.488 0.133 13.512 ;
     RECT  0.06 13.512 0.133 13.584 ;
     RECT  0.084 13.584 0.133 13.608 ;
     RECT  0.06 13.608 0.133 13.68 ;
     RECT  0.084 13.68 0.133 13.704 ;
     RECT  0.06 13.704 0.133 13.776 ;
     RECT  0.084 13.776 0.133 13.8 ;
     RECT  0.06 13.8 0.133 13.872 ;
     RECT  0.084 13.872 0.133 13.896 ;
     RECT  0.06 13.896 0.133 13.968 ;
     RECT  0.084 13.968 0.133 13.992 ;
     RECT  0.06 13.992 0.133 14.064 ;
     RECT  0.084 14.064 0.133 14.088 ;
     RECT  0.06 14.088 0.133 14.16 ;
     RECT  0.084 14.16 0.133 14.184 ;
     RECT  0.06 14.184 0.133 14.256 ;
     RECT  0.084 14.256 0.133 14.28 ;
     RECT  0.06 14.28 0.133 14.352 ;
     RECT  0.084 14.352 0.133 14.376 ;
     RECT  0.06 14.376 0.133 14.448 ;
     RECT  0.084 14.448 0.133 14.472 ;
     RECT  0.06 14.472 0.133 14.544 ;
     RECT  0.084 14.544 0.133 14.568 ;
     RECT  0.06 14.568 0.133 14.64 ;
     RECT  0.084 14.64 0.133 14.664 ;
     RECT  0.06 14.664 0.133 14.736 ;
     RECT  0.084 14.736 0.133 14.76 ;
     RECT  0.06 14.76 0.133 14.832 ;
     RECT  0.084 14.832 0.133 14.856 ;
     RECT  0.06 14.856 0.133 14.928 ;
     RECT  0.084 14.928 0.133 14.952 ;
     RECT  0.06 14.952 0.133 15.024 ;
     RECT  0.084 15.024 0.133 15.048 ;
     RECT  0.06 15.048 0.133 15.12 ;
     RECT  0.084 15.12 0.133 15.144 ;
     RECT  0.06 15.144 0.133 15.216 ;
     RECT  0.084 15.216 0.133 15.24 ;
     RECT  0.06 15.24 0.133 15.312 ;
     RECT  0.084 15.312 0.133 15.336 ;
     RECT  0.06 15.336 0.133 15.408 ;
     RECT  0.084 15.408 0.133 15.432 ;
     RECT  0.06 15.432 0.133 15.504 ;
     RECT  0.084 15.504 0.133 15.528 ;
     RECT  0.06 15.528 0.133 15.6 ;
     RECT  0.084 15.6 0.133 15.624 ;
     RECT  0.06 15.624 0.133 15.696 ;
     RECT  0.084 15.696 0.133 15.72 ;
     RECT  0.06 15.72 0.133 15.792 ;
     RECT  0.084 15.792 0.133 15.816 ;
     RECT  0.06 15.816 0.133 15.888 ;
     RECT  0.084 15.888 0.133 15.912 ;
     RECT  0.06 15.912 0.133 15.984 ;
     RECT  0.084 15.984 0.133 16.008 ;
     RECT  0.06 16.008 0.133 16.08 ;
     RECT  0.084 16.08 0.133 16.104 ;
     RECT  0.06 16.104 0.133 16.176 ;
     RECT  0.084 16.176 0.133 16.2 ;
     RECT  0.06 16.2 0.133 16.272 ;
     RECT  0.084 16.272 0.133 16.296 ;
     RECT  0.06 16.296 0.133 16.368 ;
     RECT  0.084 16.368 0.133 16.392 ;
     RECT  0.06 16.392 0.133 16.464 ;
     RECT  0.084 16.464 0.133 16.488 ;
     RECT  0.06 16.488 0.133 16.56 ;
     RECT  0.084 16.56 0.133 16.584 ;
     RECT  0.06 16.584 0.133 16.656 ;
     RECT  0.084 16.656 0.133 16.68 ;
     RECT  0.06 16.68 0.133 16.752 ;
     RECT  0.084 16.752 0.133 16.776 ;
     RECT  0.06 16.776 0.133 16.848 ;
     RECT  0.084 16.848 0.133 16.872 ;
     RECT  0.06 16.872 0.133 16.944 ;
     RECT  0.084 16.944 0.133 16.968 ;
     RECT  0.06 16.968 0.133 17.04 ;
     RECT  0.084 17.04 0.133 17.064 ;
     RECT  0.06 17.064 0.133 17.136 ;
     RECT  0.084 17.136 0.133 17.16 ;
     RECT  0.06 17.16 0.133 17.232 ;
     RECT  0.084 17.232 0.133 17.256 ;
     RECT  0.06 17.256 0.133 17.328 ;
     RECT  0.084 17.328 0.133 17.352 ;
     RECT  0.06 17.352 0.133 17.424 ;
     RECT  0.084 17.424 0.133 17.448 ;
     RECT  0.06 17.448 0.133 17.52 ;
     RECT  0.084 17.52 0.133 17.544 ;
     RECT  0.06 17.544 0.133 17.616 ;
     RECT  0.084 17.616 0.133 17.64 ;
     RECT  0.06 17.64 0.133 17.712 ;
     RECT  0.084 17.712 0.133 17.736 ;
     RECT  0.06 17.736 0.133 17.808 ;
     RECT  0.084 17.808 0.133 17.832 ;
     RECT  0.06 17.832 0.133 17.904 ;
     RECT  0.084 17.904 0.133 17.928 ;
     RECT  0.06 17.928 0.133 18 ;
     RECT  0.084 18 0.133 18.024 ;
     RECT  0.06 18.024 0.133 18.096 ;
     RECT  0.084 18.096 0.133 18.12 ;
     RECT  0.06 18.12 0.133 18.192 ;
     RECT  0.084 18.192 0.133 18.216 ;
     RECT  0.06 18.216 0.133 18.288 ;
     RECT  0.084 18.288 0.133 18.312 ;
     RECT  0.06 18.312 0.133 18.384 ;
     RECT  0.084 18.384 0.133 18.408 ;
     RECT  0.06 18.408 0.133 18.48 ;
     RECT  0.084 18.48 0.133 18.504 ;
     RECT  0.06 18.504 0.133 18.576 ;
     RECT  0.084 18.576 0.133 18.6 ;
     RECT  0.06 18.6 0.133 18.672 ;
     RECT  0.084 18.672 0.133 18.696 ;
     RECT  0.06 18.696 0.133 18.768 ;
     RECT  0.084 18.768 0.133 18.792 ;
     RECT  0.06 18.792 0.133 18.864 ;
     RECT  0.084 18.864 0.133 18.888 ;
     RECT  0.06 18.888 0.133 18.96 ;
     RECT  0.084 18.96 0.133 18.984 ;
     RECT  0.06 18.984 0.133 19.056 ;
     RECT  0.084 19.056 0.133 19.08 ;
     RECT  0.06 19.08 0.133 19.152 ;
     RECT  0.084 19.152 0.133 19.176 ;
     RECT  0.06 19.176 0.133 19.248 ;
     RECT  0.084 19.248 0.133 19.272 ;
     RECT  0.06 19.272 0.133 19.344 ;
     RECT  0.084 19.344 0.133 19.368 ;
     RECT  0.06 19.368 0.133 19.44 ;
     RECT  0.084 19.44 0.133 19.464 ;
     RECT  0.06 19.464 0.133 19.536 ;
     RECT  0.084 19.536 0.133 19.56 ;
     RECT  0.06 19.56 0.133 19.632 ;
     RECT  0.084 19.632 0.133 19.656 ;
     RECT  0.06 19.656 0.133 19.728 ;
     RECT  0.084 19.728 0.133 19.752 ;
     RECT  0.06 19.752 0.133 19.824 ;
     RECT  0.084 19.824 0.133 19.848 ;
     RECT  0.06 19.848 0.133 19.92 ;
     RECT  0.084 19.92 0.133 19.944 ;
     RECT  0.06 19.944 0.133 20.016 ;
     RECT  0.084 20.016 0.133 20.04 ;
     RECT  0.06 20.04 0.133 20.112 ;
     RECT  0.084 20.112 0.133 20.136 ;
     RECT  0.06 20.136 0.133 20.208 ;
     RECT  0.084 20.208 0.133 20.232 ;
     RECT  0.06 20.232 0.133 20.304 ;
     RECT  0.084 20.304 0.133 20.328 ;
     RECT  0.06 20.328 0.133 20.4 ;
     RECT  0.084 20.4 0.133 20.424 ;
     RECT  0.06 20.424 0.133 20.496 ;
     RECT  0.084 20.496 0.133 20.52 ;
     RECT  0.06 20.52 0.133 20.592 ;
     RECT  0.084 20.592 0.133 20.616 ;
     RECT  0.06 20.616 0.133 20.688 ;
     RECT  0.084 20.688 0.133 20.712 ;
     RECT  0.06 20.712 0.133 20.784 ;
     RECT  0.084 20.784 0.133 20.808 ;
     RECT  0.06 20.808 0.133 20.88 ;
     RECT  0.084 20.88 0.133 20.904 ;
     RECT  0.06 20.904 0.133 20.976 ;
     RECT  0.084 20.976 0.133 21 ;
     RECT  0.06 21 0.133 21.072 ;
     RECT  0.084 21.072 0.133 21.096 ;
     RECT  0.06 21.096 0.133 21.168 ;
     RECT  0.084 21.168 0.133 21.192 ;
     RECT  0.06 21.192 0.133 21.264 ;
     RECT  0.084 21.264 0.133 21.288 ;
     RECT  0.06 21.288 0.133 22.128 ;
     RECT  0.084 22.128 0.133 22.152 ;
     RECT  0.06 22.152 0.133 22.224 ;
     RECT  0.084 22.224 0.133 22.248 ;
     RECT  0.06 22.248 0.133 22.32 ;
     RECT  0.084 22.32 0.133 22.344 ;
     RECT  0.06 22.344 0.133 22.416 ;
     RECT  0.084 22.416 0.133 22.44 ;
     RECT  0.06 22.44 0.133 22.512 ;
     RECT  0.084 22.512 0.133 22.536 ;
     RECT  0.06 22.536 0.133 22.608 ;
     RECT  0.084 22.608 0.133 22.632 ;
     RECT  0.06 22.632 0.133 22.704 ;
     RECT  0.084 22.704 0.133 22.728 ;
     RECT  0.06 22.728 0.133 22.8 ;
     RECT  0.084 22.8 0.133 22.824 ;
     RECT  0.06 22.824 0.133 22.896 ;
     RECT  0.084 22.896 0.133 22.92 ;
     RECT  0.06 22.92 0.133 22.992 ;
     RECT  0.084 22.992 0.133 23.016 ;
     RECT  0.06 23.016 0.133 23.088 ;
     RECT  0.084 23.088 0.133 23.112 ;
     RECT  0.06 23.112 0.133 23.184 ;
     RECT  0.084 23.184 0.133 23.208 ;
     RECT  0.06 23.208 0.133 23.28 ;
     RECT  0.084 23.28 0.133 23.304 ;
     RECT  0.06 23.304 0.133 23.376 ;
     RECT  0.084 23.376 0.133 23.4 ;
     RECT  0.06 23.4 0.133 23.472 ;
     RECT  0.084 23.472 0.133 23.496 ;
     RECT  0.06 23.496 0.133 23.568 ;
     RECT  0.084 23.568 0.133 23.592 ;
     RECT  0.06 23.592 0.133 23.664 ;
     RECT  0.084 23.664 0.133 23.688 ;
     RECT  0.06 23.688 0.133 23.76 ;
     RECT  0.084 23.76 0.133 23.784 ;
     RECT  0.06 23.784 0.133 23.856 ;
     RECT  0.084 23.856 0.133 23.88 ;
     RECT  0.06 23.88 0.133 23.952 ;
     RECT  0.084 23.952 0.133 23.976 ;
     RECT  0.06 23.976 0.133 24.048 ;
     RECT  0.084 24.048 0.133 24.072 ;
     RECT  0.06 24.072 0.133 24.144 ;
     RECT  0.084 24.144 0.133 24.168 ;
     RECT  0.06 24.168 0.133 24.24 ;
     RECT  0.084 24.24 0.133 24.264 ;
     RECT  0.06 24.264 0.133 24.336 ;
     RECT  0.084 24.336 0.133 24.36 ;
     RECT  0.06 24.36 0.133 24.432 ;
     RECT  0.084 24.432 0.133 24.456 ;
     RECT  0.06 24.456 0.133 24.528 ;
     RECT  0.084 24.528 0.133 24.552 ;
     RECT  0.06 24.552 0.133 24.624 ;
     RECT  0.084 24.624 0.133 24.648 ;
     RECT  0.06 24.648 0.133 24.72 ;
     RECT  0.084 24.72 0.133 24.744 ;
     RECT  0.06 24.744 0.133 24.816 ;
     RECT  0.084 24.816 0.133 24.84 ;
     RECT  0.06 24.84 0.133 24.912 ;
     RECT  0.084 24.912 0.133 24.936 ;
     RECT  0.06 24.936 0.133 25.008 ;
     RECT  0.084 25.008 0.133 25.032 ;
     RECT  0.06 25.032 0.133 25.104 ;
     RECT  0.084 25.104 0.133 25.128 ;
     RECT  0.06 25.128 0.133 25.2 ;
     RECT  0.084 25.2 0.133 25.224 ;
     RECT  0.06 25.224 0.133 25.296 ;
     RECT  0.084 25.296 0.133 25.32 ;
     RECT  0.06 25.32 0.133 25.392 ;
     RECT  0.084 25.392 0.133 25.416 ;
     RECT  0.06 25.416 0.133 25.488 ;
     RECT  0.084 25.488 0.133 25.512 ;
     RECT  0.06 25.512 0.133 25.584 ;
     RECT  0.084 25.584 0.133 25.608 ;
     RECT  0.06 25.608 0.133 25.68 ;
     RECT  0.084 25.68 0.133 25.704 ;
     RECT  0.06 25.704 0.133 25.776 ;
     RECT  0.084 25.776 0.133 25.8 ;
     RECT  0.06 25.8 0.133 25.872 ;
     RECT  0.084 25.872 0.133 25.896 ;
     RECT  0.06 25.896 0.133 25.968 ;
     RECT  0.084 25.968 0.133 25.992 ;
     RECT  0.06 25.992 0.133 26.064 ;
     RECT  0.084 26.064 0.133 26.088 ;
     RECT  0.06 26.088 0.133 26.16 ;
     RECT  0.084 26.16 0.133 26.184 ;
     RECT  0.06 26.184 0.133 26.256 ;
     RECT  0.084 26.256 0.133 26.28 ;
     RECT  0.06 26.28 0.133 26.352 ;
     RECT  0.084 26.352 0.133 26.376 ;
     RECT  0.06 26.376 0.133 26.448 ;
     RECT  0.084 26.448 0.133 26.472 ;
     RECT  0.06 26.472 0.133 26.544 ;
     RECT  0.084 26.544 0.133 26.568 ;
     RECT  0.06 26.568 0.133 26.64 ;
     RECT  0.084 26.64 0.133 26.664 ;
     RECT  0.06 26.664 0.133 26.736 ;
     RECT  0.084 26.736 0.133 26.76 ;
     RECT  0.06 26.76 0.133 26.832 ;
     RECT  0.084 26.832 0.133 26.856 ;
     RECT  0.06 26.856 0.133 26.928 ;
     RECT  0.084 26.928 0.133 26.952 ;
     RECT  0.06 26.952 0.133 27.024 ;
     RECT  0.084 27.024 0.133 27.048 ;
     RECT  0.06 27.048 0.133 27.12 ;
     RECT  0.084 27.12 0.133 27.144 ;
     RECT  0.06 27.144 0.133 27.216 ;
     RECT  0.084 27.216 0.133 27.24 ;
     RECT  0.06 27.24 0.133 27.312 ;
     RECT  0.084 27.312 0.133 27.336 ;
     RECT  0.06 27.336 0.133 27.408 ;
     RECT  0.084 27.408 0.133 27.432 ;
     RECT  0.06 27.432 0.133 27.504 ;
     RECT  0.084 27.504 0.133 27.528 ;
     RECT  0.06 27.528 0.133 27.6 ;
     RECT  0.084 27.6 0.133 27.624 ;
     RECT  0.06 27.624 0.133 27.696 ;
     RECT  0.084 27.696 0.133 27.72 ;
     RECT  0.06 27.72 0.133 27.792 ;
     RECT  0.084 27.792 0.133 27.816 ;
     RECT  0.06 27.816 0.133 27.888 ;
     RECT  0.084 27.888 0.133 27.912 ;
     RECT  0.06 27.912 0.133 27.984 ;
     RECT  0.084 27.984 0.133 28.008 ;
     RECT  0.06 28.008 0.133 28.08 ;
     RECT  0.084 28.08 0.133 28.104 ;
     RECT  0.06 28.104 0.133 28.176 ;
     RECT  0.084 28.176 0.133 28.2 ;
     RECT  0.06 28.2 0.133 28.272 ;
     RECT  0.084 28.272 0.133 28.296 ;
     RECT  0.06 28.296 0.133 28.368 ;
     RECT  0.084 28.368 0.133 28.392 ;
     RECT  0.06 28.392 0.133 28.464 ;
     RECT  0.084 28.464 0.133 28.488 ;
     RECT  0.06 28.488 0.133 28.56 ;
     RECT  0.084 28.56 0.133 28.584 ;
     RECT  0.06 28.584 0.133 28.656 ;
     RECT  0.084 28.656 0.133 28.68 ;
     RECT  0.06 28.68 0.133 28.752 ;
     RECT  0.084 28.752 0.133 28.776 ;
     RECT  0.06 28.776 0.133 28.848 ;
     RECT  0.084 28.848 0.133 28.872 ;
     RECT  0.06 28.872 0.133 28.944 ;
     RECT  0.084 28.944 0.133 28.968 ;
     RECT  0.06 28.968 0.133 29.04 ;
     RECT  0.084 29.04 0.133 29.064 ;
     RECT  0.06 29.064 0.133 29.136 ;
     RECT  0.084 29.136 0.133 29.16 ;
     RECT  0.06 29.16 0.133 29.232 ;
     RECT  0.084 29.232 0.133 29.256 ;
     RECT  0.06 29.256 0.133 29.328 ;
     RECT  0.084 29.328 0.133 29.352 ;
     RECT  0.06 29.352 0.133 29.424 ;
     RECT  0.084 29.424 0.133 29.448 ;
     RECT  0.06 29.448 0.133 29.52 ;
     RECT  0.084 29.52 0.133 29.544 ;
     RECT  0.06 29.544 0.133 29.616 ;
     RECT  0.084 29.616 0.133 29.64 ;
     RECT  0.06 29.64 0.133 29.712 ;
     RECT  0.084 29.712 0.133 29.736 ;
     RECT  0.06 29.736 0.133 29.808 ;
     RECT  0.084 29.808 0.133 29.832 ;
     RECT  0.06 29.832 0.133 29.904 ;
     RECT  0.084 29.904 0.133 29.928 ;
     RECT  0.06 29.928 0.133 30 ;
     RECT  0.084 30 0.133 30.024 ;
     RECT  0.06 30.024 0.133 30.096 ;
     RECT  0.084 30.096 0.133 30.12 ;
     RECT  0.06 30.12 0.133 30.192 ;
     RECT  0.084 30.192 0.133 30.216 ;
     RECT  0.06 30.216 0.133 30.288 ;
     RECT  0.084 30.288 0.133 30.312 ;
     RECT  0.06 30.312 0.133 30.384 ;
     RECT  0.084 30.384 0.133 30.408 ;
     RECT  0.06 30.408 0.133 30.48 ;
     RECT  0.084 30.48 0.133 30.504 ;
     RECT  0.06 30.504 0.133 30.576 ;
     RECT  0.084 30.576 0.133 30.6 ;
     RECT  0.06 30.6 0.133 30.672 ;
     RECT  0.084 30.672 0.133 30.696 ;
     RECT  0.06 30.696 0.133 30.768 ;
     RECT  0.084 30.768 0.133 30.792 ;
     RECT  0.06 30.792 0.133 30.864 ;
     RECT  0.084 30.864 0.133 30.888 ;
     RECT  0.06 30.888 0.133 30.96 ;
     RECT  0.084 30.96 0.133 30.984 ;
     RECT  0.06 30.984 0.133 31.056 ;
     RECT  0.084 31.056 0.133 31.08 ;
     RECT  0.06 31.08 0.133 31.152 ;
     RECT  0.084 31.152 0.133 31.176 ;
     RECT  0.06 31.176 0.133 31.248 ;
     RECT  0.084 31.248 0.133 31.272 ;
     RECT  0.06 31.272 0.133 31.344 ;
     RECT  0.084 31.344 0.133 31.368 ;
     RECT  0.06 31.368 0.133 31.44 ;
     RECT  0.084 31.44 0.133 31.464 ;
     RECT  0.06 31.464 0.133 31.536 ;
     RECT  0.084 31.536 0.133 31.56 ;
     RECT  0.06 31.56 0.133 31.632 ;
     RECT  0.084 31.632 0.133 31.656 ;
     RECT  0.06 31.656 0.133 31.728 ;
     RECT  0.084 31.728 0.133 31.752 ;
     RECT  0.06 31.752 0.133 31.824 ;
     RECT  0.084 31.824 0.133 31.848 ;
     RECT  0.06 31.848 0.133 31.92 ;
     RECT  0.084 31.92 0.133 31.944 ;
     RECT  0.06 31.944 0.133 32.016 ;
     RECT  0.084 32.016 0.133 32.04 ;
     RECT  0.06 32.04 0.133 32.112 ;
     RECT  0.084 32.112 0.133 32.136 ;
     RECT  0.06 32.136 0.133 32.208 ;
     RECT  0.084 32.208 0.133 32.232 ;
     RECT  0.06 32.232 0.133 32.304 ;
     RECT  0.084 32.304 0.133 32.328 ;
     RECT  0.06 32.328 0.133 32.4 ;
     RECT  0.084 32.4 0.133 32.424 ;
     RECT  0.06 32.424 0.133 32.496 ;
     RECT  0.084 32.496 0.133 32.52 ;
     RECT  0.06 32.52 0.133 32.592 ;
     RECT  0.084 32.592 0.133 32.616 ;
     RECT  0.06 32.616 0.133 32.688 ;
     RECT  0.084 32.688 0.133 32.712 ;
     RECT  0.06 32.712 0.133 32.784 ;
     RECT  0.084 32.784 0.133 32.808 ;
     RECT  0.06 32.808 0.133 32.88 ;
     RECT  0.084 32.88 0.133 32.904 ;
     RECT  0.06 32.904 0.133 32.976 ;
     RECT  0.084 32.976 0.133 33 ;
     RECT  0.06 33 0.133 33.072 ;
     RECT  0.084 33.072 0.133 33.096 ;
     RECT  0.06 33.096 0.133 33.168 ;
     RECT  0.084 33.168 0.133 33.192 ;
     RECT  0.06 33.192 0.133 33.264 ;
     RECT  0.084 33.264 0.133 33.288 ;
     RECT  0.06 33.288 0.133 33.36 ;
     RECT  0.084 33.36 0.133 33.384 ;
     RECT  0.06 33.384 0.133 33.456 ;
     RECT  0.084 33.456 0.133 33.48 ;
     RECT  0.06 33.48 0.133 33.552 ;
     RECT  0.084 33.552 0.133 33.576 ;
     RECT  0.06 33.576 0.133 33.648 ;
     RECT  0.084 33.648 0.133 33.672 ;
     RECT  0.06 33.672 0.133 33.744 ;
     RECT  0.084 33.744 0.133 33.768 ;
     RECT  0.06 33.768 0.133 33.84 ;
     RECT  0.084 33.84 0.133 33.864 ;
     RECT  0.06 33.864 0.133 33.936 ;
     RECT  0.084 33.936 0.133 33.96 ;
     RECT  0.06 33.96 0.133 34.032 ;
     RECT  0.084 34.032 0.133 34.056 ;
     RECT  0.06 34.056 0.133 34.128 ;
     RECT  0.084 34.128 0.133 34.152 ;
     RECT  0.06 34.152 0.133 34.224 ;
     RECT  0.084 34.224 0.133 34.248 ;
     RECT  0.06 34.248 0.133 34.32 ;
     RECT  0.084 34.32 0.133 34.344 ;
     RECT  0.06 34.344 0.133 34.416 ;
     RECT  0.084 34.416 0.133 34.44 ;
     RECT  0.06 34.44 0.133 34.512 ;
     RECT  0.084 34.512 0.133 34.536 ;
     RECT  0.06 34.536 0.133 34.608 ;
     RECT  0.084 34.608 0.133 34.632 ;
     RECT  0.06 34.632 0.133 34.704 ;
     RECT  0.084 34.704 0.133 34.728 ;
     RECT  0.06 34.728 0.133 34.8 ;
     RECT  0.084 34.8 0.133 34.824 ;
     RECT  0.06 34.824 0.133 34.896 ;
     RECT  0.084 34.896 0.133 34.92 ;
     RECT  0.06 34.92 0.133 34.992 ;
     RECT  0.084 34.992 0.133 35.016 ;
     RECT  0.06 35.016 0.133 35.088 ;
     RECT  0.084 35.088 0.133 35.112 ;
     RECT  0.06 35.112 0.133 35.184 ;
     RECT  0.084 35.184 0.133 35.208 ;
     RECT  0.06 35.208 0.133 35.28 ;
     RECT  0.084 35.28 0.133 35.304 ;
     RECT  0.06 35.304 0.133 35.376 ;
     RECT  0.084 35.376 0.133 35.4 ;
     RECT  0.06 35.4 0.133 35.472 ;
     RECT  0.084 35.472 0.133 35.496 ;
     RECT  0.06 35.496 0.133 35.568 ;
     RECT  0.084 35.568 0.133 35.592 ;
     RECT  0.06 35.592 0.133 35.664 ;
     RECT  0.084 35.664 0.133 35.688 ;
     RECT  0.06 35.688 0.133 35.76 ;
     RECT  0.084 35.76 0.133 35.784 ;
     RECT  0.06 35.784 0.133 35.856 ;
     RECT  0.084 35.856 0.133 35.88 ;
     RECT  0.06 35.88 0.133 35.952 ;
     RECT  0.084 35.952 0.133 35.976 ;
     RECT  0.06 35.976 0.133 36.048 ;
     RECT  0.084 36.048 0.133 36.072 ;
     RECT  0.06 36.072 0.133 36.144 ;
     RECT  0.084 36.144 0.133 36.168 ;
     RECT  0.06 36.168 0.133 36.24 ;
     RECT  0.084 36.24 0.133 36.264 ;
     RECT  0.06 36.264 0.133 36.336 ;
     RECT  0.084 36.336 0.133 36.36 ;
     RECT  0.06 36.36 0.133 36.432 ;
     RECT  0.084 36.432 0.133 36.456 ;
     RECT  0.06 36.456 0.133 36.528 ;
     RECT  0.084 36.528 0.133 36.552 ;
     RECT  0.06 36.552 0.133 36.624 ;
     RECT  0.084 36.624 0.133 36.648 ;
     RECT  0.06 36.648 0.133 36.72 ;
     RECT  0.084 36.72 0.133 36.744 ;
     RECT  0.06 36.744 0.133 36.816 ;
     RECT  0.084 36.816 0.133 36.84 ;
     RECT  0.06 36.84 0.133 36.912 ;
     RECT  0.084 36.912 0.133 36.936 ;
     RECT  0.06 36.936 0.133 37.008 ;
     RECT  0.084 37.008 0.133 37.032 ;
     RECT  0.06 37.032 0.133 37.104 ;
     RECT  0.084 37.104 0.133 37.128 ;
     RECT  0.06 37.128 0.133 37.2 ;
     RECT  0.084 37.2 0.133 37.224 ;
     RECT  0.06 37.224 0.133 37.296 ;
     RECT  0.084 37.296 0.133 37.32 ;
     RECT  0.06 37.32 0.133 37.392 ;
     RECT  0.084 37.392 0.133 37.416 ;
     RECT  0.06 37.416 0.133 37.488 ;
     RECT  0.084 37.488 0.133 37.512 ;
     RECT  0.06 37.512 0.133 37.584 ;
     RECT  0.084 37.584 0.133 37.608 ;
     RECT  0.06 37.608 0.133 37.68 ;
     RECT  0.084 37.68 0.133 37.704 ;
     RECT  0.06 37.704 0.133 37.776 ;
     RECT  0.084 37.776 0.133 37.8 ;
     RECT  0.06 37.8 0.133 37.872 ;
     RECT  0.084 37.872 0.133 37.896 ;
     RECT  0.06 37.896 0.133 37.968 ;
     RECT  0.084 37.968 0.133 37.992 ;
     RECT  0.06 37.992 0.133 38.064 ;
     RECT  0.084 38.064 0.133 38.088 ;
     RECT  0.06 38.088 0.133 38.16 ;
     RECT  0.084 38.16 0.133 38.184 ;
     RECT  0.06 38.184 0.133 38.256 ;
     RECT  0.084 38.256 0.133 38.28 ;
     RECT  0.06 38.28 0.133 38.352 ;
     RECT  0.084 38.352 0.133 38.376 ;
     RECT  0.06 38.376 0.133 38.448 ;
     RECT  0.084 38.448 0.133 38.472 ;
     RECT  0.06 38.472 0.133 38.544 ;
     RECT  0.084 38.544 0.133 38.568 ;
     RECT  0.06 38.568 0.133 38.64 ;
     RECT  0.084 38.64 0.133 38.664 ;
     RECT  0.06 38.664 0.133 38.736 ;
     RECT  0.084 38.736 0.133 38.76 ;
     RECT  0.06 38.76 0.133 38.832 ;
     RECT  0.084 38.832 0.133 38.856 ;
     RECT  0.06 38.856 0.133 38.928 ;
     RECT  0.084 38.928 0.133 38.952 ;
     RECT  0.06 38.952 0.133 39.024 ;
     RECT  0.084 39.024 0.133 39.048 ;
     RECT  0.06 39.048 0.133 39.12 ;
     RECT  0.084 39.12 0.133 39.144 ;
     RECT  0.06 39.144 0.133 39.216 ;
     RECT  0.084 39.216 0.133 39.24 ;
     RECT  0.06 39.24 0.133 39.312 ;
     RECT  0.084 39.312 0.133 39.336 ;
     RECT  0.06 39.336 0.133 39.408 ;
     RECT  0.084 39.408 0.133 39.432 ;
     RECT  0.06 39.432 0.133 39.504 ;
     RECT  0.084 39.504 0.133 39.528 ;
     RECT  0.06 39.528 0.133 39.6 ;
     RECT  0.084 39.6 0.133 39.624 ;
     RECT  0.06 39.624 0.133 39.696 ;
     RECT  0.084 39.696 0.133 39.72 ;
     RECT  0.06 39.72 0.133 39.792 ;
     RECT  0.084 39.792 0.133 39.816 ;
     RECT  0.06 39.816 0.133 39.888 ;
     RECT  0.084 39.888 0.133 39.912 ;
     RECT  0.06 39.912 0.133 39.984 ;
     RECT  0.084 39.984 0.133 40.008 ;
     RECT  0.06 40.008 0.133 40.08 ;
     RECT  0.084 40.08 0.133 40.104 ;
     RECT  0.06 40.104 0.133 40.176 ;
     RECT  0.084 40.176 0.133 40.2 ;
     RECT  0.06 40.2 0.133 40.272 ;
     RECT  0.084 40.272 0.133 40.296 ;
     RECT  0.06 40.296 0.133 40.368 ;
     RECT  0.084 40.368 0.133 40.392 ;
     RECT  0.06 40.392 0.133 40.464 ;
     RECT  0.084 40.464 0.133 40.488 ;
     RECT  0.06 40.488 0.133 41.328 ;
     RECT  0.084 41.328 0.133 41.352 ;
     RECT  0.06 41.352 0.133 41.424 ;
     RECT  0.084 41.424 0.133 41.448 ;
     RECT  0.06 41.448 0.133 41.52 ;
     RECT  0.084 41.52 0.133 41.544 ;
     RECT  0.06 41.544 0.133 41.616 ;
     RECT  0.084 41.616 0.133 41.64 ;
     RECT  0.06 41.64 0.133 41.712 ;
     RECT  0.084 41.712 0.133 41.736 ;
     RECT  0.06 41.736 0.133 41.808 ;
     RECT  0.084 41.808 0.133 41.832 ;
     RECT  0.06 41.832 0.133 41.904 ;
     RECT  0.084 41.904 0.133 41.928 ;
     RECT  0.06 41.928 0.133 42 ;
     RECT  0.084 42 0.133 42.024 ;
     RECT  0.06 42.024 0.133 42.096 ;
     RECT  0.084 42.096 0.133 42.12 ;
     RECT  0.06 42.12 0.133 42.192 ;
     RECT  0.084 42.192 0.133 42.216 ;
     RECT  0.06 42.216 0.133 42.288 ;
     RECT  0.084 42.288 0.133 42.312 ;
     RECT  0.06 42.312 0.133 42.384 ;
     RECT  0.084 42.384 0.133 42.408 ;
     RECT  0.06 42.408 0.133 42.48 ;
     RECT  0.084 42.48 0.133 42.504 ;
     RECT  0.06 42.504 0.133 42.576 ;
     RECT  0.084 42.576 0.133 42.6 ;
     RECT  0.06 42.6 0.133 42.672 ;
     RECT  0.084 42.672 0.133 42.696 ;
     RECT  0.06 42.696 0.133 42.768 ;
     RECT  0.084 42.768 0.133 42.792 ;
     RECT  0.06 42.792 0.133 42.864 ;
     RECT  0.084 42.864 0.133 42.888 ;
     RECT  0.06 42.888 0.133 42.96 ;
     RECT  0.084 42.96 0.133 42.984 ;
     RECT  0.06 42.984 0.133 43.056 ;
     RECT  0.084 43.056 0.133 43.08 ;
     RECT  0.06 43.08 0.133 43.152 ;
     RECT  0.084 43.152 0.133 43.176 ;
     RECT  0.06 43.176 0.133 43.248 ;
     RECT  0.084 43.248 0.133 43.272 ;
     RECT  0.06 43.272 0.133 43.344 ;
     RECT  0.084 43.344 0.133 43.368 ;
     RECT  0.06 43.368 0.133 43.44 ;
     RECT  0.084 43.44 0.133 43.464 ;
     RECT  0.06 43.464 0.133 43.536 ;
     RECT  0.084 43.536 0.133 43.56 ;
     RECT  0.06 43.56 0.133 43.632 ;
     RECT  0.084 43.632 0.133 43.656 ;
     RECT  0.06 43.656 0.133 43.728 ;
     RECT  0.084 43.728 0.133 43.752 ;
     RECT  0.06 43.752 0.133 43.824 ;
     RECT  0.084 43.824 0.133 43.848 ;
     RECT  0.06 43.848 0.133 43.92 ;
     RECT  0.084 43.92 0.133 43.944 ;
     RECT  0.06 43.944 0.133 44.016 ;
     RECT  0.084 44.016 0.133 44.04 ;
     RECT  0.06 44.04 0.133 44.112 ;
     RECT  0.084 44.112 0.133 44.136 ;
     RECT  0.06 44.136 0.133 44.208 ;
     RECT  0.084 44.208 0.133 44.232 ;
     RECT  0.06 44.232 0.133 44.304 ;
     RECT  0.084 44.304 0.133 44.328 ;
     RECT  0.06 44.328 0.133 44.4 ;
     RECT  0.084 44.4 0.133 44.424 ;
     RECT  0.06 44.424 0.133 44.496 ;
     RECT  0.084 44.496 0.133 44.52 ;
     RECT  0.06 44.52 0.133 44.592 ;
     RECT  0.084 44.592 0.133 44.616 ;
     RECT  0.06 44.616 0.133 44.688 ;
     RECT  0.084 44.688 0.133 44.712 ;
     RECT  0.06 44.712 0.133 44.784 ;
     RECT  0.084 44.784 0.133 44.808 ;
     RECT  0.06 44.808 0.133 44.88 ;
     RECT  0.084 44.88 0.133 44.904 ;
     RECT  0.06 44.904 0.133 44.976 ;
     RECT  0.084 44.976 0.133 45 ;
     RECT  0.06 45 0.133 45.072 ;
     RECT  0.084 45.072 0.133 45.096 ;
     RECT  0.06 45.096 0.133 45.168 ;
     RECT  0.084 45.168 0.133 45.192 ;
     RECT  0.06 45.192 0.133 45.264 ;
     RECT  0.084 45.264 0.133 45.288 ;
     RECT  0.06 45.288 0.133 45.36 ;
     RECT  0.084 45.36 0.133 45.384 ;
     RECT  0.06 45.384 0.133 45.456 ;
     RECT  0.084 45.456 0.133 45.48 ;
     RECT  0.06 45.48 0.133 45.552 ;
     RECT  0.084 45.552 0.133 45.576 ;
     RECT  0.06 45.576 0.133 45.648 ;
     RECT  0.084 45.648 0.133 45.672 ;
     RECT  0.06 45.672 0.133 45.744 ;
     RECT  0.084 45.744 0.133 45.768 ;
     RECT  0.06 45.768 0.133 45.84 ;
     RECT  0.084 45.84 0.133 45.864 ;
     RECT  0.06 45.864 0.133 45.936 ;
     RECT  0.084 45.936 0.133 45.96 ;
     RECT  0.06 45.96 0.133 46.032 ;
     RECT  0.084 46.032 0.133 46.056 ;
     RECT  0.06 46.056 0.133 46.128 ;
     RECT  0.084 46.128 0.133 46.152 ;
     RECT  0.06 46.152 0.133 46.224 ;
     RECT  0.084 46.224 0.133 46.248 ;
     RECT  0.06 46.248 0.133 46.32 ;
     RECT  0.084 46.32 0.133 46.344 ;
     RECT  0.06 46.344 0.133 46.416 ;
     RECT  0.084 46.416 0.133 46.44 ;
     RECT  0.06 46.44 0.133 46.512 ;
     RECT  0.084 46.512 0.133 46.536 ;
     RECT  0.06 46.536 0.133 46.608 ;
     RECT  0.084 46.608 0.133 46.632 ;
     RECT  0.06 46.632 0.133 46.704 ;
     RECT  0.084 46.704 0.133 46.728 ;
     RECT  0.06 46.728 0.133 46.8 ;
     RECT  0.084 46.8 0.133 46.824 ;
     RECT  0.06 46.824 0.133 46.896 ;
     RECT  0.084 46.896 0.133 46.92 ;
     RECT  0.06 46.92 0.133 46.992 ;
     RECT  0.084 46.992 0.133 47.016 ;
     RECT  0.06 47.016 0.133 47.088 ;
     RECT  0.084 47.088 0.133 47.112 ;
     RECT  0.06 47.112 0.133 47.184 ;
     RECT  0.084 47.184 0.133 47.208 ;
     RECT  0.06 47.208 0.133 47.28 ;
     RECT  0.084 47.28 0.133 47.304 ;
     RECT  0.06 47.304 0.133 47.376 ;
     RECT  0.084 47.376 0.133 47.4 ;
     RECT  0.06 47.4 0.133 47.472 ;
     RECT  0.084 47.472 0.133 47.496 ;
     RECT  0.06 47.496 0.133 47.568 ;
     RECT  0.084 47.568 0.133 47.592 ;
     RECT  0.06 47.592 0.133 47.664 ;
     RECT  0.084 47.664 0.133 47.688 ;
     RECT  0.06 47.688 0.133 47.76 ;
     RECT  0.084 47.76 0.133 47.784 ;
     RECT  0.06 47.784 0.133 47.856 ;
     RECT  0.084 47.856 0.133 47.88 ;
     RECT  0.06 47.88 0.133 47.952 ;
     RECT  0.084 47.952 0.133 47.976 ;
     RECT  0.06 47.976 0.133 48.048 ;
     RECT  0.084 48.048 0.133 48.072 ;
     RECT  0.06 48.072 0.133 48.144 ;
     RECT  0.084 48.144 0.133 48.168 ;
     RECT  0.06 48.168 0.133 48.24 ;
     RECT  0.084 48.24 0.133 48.264 ;
     RECT  0.06 48.264 0.133 48.336 ;
     RECT  0.084 48.336 0.133 48.36 ;
     RECT  0.06 48.36 0.133 48.432 ;
     RECT  0.084 48.432 0.133 48.456 ;
     RECT  0.06 48.456 0.133 48.528 ;
     RECT  0.084 48.528 0.133 48.552 ;
     RECT  0.06 48.552 0.133 48.624 ;
     RECT  0.084 48.624 0.133 48.648 ;
     RECT  0.06 48.648 0.133 48.72 ;
     RECT  0.084 48.72 0.133 48.744 ;
     RECT  0.06 48.744 0.133 48.816 ;
     RECT  0.084 48.816 0.133 48.84 ;
     RECT  0.06 48.84 0.133 48.912 ;
     RECT  0.084 48.912 0.133 48.936 ;
     RECT  0.06 48.936 0.133 49.008 ;
     RECT  0.084 49.008 0.133 49.032 ;
     RECT  0.06 49.032 0.133 49.104 ;
     RECT  0.084 49.104 0.133 49.128 ;
     RECT  0.06 49.128 0.133 49.2 ;
     RECT  0.084 49.2 0.133 49.224 ;
     RECT  0.06 49.224 0.133 49.296 ;
     RECT  0.084 49.296 0.133 49.32 ;
     RECT  0.06 49.32 0.133 49.392 ;
     RECT  0.084 49.392 0.133 49.416 ;
     RECT  0.06 49.416 0.133 49.488 ;
     RECT  0.084 49.488 0.133 49.512 ;
     RECT  0.06 49.512 0.133 49.584 ;
     RECT  0.084 49.584 0.133 49.608 ;
     RECT  0.06 49.608 0.133 49.68 ;
     RECT  0.084 49.68 0.133 49.704 ;
     RECT  0.06 49.704 0.133 49.776 ;
     RECT  0.084 49.776 0.133 49.8 ;
     RECT  0.06 49.8 0.133 49.872 ;
     RECT  0.084 49.872 0.133 49.896 ;
     RECT  0.06 49.896 0.133 49.968 ;
     RECT  0.084 49.968 0.133 49.992 ;
     RECT  0.06 49.992 0.133 50.064 ;
     RECT  0.084 50.064 0.133 50.088 ;
     RECT  0.06 50.088 0.133 50.16 ;
     RECT  0.084 50.16 0.133 50.184 ;
     RECT  0.06 50.184 0.133 50.256 ;
     RECT  0.084 50.256 0.133 50.28 ;
     RECT  0.06 50.28 0.133 50.352 ;
     RECT  0.084 50.352 0.133 50.376 ;
     RECT  0.06 50.376 0.133 50.448 ;
     RECT  0.084 50.448 0.133 50.472 ;
     RECT  0.06 50.472 0.133 50.544 ;
     RECT  0.084 50.544 0.133 50.568 ;
     RECT  0.06 50.568 0.133 50.64 ;
     RECT  0.084 50.64 0.133 50.664 ;
     RECT  0.06 50.664 0.133 50.736 ;
     RECT  0.084 50.736 0.133 50.76 ;
     RECT  0.06 50.76 0.133 50.832 ;
     RECT  0.084 50.832 0.133 50.856 ;
     RECT  0.06 50.856 0.133 50.928 ;
     RECT  0.084 50.928 0.133 50.952 ;
     RECT  0.06 50.952 0.133 51.024 ;
     RECT  0.084 51.024 0.133 51.048 ;
     RECT  0.06 51.048 0.133 51.12 ;
     RECT  0.084 51.12 0.133 51.144 ;
     RECT  0.06 51.144 0.133 51.216 ;
     RECT  0.084 51.216 0.133 51.24 ;
     RECT  0.06 51.24 0.133 51.312 ;
     RECT  0.084 51.312 0.133 51.336 ;
     RECT  0.06 51.336 0.133 51.408 ;
     RECT  0.084 51.408 0.133 51.432 ;
     RECT  0.06 51.432 0.133 51.504 ;
     RECT  0.084 51.504 0.133 51.528 ;
     RECT  0.06 51.528 0.133 51.6 ;
     RECT  0.084 51.6 0.133 51.624 ;
     RECT  0.06 51.624 0.133 51.696 ;
     RECT  0.084 51.696 0.133 51.72 ;
     RECT  0.06 51.72 0.133 51.792 ;
     RECT  0.084 51.792 0.133 51.816 ;
     RECT  0.06 51.816 0.133 51.888 ;
     RECT  0.084 51.888 0.133 51.912 ;
     RECT  0.06 51.912 0.133 51.984 ;
     RECT  0.084 51.984 0.133 52.008 ;
     RECT  0.06 52.008 0.133 52.08 ;
     RECT  0.084 52.08 0.133 52.104 ;
     RECT  0.06 52.104 0.133 52.176 ;
     RECT  0.084 52.176 0.133 52.2 ;
     RECT  0.06 52.2 0.133 52.272 ;
     RECT  0.084 52.272 0.133 52.296 ;
     RECT  0.06 52.296 0.133 52.368 ;
     RECT  0.084 52.368 0.133 52.392 ;
     RECT  0.06 52.392 0.133 52.464 ;
     RECT  0.084 52.464 0.133 52.488 ;
     RECT  0.06 52.488 0.133 52.56 ;
     RECT  0.084 52.56 0.133 52.584 ;
     RECT  0.06 52.584 0.133 52.656 ;
     RECT  0.084 52.656 0.133 52.68 ;
     RECT  0.06 52.68 0.133 52.752 ;
     RECT  0.084 52.752 0.133 52.776 ;
     RECT  0.06 52.776 0.133 52.848 ;
     RECT  0.084 52.848 0.133 52.872 ;
     RECT  0.06 52.872 0.133 52.944 ;
     RECT  0.084 52.944 0.133 52.968 ;
     RECT  0.06 52.968 0.133 53.04 ;
     RECT  0.084 53.04 0.133 53.064 ;
     RECT  0.06 53.064 0.133 53.136 ;
     RECT  0.084 53.136 0.133 53.16 ;
     RECT  0.06 53.16 0.133 53.232 ;
     RECT  0.084 53.232 0.133 53.256 ;
     RECT  0.06 53.256 0.133 53.328 ;
     RECT  0.084 53.328 0.133 53.352 ;
     RECT  0.06 53.352 0.133 53.424 ;
     RECT  0.084 53.424 0.133 53.448 ;
     RECT  0.06 53.448 0.133 53.52 ;
     RECT  0.084 53.52 0.133 53.544 ;
     RECT  0.133 2.928 0.137 53.592 ;
     RECT  0.137 3.024 2.285 53.592 ;
     RECT  2.285 3.024 2.408 54.168 ;
     RECT  0.084 55.536 2.408 55.56 ;
     RECT  0.06 55.56 2.408 55.632 ;
     RECT  0.084 55.632 2.408 55.656 ;
     RECT  0.06 55.656 2.408 55.728 ;
     RECT  0.084 55.728 2.408 55.752 ;
     RECT  0.06 55.752 2.408 55.824 ;
     RECT  0.084 55.824 2.408 55.848 ;
     RECT  0.06 55.848 2.408 55.92 ;
     RECT  0.084 55.92 2.408 55.944 ;
     RECT  0.06 55.944 2.408 56.016 ;
     RECT  0.084 56.016 2.408 56.04 ;
     RECT  0.06 56.04 2.408 56.112 ;
     RECT  0.084 56.112 2.408 56.136 ;
     RECT  0.06 56.136 2.408 56.208 ;
     RECT  0.084 56.208 2.408 56.232 ;
     RECT  0.06 56.232 2.408 56.304 ;
     RECT  0.084 56.304 2.408 56.328 ;
     RECT  0.06 56.328 2.408 56.4 ;
     RECT  0.084 56.4 2.408 56.424 ;
     RECT  0.06 56.424 2.408 56.496 ;
     RECT  0.084 56.496 2.408 56.52 ;
     RECT  0.06 56.52 2.408 56.592 ;
     RECT  0.084 56.592 2.408 56.616 ;
     RECT  2.408 2.148 2.512 58.332 ;
     RECT  2.512 2.418 2.704 58.062 ;
     RECT  2.704 2.832 2.765 3.144 ;
     RECT  2.704 4.416 2.867 54.552 ;
     RECT  2.867 4.416 2.909 27.432 ;
     RECT  2.909 4.464 2.981 27.432 ;
     RECT  2.704 55.728 3.017 56.328 ;
     RECT  3.017 55.728 3.341 56.088 ;
     RECT  2.981 4.944 3.377 27.432 ;
     RECT  3.377 4.944 3.521 7.416 ;
     RECT  3.521 4.944 3.557 5.208 ;
     RECT  3.377 8.496 3.836 27.432 ;
     RECT  2.867 28.416 3.836 53.832 ;
     RECT  2.765 2.832 3.877 3.048 ;
     RECT  3.877 2.832 4.021 3.24 ;
     RECT  3.836 8.496 4.021 53.832 ;
     RECT  3.685 55.152 4.021 55.176 ;
     RECT  4.021 2.304 4.165 3.24 ;
     RECT  4.165 2.304 4.525 3.96 ;
     RECT  3.557 5.184 4.525 5.208 ;
     RECT  4.525 2.304 4.669 5.208 ;
     RECT  3.521 6.528 4.669 7.416 ;
     RECT  4.021 8.496 5.029 55.176 ;
     RECT  4.669 2.304 5.108 7.416 ;
     RECT  5.029 8.448 5.108 55.176 ;
     RECT  4.525 56.256 5.108 56.424 ;
     RECT  5.108 2.148 5.212 58.332 ;
     RECT  5.212 2.304 5.404 58.062 ;
     RECT  5.404 2.304 5.465 56.52 ;
     RECT  5.465 2.832 5.795 56.52 ;
     RECT  5.795 2.832 5.933 55.032 ;
     RECT  5.933 3.312 6.659 55.032 ;
     RECT  6.659 55.008 6.865 55.032 ;
     RECT  5.795 56.256 6.865 56.52 ;
     RECT  6.659 3.312 6.949 53.928 ;
     RECT  6.949 3.168 7.808 53.928 ;
     RECT  6.865 55.008 7.808 56.52 ;
     RECT  7.808 2.148 7.912 58.332 ;
     RECT  7.912 2.418 8.104 58.062 ;
     RECT  8.104 55.152 8.165 55.992 ;
     RECT  8.104 3.6 8.243 53.832 ;
     RECT  8.165 55.968 8.243 55.992 ;
     RECT  8.243 3.6 8.273 4.536 ;
     RECT  8.243 5.568 8.309 53.832 ;
     RECT  8.273 3.84 8.417 4.536 ;
     RECT  8.309 52.272 8.579 53.832 ;
     RECT  8.309 5.568 8.669 51.144 ;
     RECT  8.669 6.24 8.819 51.144 ;
     RECT  8.819 6.24 8.867 47.64 ;
     RECT  8.417 3.84 8.915 3.864 ;
     RECT  8.867 6.816 8.957 47.64 ;
     RECT  8.819 48.672 8.993 51.144 ;
     RECT  8.957 6.816 9.209 47.4 ;
     RECT  9.209 10.464 9.217 47.4 ;
     RECT  9.209 6.816 9.251 9 ;
     RECT  9.251 8.448 9.299 9 ;
     RECT  9.299 8.976 9.347 9 ;
     RECT  9.217 10.464 9.389 47.352 ;
     RECT  9.389 10.608 9.491 47.352 ;
     RECT  8.579 53.088 10.429 53.832 ;
     RECT  9.251 6.816 10.508 7.416 ;
     RECT  9.491 10.608 10.508 44.472 ;
     RECT  9.491 45.456 10.508 47.352 ;
     RECT  8.993 48.672 10.508 49.32 ;
     RECT  8.993 50.4 10.508 51.144 ;
     RECT  10.429 53.04 10.508 53.832 ;
     RECT  10.508 2.148 10.612 58.332 ;
     RECT  10.612 2.418 10.804 58.062 ;
     RECT  10.804 15.312 10.829 20.376 ;
     RECT  10.804 21.456 10.829 30.168 ;
     RECT  10.804 38.256 10.829 38.28 ;
     RECT  10.829 29.328 10.901 30.168 ;
     RECT  10.804 41.472 10.931 46.104 ;
     RECT  10.829 15.312 11.027 20.088 ;
     RECT  10.931 41.952 11.081 46.104 ;
     RECT  10.804 13.056 11.219 14.136 ;
     RECT  10.804 31.248 11.219 36.936 ;
     RECT  11.219 32.832 11.261 36.936 ;
     RECT  11.027 15.984 11.297 20.088 ;
     RECT  11.297 15.984 11.333 19.56 ;
     RECT  11.219 13.632 11.411 14.136 ;
     RECT  11.261 32.832 11.411 33.672 ;
     RECT  11.219 31.248 11.441 31.464 ;
     RECT  11.261 35.328 11.441 36.936 ;
     RECT  11.081 41.952 11.441 44.088 ;
     RECT  11.411 13.632 11.459 13.656 ;
     RECT  11.441 43.584 11.459 44.088 ;
     RECT  11.081 45.456 11.507 46.104 ;
     RECT  10.901 29.328 11.549 30.12 ;
     RECT  11.411 32.832 11.657 32.856 ;
     RECT  11.333 16.032 11.773 19.56 ;
     RECT  10.804 47.856 11.797 49.32 ;
     RECT  10.804 50.4 11.797 51.48 ;
     RECT  11.441 36.912 11.843 36.936 ;
     RECT  11.797 47.856 11.891 51.48 ;
     RECT  11.441 41.952 11.905 42.6 ;
     RECT  11.905 41.568 11.945 42.6 ;
     RECT  10.309 0.096 11.981 0.12 ;
     RECT  10.829 21.456 11.981 28.344 ;
     RECT  11.891 47.856 12.089 49.56 ;
     RECT  11.981 21.456 12.125 27.96 ;
     RECT  10.804 52.944 12.157 53.832 ;
     RECT  12.089 47.856 12.179 49.32 ;
     RECT  12.179 47.856 12.229 48.84 ;
     RECT  11.833 39.888 12.337 39.912 ;
     RECT  11.549 29.328 12.373 29.784 ;
     RECT  12.125 21.456 12.437 21.576 ;
     RECT  11.891 50.784 12.445 51.48 ;
     RECT  11.773 17.424 12.469 19.56 ;
     RECT  12.437 21.12 12.469 21.576 ;
     RECT  12.157 52.752 12.504 53.832 ;
     RECT  11.507 46.08 12.517 46.104 ;
     RECT  12.517 36.432 12.661 36.456 ;
     RECT  12.157 45.024 12.697 45.048 ;
     RECT  12.517 46.08 12.697 46.344 ;
     RECT  12.373 29.232 12.709 29.784 ;
     RECT  11.441 31.44 12.709 31.464 ;
     RECT  12.504 52.704 12.805 53.832 ;
     RECT  12.337 39.888 12.841 40.44 ;
     RECT  12.805 52.704 12.949 53.928 ;
     RECT  12.733 33.12 12.985 33.144 ;
     RECT  12.661 36.336 12.985 36.456 ;
     RECT  12.697 45.024 12.985 46.344 ;
     RECT  12.229 47.664 12.985 48.84 ;
     RECT  11.441 35.328 13.021 35.352 ;
     RECT  13.021 34.8 13.045 35.352 ;
     RECT  11.945 41.568 13.045 41.592 ;
     RECT  11.773 16.032 13.057 16.392 ;
     RECT  11.905 56.304 13.057 56.328 ;
     RECT  13.057 15.84 13.085 16.392 ;
     RECT  12.469 17.424 13.085 21.576 ;
     RECT  13.085 15.84 13.093 21.576 ;
     RECT  12.125 22.56 13.093 27.96 ;
     RECT  12.841 38.784 13.093 40.44 ;
     RECT  13.045 41.472 13.093 41.592 ;
     RECT  11.945 42.576 13.093 42.6 ;
     RECT  13.093 15.84 13.208 27.96 ;
     RECT  12.709 29.232 13.208 31.464 ;
     RECT  12.985 33.024 13.208 33.144 ;
     RECT  13.045 34.128 13.208 35.352 ;
     RECT  12.985 36.336 13.208 37.032 ;
     RECT  13.093 38.784 13.208 42.6 ;
     RECT  11.459 43.584 13.208 43.944 ;
     RECT  12.985 45.024 13.208 48.84 ;
     RECT  12.445 50.784 13.208 51.528 ;
     RECT  12.949 52.704 13.208 54.216 ;
     RECT  12.121 55.248 13.208 55.272 ;
     RECT  13.057 56.304 13.208 56.904 ;
     RECT  13.208 2.148 13.312 58.332 ;
     RECT  13.312 2.418 13.504 58.152 ;
     RECT  13.504 43.248 13.637 48.024 ;
     RECT  13.504 18.144 13.715 33.816 ;
     RECT  13.504 36.336 13.817 37.704 ;
     RECT  13.637 43.248 13.889 47.88 ;
     RECT  13.504 15.84 14.177 17.112 ;
     RECT  14.177 16.416 14.195 17.112 ;
     RECT  13.777 59.232 14.195 59.256 ;
     RECT  14.195 16.416 14.236 16.776 ;
     RECT  13.715 18.144 14.285 19.56 ;
     RECT  13.504 35.088 14.435 35.208 ;
     RECT  13.715 21.072 14.483 33.816 ;
     RECT  13.889 43.248 14.485 47.736 ;
     RECT  13.504 49.008 14.497 58.152 ;
     RECT  14.483 29.328 14.531 33.816 ;
     RECT  13.504 39.12 14.533 41.736 ;
     RECT  14.531 30.672 14.573 33.816 ;
     RECT  14.285 18.96 14.677 19.56 ;
     RECT  14.483 21.072 14.677 28.056 ;
     RECT  14.497 48.96 14.753 58.152 ;
     RECT  14.677 18.96 14.771 28.056 ;
     RECT  13.817 36.384 14.785 37.704 ;
     RECT  14.533 38.928 14.785 41.736 ;
     RECT  14.435 35.088 14.789 35.112 ;
     RECT  14.753 49.056 14.789 58.152 ;
     RECT  14.789 49.056 14.797 49.08 ;
     RECT  14.425 59.856 14.821 59.88 ;
     RECT  14.789 50.304 14.825 58.152 ;
     RECT  14.236 16.656 14.861 16.776 ;
     RECT  14.573 30.672 14.861 32.856 ;
     RECT  14.771 20.448 14.867 28.056 ;
     RECT  14.861 30.672 14.867 31.896 ;
     RECT  14.825 50.736 14.893 58.152 ;
     RECT  14.821 59.856 14.893 60.312 ;
     RECT  14.867 20.448 14.897 27.96 ;
     RECT  14.893 50.736 14.897 58.728 ;
     RECT  14.893 59.856 14.956 60.36 ;
     RECT  14.785 36.384 14.965 41.736 ;
     RECT  14.485 42.72 14.965 47.736 ;
     RECT  14.861 16.752 15.289 16.776 ;
     RECT  14.965 36.384 15.469 47.736 ;
     RECT  14.897 50.928 15.589 58.728 ;
     RECT  15.289 16.752 15.649 17.448 ;
     RECT  14.771 18.96 15.649 18.984 ;
     RECT  15.469 36 15.757 47.736 ;
     RECT  15.589 50.928 15.797 59.256 ;
     RECT  15.649 16.752 15.865 18.984 ;
     RECT  15.865 16.752 15.901 19.368 ;
     RECT  15.901 16.752 15.908 19.56 ;
     RECT  14.897 20.736 15.908 27.96 ;
     RECT  14.531 29.328 15.908 29.4 ;
     RECT  14.867 30.672 15.908 31.656 ;
     RECT  15.757 36 15.908 48.792 ;
     RECT  15.797 50.928 15.908 58.68 ;
     RECT  15.908 2.148 16.012 58.68 ;
     RECT  16.012 2.418 16.204 58.68 ;
     RECT  14.956 60.288 16.261 60.36 ;
     RECT  16.204 18.192 16.265 21.48 ;
     RECT  16.204 17.088 16.301 17.112 ;
     RECT  16.204 32.448 16.301 34.488 ;
     RECT  16.261 60.048 16.403 60.36 ;
     RECT  16.204 50.112 16.445 58.68 ;
     RECT  16.403 60.144 16.481 60.36 ;
     RECT  16.301 32.448 16.499 33.096 ;
     RECT  16.481 60.24 16.499 60.36 ;
     RECT  16.204 42.768 16.517 43.944 ;
     RECT  16.499 60.336 16.525 60.36 ;
     RECT  16.204 30.672 16.547 30.696 ;
     RECT  16.265 18.192 16.595 18.984 ;
     RECT  16.265 20.256 16.595 21.288 ;
     RECT  16.445 50.352 16.661 58.68 ;
     RECT  16.204 35.712 16.697 39.624 ;
     RECT  16.661 51.168 16.697 58.68 ;
     RECT  16.301 34.416 16.739 34.488 ;
     RECT  16.204 22.464 16.805 29.592 ;
     RECT  16.499 33.072 16.913 33.096 ;
     RECT  16.697 37.968 16.985 39.624 ;
     RECT  16.595 20.592 17.129 21.288 ;
     RECT  16.517 43.008 17.165 43.944 ;
     RECT  16.204 41.04 17.197 41.4 ;
     RECT  16.985 38.544 17.324 39.624 ;
     RECT  17.197 40.944 17.324 41.4 ;
     RECT  16.204 44.928 17.341 48.792 ;
     RECT  16.739 34.416 17.345 34.44 ;
     RECT  16.697 51.36 17.345 58.68 ;
     RECT  16.595 18.192 17.377 18.408 ;
     RECT  16.805 22.464 17.381 27.624 ;
     RECT  17.324 38.544 17.411 41.4 ;
     RECT  17.129 20.688 17.413 21.288 ;
     RECT  17.381 22.464 17.413 26.568 ;
     RECT  17.413 20.688 17.453 26.568 ;
     RECT  17.453 22.176 17.459 26.568 ;
     RECT  17.411 40.944 17.653 41.4 ;
     RECT  17.485 42.768 17.653 42.792 ;
     RECT  17.165 43.92 17.653 43.944 ;
     RECT  17.341 44.928 17.653 48.984 ;
     RECT  17.345 51.408 17.669 58.68 ;
     RECT  16.697 35.712 17.845 36.552 ;
     RECT  17.669 51.408 17.885 58.44 ;
     RECT  17.381 27.6 18.061 27.624 ;
     RECT  16.805 28.704 18.061 29.592 ;
     RECT  17.411 38.544 18.085 39.816 ;
     RECT  17.653 43.92 18.349 48.984 ;
     RECT  17.804 16.512 18.608 16.536 ;
     RECT  17.377 17.52 18.608 18.408 ;
     RECT  17.453 20.688 18.608 20.712 ;
     RECT  17.459 22.176 18.608 22.2 ;
     RECT  17.459 23.568 18.608 26.568 ;
     RECT  18.061 27.6 18.608 29.592 ;
     RECT  18.241 30.816 18.608 30.84 ;
     RECT  18.601 31.968 18.608 31.992 ;
     RECT  18.349 34.128 18.608 34.152 ;
     RECT  17.845 35.328 18.608 36.552 ;
     RECT  18.085 37.584 18.608 39.816 ;
     RECT  17.653 40.944 18.608 42.792 ;
     RECT  18.349 43.92 18.608 49.896 ;
     RECT  17.885 51.408 18.608 58.332 ;
     RECT  18.608 2.148 18.712 58.332 ;
     RECT  18.712 2.418 18.904 58.062 ;
     RECT  18.904 35.808 18.929 37.608 ;
     RECT  18.904 38.688 18.965 39.816 ;
     RECT  18.904 44.352 18.965 46.008 ;
     RECT  18.904 47.328 19.043 49.896 ;
     RECT  18.904 27.6 19.073 28.536 ;
     RECT  18.965 38.736 19.139 39.816 ;
     RECT  18.904 33.024 19.181 33.384 ;
     RECT  19.181 33.024 19.289 33.288 ;
     RECT  18.904 42.48 19.397 42.504 ;
     RECT  19.289 33.024 19.433 33.048 ;
     RECT  18.965 45.984 19.433 46.008 ;
     RECT  18.904 19.92 19.577 21.144 ;
     RECT  19.043 47.328 19.577 48.984 ;
     RECT  19.577 47.904 19.649 48.984 ;
     RECT  18.904 30.24 19.721 30.264 ;
     RECT  19.139 38.736 19.793 39.24 ;
     RECT  18.904 41.04 19.897 41.064 ;
     RECT  19.649 48.24 19.937 48.984 ;
     RECT  19.577 20.64 20.005 21.144 ;
     RECT  19.897 41.04 20.009 41.496 ;
     RECT  18.965 44.352 20.009 44.952 ;
     RECT  20.009 44.352 20.081 44.424 ;
     RECT  20.005 20.64 20.092 21.528 ;
     RECT  18.904 22.896 20.109 26.616 ;
     RECT  18.904 51.12 20.149 57.912 ;
     RECT  20.092 20.64 20.153 20.664 ;
     RECT  18.904 34.368 20.189 34.824 ;
     RECT  20.189 34.752 20.257 34.824 ;
     RECT  18.929 36.24 20.257 37.608 ;
     RECT  19.793 38.976 20.297 39.24 ;
     RECT  20.297 38.976 20.333 39.096 ;
     RECT  19.969 32.256 20.437 32.616 ;
     RECT  20.109 23.04 20.473 26.616 ;
     RECT  19.073 27.6 20.473 28.488 ;
     RECT  20.473 23.04 20.773 28.488 ;
     RECT  20.041 59.856 20.801 59.88 ;
     RECT  20.257 34.752 20.869 37.608 ;
     RECT  20.333 38.976 20.869 39 ;
     RECT  19.937 48.432 21.085 48.984 ;
     RECT  21.02 60.384 21.107 60.408 ;
     RECT  20.149 50.4 21.121 57.912 ;
     RECT  20.257 45.552 21.157 45.576 ;
     RECT  20.437 32.256 21.265 33 ;
     RECT  20.773 23.04 21.308 28.536 ;
     RECT  21.265 32.256 21.308 33.048 ;
     RECT  20.869 34.752 21.308 39 ;
     RECT  20.009 41.472 21.308 41.496 ;
     RECT  20.081 44.352 21.308 44.376 ;
     RECT  21.157 45.552 21.308 46.344 ;
     RECT  21.085 47.568 21.308 48.984 ;
     RECT  21.121 50.064 21.308 57.912 ;
     RECT  21.308 2.148 21.412 58.332 ;
     RECT  21.412 2.418 21.604 58.152 ;
     RECT  21.604 32.592 21.665 34.728 ;
     RECT  21.604 35.808 21.881 36.84 ;
     RECT  21.604 43.968 21.881 46.536 ;
     RECT  21.665 32.592 21.917 34.152 ;
     RECT  21.604 23.856 21.953 28.776 ;
     RECT  21.917 33.024 21.953 34.152 ;
     RECT  21.953 23.856 21.989 26.136 ;
     RECT  21.604 39.744 22.012 40.008 ;
     RECT  21.604 47.856 22.025 58.152 ;
     RECT  21.881 35.808 22.097 36.6 ;
     RECT  21.604 42.144 22.241 42.792 ;
     RECT  21.989 24.912 22.349 26.136 ;
     RECT  21.953 33.408 22.385 34.152 ;
     RECT  21.881 43.968 22.457 46.104 ;
     RECT  21.604 38.016 22.669 38.184 ;
     RECT  22.457 43.968 22.777 44.472 ;
     RECT  22.669 38.016 22.837 38.424 ;
     RECT  22.241 42.144 22.853 42.168 ;
     RECT  22.813 40.56 22.897 40.584 ;
     RECT  22.837 37.584 22.924 39.336 ;
     RECT  21.953 27.216 22.997 28.776 ;
     RECT  22.349 25.008 23.137 26.136 ;
     RECT  22.997 27.216 23.137 28.632 ;
     RECT  22.097 35.808 23.245 36.312 ;
     RECT  22.457 46.08 23.353 46.104 ;
     RECT  22.777 43.248 23.533 44.472 ;
     RECT  22.385 33.408 23.713 33.432 ;
     RECT  23.245 34.848 23.749 36.312 ;
     RECT  23.713 32.832 23.857 33.432 ;
     RECT  23.749 34.848 23.929 36.504 ;
     RECT  23.857 32.736 23.965 33.432 ;
     RECT  22.025 47.856 23.965 58.104 ;
     RECT  23.965 32.736 24.001 33.624 ;
     RECT  21.989 23.856 24.008 23.88 ;
     RECT  23.137 25.008 24.008 28.632 ;
     RECT  23.641 30.576 24.008 30.6 ;
     RECT  24.001 32.544 24.008 33.624 ;
     RECT  23.929 34.848 24.008 36.84 ;
     RECT  22.924 38.4 24.008 39.336 ;
     RECT  23.533 42.768 24.008 44.472 ;
     RECT  23.353 46.08 24.008 46.2 ;
     RECT  23.965 47.856 24.008 58.152 ;
     RECT  24.008 2.148 24.112 58.332 ;
     RECT  24.112 2.418 24.304 58.152 ;
     RECT  24.304 38.4 24.401 38.424 ;
     RECT  24.304 41.616 24.515 45 ;
     RECT  24.304 25.008 24.545 28.536 ;
     RECT  24.304 32.208 24.563 32.76 ;
     RECT  24.545 25.008 24.581 28.488 ;
     RECT  24.304 34.8 24.581 34.824 ;
     RECT  24.304 35.856 24.7 36.984 ;
     RECT  24.304 40.032 24.833 40.392 ;
     RECT  24.563 32.736 24.941 32.76 ;
     RECT  24.304 23.952 25.121 23.976 ;
     RECT  24.833 40.368 25.121 40.392 ;
     RECT  24.515 41.616 25.157 41.784 ;
     RECT  25.157 41.76 25.265 41.784 ;
     RECT  24.515 43.296 25.265 45 ;
     RECT  24.304 30.576 25.337 30.744 ;
     RECT  24.304 46.512 25.445 58.152 ;
     RECT  25.445 46.512 25.481 47.592 ;
     RECT  24.7 36.24 25.517 36.984 ;
     RECT  25.445 48.864 25.553 58.152 ;
     RECT  25.553 48.864 25.589 58.104 ;
     RECT  24.581 25.488 25.697 27.288 ;
     RECT  25.697 25.488 25.873 26.568 ;
     RECT  25.265 44.064 25.981 45 ;
     RECT  25.585 32.448 26.017 32.472 ;
     RECT  25.297 33.84 26.017 33.864 ;
     RECT  25.873 25.44 26.089 26.568 ;
     RECT  25.517 36.24 26.197 36.312 ;
     RECT  26.017 32.448 26.233 33.864 ;
     RECT  26.197 35.328 26.233 36.312 ;
     RECT  24.581 28.464 26.413 28.488 ;
     RECT  25.657 31.056 26.449 31.272 ;
     RECT  26.233 32.448 26.449 36.312 ;
     RECT  26.449 31.056 26.485 36.312 ;
     RECT  26.089 25.296 26.513 26.568 ;
     RECT  25.981 44.064 26.521 45.72 ;
     RECT  25.481 46.8 26.521 47.592 ;
     RECT  26.521 44.064 26.557 47.592 ;
     RECT  25.589 49.008 26.557 58.104 ;
     RECT  26.413 29.616 26.593 29.64 ;
     RECT  26.557 44.064 26.593 58.104 ;
     RECT  26.485 30.912 26.665 36.312 ;
     RECT  26.581 59.856 26.705 59.88 ;
     RECT  26.513 24.432 26.708 26.568 ;
     RECT  26.413 27.888 26.708 28.488 ;
     RECT  26.593 29.52 26.708 29.64 ;
     RECT  26.665 30.864 26.708 36.312 ;
     RECT  26.533 40.56 26.708 40.872 ;
     RECT  26.593 44.064 26.708 58.728 ;
     RECT  26.708 2.148 26.777 58.728 ;
     RECT  26.777 2.148 26.812 58.332 ;
     RECT  26.812 2.418 27.004 58.152 ;
     RECT  27.004 44.976 27.029 45 ;
     RECT  27.004 26.304 27.065 26.328 ;
     RECT  27.004 40.848 27.065 40.872 ;
     RECT  27.004 48.72 27.065 50.712 ;
     RECT  27.065 48.96 27.155 49.704 ;
     RECT  27.004 54.672 27.155 58.152 ;
     RECT  27.155 54.672 27.173 55.944 ;
     RECT  27.155 49.68 27.203 49.704 ;
     RECT  27.065 50.688 27.203 50.712 ;
     RECT  27.173 54.768 27.251 55.944 ;
     RECT  27.004 51.936 27.389 53.016 ;
     RECT  27.251 54.816 27.389 55.944 ;
     RECT  27.155 57.408 27.389 58.152 ;
     RECT  27.004 36.528 27.395 36.552 ;
     RECT  27.389 55.152 27.395 55.944 ;
     RECT  27.389 51.936 27.425 51.96 ;
     RECT  27.389 57.6 27.443 58.152 ;
     RECT  27.389 52.992 27.469 53.016 ;
     RECT  27.004 33.84 27.641 33.864 ;
     RECT  27.443 57.888 27.677 58.152 ;
     RECT  27.395 55.152 27.857 55.704 ;
     RECT  27.857 55.152 27.893 55.176 ;
     RECT  27.677 57.888 28.181 57.912 ;
     RECT  27.004 24.912 28.465 24.936 ;
     RECT  28.465 24.912 28.501 25.8 ;
     RECT  28.501 24.912 29.041 26.184 ;
     RECT  29.041 24.816 29.545 26.184 ;
     RECT  29.545 24.816 29.657 26.568 ;
     RECT  29.657 24.816 30.156 24.84 ;
     RECT  29.657 24.84 30.204 24.912 ;
     RECT  29.657 24.912 30.156 24.936 ;
     RECT  29.657 24.936 30.204 25.008 ;
     RECT  29.657 25.008 30.156 25.032 ;
     RECT  29.657 25.032 30.204 25.104 ;
     RECT  29.657 25.104 30.156 25.128 ;
     RECT  29.657 25.128 30.204 25.2 ;
     RECT  29.657 25.2 30.156 25.224 ;
     RECT  29.657 25.224 30.204 25.296 ;
     RECT  29.657 25.296 30.156 25.32 ;
     RECT  29.657 25.32 30.204 25.392 ;
     RECT  29.657 25.392 30.156 25.416 ;
     RECT  29.657 25.416 30.204 25.488 ;
     RECT  29.657 25.488 30.156 25.512 ;
     RECT  29.657 25.512 30.204 25.584 ;
     RECT  29.657 25.584 30.156 25.608 ;
     RECT  29.657 25.608 30.204 25.68 ;
     RECT  29.657 25.68 30.156 25.704 ;
     RECT  29.657 25.704 30.204 25.776 ;
     RECT  29.657 25.776 30.156 25.8 ;
     RECT  29.657 25.8 30.204 25.872 ;
     RECT  29.657 25.872 30.156 25.896 ;
     RECT  29.657 25.896 30.204 25.968 ;
     RECT  29.657 25.968 30.156 25.992 ;
     RECT  29.657 25.992 30.204 26.064 ;
     RECT  29.657 26.064 30.156 26.088 ;
     RECT  29.657 26.088 30.204 26.16 ;
     RECT  29.657 26.16 30.156 26.184 ;
     RECT  29.657 26.184 30.204 26.256 ;
     RECT  29.657 26.256 30.156 26.28 ;
     RECT  29.657 26.28 30.204 26.352 ;
     RECT  29.657 26.352 30.156 26.376 ;
    LAYER M5 ;
     RECT  2.4 2.137 2.52 2.151 ;
     RECT  5.1 2.137 5.22 2.151 ;
     RECT  7.8 2.137 7.92 2.151 ;
     RECT  10.5 2.137 10.62 2.151 ;
     RECT  13.2 2.137 13.32 2.151 ;
     RECT  15.9 2.137 16.02 2.151 ;
     RECT  18.6 2.137 18.72 2.151 ;
     RECT  21.3 2.137 21.42 2.151 ;
     RECT  24 2.137 24.12 2.151 ;
     RECT  26.7 2.137 26.82 2.151 ;
     RECT  7.8 2.151 8.112 3.157 ;
     RECT  5.1 2.151 5.412 3.301 ;
     RECT  6.96 3.157 8.112 3.349 ;
     RECT  4.992 3.301 5.412 3.397 ;
     RECT  6.816 3.349 8.112 3.397 ;
     RECT  6.72 3.397 8.112 3.829 ;
     RECT  4.848 3.397 5.412 3.925 ;
     RECT  4.176 3.925 5.412 4.357 ;
     RECT  4.176 4.357 5.592 4.501 ;
     RECT  6.72 3.829 8.904 4.501 ;
     RECT  4.176 4.501 8.904 5.219 ;
     RECT  2.4 2.151 2.712 6.661 ;
     RECT  4.368 5.219 8.904 6.661 ;
     RECT  10.5 2.151 10.812 6.805 ;
     RECT  2.4 6.661 8.904 7.043 ;
     RECT  4.848 7.043 8.904 7.957 ;
     RECT  4.848 7.957 9.24 8.437 ;
     RECT  2.4 7.043 3.72 8.485 ;
     RECT  4.848 8.437 9.288 8.485 ;
     RECT  2.4 8.485 9.288 8.965 ;
     RECT  10.272 6.805 10.812 8.965 ;
     RECT  0.192 9.877 0.216 10.259 ;
     RECT  2.4 8.965 10.812 13.045 ;
     RECT  2.4 13.045 11.208 13.621 ;
     RECT  0.144 13.285 0.168 14.533 ;
     RECT  0.144 14.533 0.216 15.397 ;
     RECT  0.144 15.397 0.264 15.491 ;
     RECT  13.2 2.151 13.512 16.021 ;
     RECT  2.4 13.621 11.448 16.117 ;
     RECT  2.4 16.117 12.024 16.261 ;
     RECT  2.4 16.261 12.12 16.309 ;
     RECT  13.104 16.021 13.512 16.309 ;
     RECT  2.4 16.309 13.512 16.405 ;
     RECT  0.192 15.491 0.264 16.453 ;
     RECT  18.6 2.151 18.912 16.501 ;
     RECT  0.192 16.453 0.312 16.883 ;
     RECT  2.4 16.405 14.184 17.123 ;
     RECT  2.4 17.123 13.512 17.413 ;
     RECT  15.9 2.151 16.212 17.413 ;
     RECT  0.192 16.883 0.216 17.461 ;
     RECT  17.856 16.501 18.912 17.509 ;
     RECT  17.712 17.509 18.912 17.605 ;
     RECT  0.144 17.461 0.216 17.939 ;
     RECT  15.552 17.413 16.212 18.181 ;
     RECT  0.192 17.939 0.216 18.275 ;
     RECT  15.552 18.181 16.584 19.525 ;
     RECT  2.304 17.413 13.512 19.571 ;
     RECT  17.616 17.605 18.912 19.909 ;
     RECT  2.4 19.571 13.512 20.197 ;
     RECT  0.144 19.669 0.168 20.627 ;
     RECT  17.616 19.909 19.224 20.869 ;
     RECT  2.4 20.197 13.704 21.637 ;
     RECT  2.4 21.637 13.752 22.117 ;
     RECT  14.736 19.525 16.584 22.117 ;
     RECT  2.4 22.117 16.584 22.165 ;
     RECT  17.616 20.869 20.04 22.165 ;
     RECT  2.4 22.165 20.04 22.309 ;
     RECT  0.288 22.453 0.312 22.789 ;
     RECT  2.304 22.309 20.04 22.931 ;
     RECT  0.144 22.789 0.408 22.979 ;
     RECT  21.3 2.151 21.612 23.029 ;
     RECT  2.304 22.931 19.224 23.123 ;
     RECT  2.4 23.123 19.224 23.843 ;
     RECT  2.4 23.843 19.128 23.939 ;
     RECT  21.168 23.029 21.612 23.987 ;
     RECT  17.424 23.939 19.128 24.323 ;
     RECT  26.7 2.151 27.012 24.421 ;
     RECT  0.384 22.979 0.408 25.237 ;
     RECT  17.616 24.323 19.128 25.955 ;
     RECT  21.3 23.987 21.612 26.245 ;
     RECT  2.4 23.939 16.212 26.677 ;
     RECT  0.144 25.237 0.408 27.685 ;
     RECT  0.144 27.685 0.504 27.971 ;
     RECT  0.192 27.971 0.504 28.163 ;
     RECT  2.304 26.677 16.212 28.403 ;
     RECT  17.616 25.955 18.912 28.453 ;
     RECT  0.192 28.163 0.456 28.547 ;
     RECT  20.784 26.245 21.612 28.547 ;
     RECT  22.656 27.205 22.68 28.595 ;
     RECT  2.4 28.403 16.212 29.029 ;
     RECT  2.4 29.029 16.392 29.365 ;
     RECT  17.616 28.453 19.704 30.275 ;
     RECT  2.4 29.365 16.536 30.707 ;
     RECT  26.544 24.421 27.012 30.901 ;
     RECT  0.288 28.547 0.456 31.429 ;
     RECT  0.144 31.429 0.456 31.573 ;
     RECT  26.496 30.901 27.012 31.763 ;
     RECT  2.4 30.707 16.392 31.765 ;
     RECT  24 2.151 24.312 32.197 ;
     RECT  2.304 31.765 16.392 32.435 ;
     RECT  2.4 32.435 16.392 32.437 ;
     RECT  2.4 32.437 16.488 34.453 ;
     RECT  17.616 30.275 18.912 34.453 ;
     RECT  24 32.197 24.552 34.835 ;
     RECT  0.144 31.573 0.552 35.555 ;
     RECT  0.24 35.555 0.552 35.701 ;
     RECT  2.4 34.453 18.912 35.747 ;
     RECT  0.24 35.701 1.272 35.843 ;
     RECT  24 34.835 24.312 35.845 ;
     RECT  2.4 35.747 16.536 36.035 ;
     RECT  24 35.845 24.648 36.323 ;
     RECT  21.3 28.547 21.612 36.325 ;
     RECT  26.544 31.763 27.012 36.517 ;
     RECT  0.24 35.843 0.552 36.563 ;
     RECT  2.4 36.035 16.488 36.901 ;
     RECT  0.24 36.563 0.264 37.525 ;
     RECT  21.024 36.325 21.612 37.619 ;
     RECT  0.24 37.525 0.504 37.909 ;
     RECT  21.3 37.619 21.612 38.005 ;
     RECT  22.848 36.277 22.872 38.005 ;
     RECT  2.304 36.901 16.488 38.725 ;
     RECT  17.616 35.747 18.912 38.725 ;
     RECT  0.144 37.909 0.504 38.963 ;
     RECT  2.304 38.725 18.912 39.781 ;
     RECT  0.144 38.963 0.408 39.875 ;
     RECT  0.192 39.875 0.408 39.923 ;
     RECT  0.192 39.923 0.312 39.971 ;
     RECT  21.3 38.005 22.872 40.019 ;
     RECT  2.304 39.781 19.128 40.067 ;
     RECT  0.24 39.971 0.312 40.115 ;
     RECT  2.304 40.067 16.488 40.595 ;
     RECT  22.848 40.019 22.872 40.595 ;
     RECT  0.24 40.115 0.264 40.933 ;
     RECT  0.192 40.933 0.264 41.413 ;
     RECT  24 36.323 24.312 42.085 ;
     RECT  0.192 41.413 0.312 42.229 ;
     RECT  0.192 42.229 0.552 42.373 ;
     RECT  0.144 42.373 0.552 42.995 ;
     RECT  24 42.085 24.504 43.285 ;
     RECT  0.144 42.995 0.36 44.005 ;
     RECT  24 43.285 25.032 44.051 ;
     RECT  0.144 44.005 0.408 44.387 ;
     RECT  24 44.051 24.792 44.437 ;
     RECT  0.192 44.387 0.408 44.675 ;
     RECT  2.4 40.595 16.488 44.917 ;
     RECT  17.616 40.067 19.128 44.917 ;
     RECT  0.192 44.675 0.36 45.107 ;
     RECT  0.192 45.107 0.312 45.203 ;
     RECT  2.4 44.917 19.128 45.541 ;
     RECT  21.3 40.019 21.612 45.541 ;
     RECT  0.192 45.203 0.264 45.781 ;
     RECT  2.304 45.541 19.128 46.067 ;
     RECT  23.52 44.437 24.792 46.211 ;
     RECT  0.144 45.781 0.264 46.309 ;
     RECT  0.144 46.309 0.312 46.835 ;
     RECT  0.144 46.835 0.216 46.979 ;
     RECT  2.304 46.067 16.488 47.029 ;
     RECT  17.616 46.067 19.128 47.029 ;
     RECT  21.168 45.541 21.612 47.603 ;
     RECT  24 46.211 24.792 47.845 ;
     RECT  2.304 47.029 19.128 47.939 ;
     RECT  0.144 46.979 0.168 48.037 ;
     RECT  2.4 47.939 19.128 48.131 ;
     RECT  23.376 47.845 24.792 48.515 ;
     RECT  17.616 48.131 19.128 48.901 ;
     RECT  23.856 48.515 24.792 49.189 ;
     RECT  26.544 36.517 27.384 49.189 ;
     RECT  23.856 49.189 27.384 49.525 ;
     RECT  2.4 48.131 16.488 49.715 ;
     RECT  0.144 48.037 0.312 50.341 ;
     RECT  22.896 49.525 27.384 50.677 ;
     RECT  4.416 49.715 16.488 50.771 ;
     RECT  9.84 50.771 16.488 50.867 ;
     RECT  10.032 50.867 16.488 50.963 ;
     RECT  10.5 50.963 16.488 50.965 ;
     RECT  21.3 47.603 21.612 51.109 ;
     RECT  10.5 50.965 16.536 51.155 ;
     RECT  20.88 51.109 21.612 51.157 ;
     RECT  22.752 50.677 27.384 51.157 ;
     RECT  0.144 50.341 0.552 51.203 ;
     RECT  0.144 51.203 0.312 51.251 ;
     RECT  2.4 49.715 3.384 51.445 ;
     RECT  2.304 51.445 3.384 51.541 ;
     RECT  4.416 50.771 8.568 51.541 ;
     RECT  0.24 51.251 0.312 51.971 ;
     RECT  0.24 51.971 0.264 52.067 ;
     RECT  2.304 51.541 8.568 52.307 ;
     RECT  20.88 51.157 27.384 52.547 ;
     RECT  21.168 52.547 27.384 52.981 ;
     RECT  17.616 48.901 19.512 53.029 ;
     RECT  12 51.155 16.536 53.123 ;
     RECT  0.192 52.261 0.216 53.411 ;
     RECT  12 53.123 12.12 53.555 ;
     RECT  13.2 53.123 16.536 53.555 ;
     RECT  13.2 53.555 16.488 53.651 ;
     RECT  12 53.555 12.024 53.843 ;
     RECT  17.616 53.029 19.752 53.941 ;
     RECT  21.168 52.981 27.432 53.941 ;
     RECT  2.304 52.307 8.232 54.179 ;
     RECT  2.4 54.179 8.232 54.563 ;
     RECT  3.696 54.563 6.264 54.755 ;
     RECT  13.2 53.651 16.392 54.755 ;
     RECT  3.696 54.755 5.784 54.947 ;
     RECT  17.616 53.941 27.432 54.947 ;
     RECT  17.616 54.947 22.008 54.995 ;
     RECT  3.696 54.947 3.72 55.187 ;
     RECT  17.712 54.995 22.008 55.667 ;
     RECT  7.44 54.563 8.232 55.715 ;
     RECT  13.2 54.755 14.424 55.861 ;
     RECT  15.552 54.755 16.392 55.861 ;
     RECT  5.1 54.947 5.784 55.907 ;
     RECT  18.6 55.667 22.008 55.907 ;
     RECT  7.8 55.715 8.232 56.003 ;
     RECT  20.16 55.907 21.912 56.003 ;
     RECT  0.144 56.053 0.168 56.339 ;
     RECT  13.2 55.861 16.392 56.483 ;
     RECT  23.328 54.947 27.432 56.483 ;
     RECT  13.2 56.483 13.8 56.531 ;
     RECT  14.88 56.483 16.392 56.629 ;
     RECT  14.88 56.629 17.16 56.819 ;
     RECT  24 56.483 27.432 57.059 ;
     RECT  13.2 56.531 13.752 57.541 ;
     RECT  14.88 56.819 16.488 57.541 ;
     RECT  24 57.059 24.84 57.635 ;
     RECT  25.824 57.059 27.432 57.635 ;
     RECT  20.16 56.003 21.768 57.683 ;
     RECT  21.072 57.683 21.768 57.731 ;
     RECT  13.2 57.541 16.488 58.165 ;
     RECT  2.4 54.563 2.712 58.329 ;
     RECT  5.1 55.907 5.412 58.329 ;
     RECT  7.8 56.003 8.112 58.329 ;
     RECT  10.5 51.155 10.812 58.329 ;
     RECT  18.6 55.907 18.912 58.329 ;
     RECT  21.072 57.731 21.612 58.329 ;
     RECT  24 57.635 24.312 58.329 ;
     RECT  26.592 57.635 27.012 58.329 ;
     RECT  2.4 58.329 2.52 58.343 ;
     RECT  5.1 58.329 5.22 58.343 ;
     RECT  7.8 58.329 7.92 58.343 ;
     RECT  10.5 58.329 10.62 58.343 ;
     RECT  13.2 58.165 17.16 58.343 ;
     RECT  18.6 58.329 18.72 58.343 ;
     RECT  21.072 58.329 21.42 58.343 ;
     RECT  24 58.329 24.12 58.343 ;
     RECT  26.592 58.329 26.82 58.343 ;
     RECT  26.592 58.343 26.616 59.891 ;
     RECT  21.072 58.343 21.096 60.419 ;
     RECT  14.16 58.343 17.16 60.396 ;
     RECT  14.184 60.396 14.256 60.432 ;
     RECT  14.28 60.396 14.352 60.432 ;
     RECT  14.376 60.396 14.448 60.432 ;
     RECT  14.472 60.396 14.544 60.432 ;
     RECT  14.568 60.396 14.64 60.432 ;
     RECT  14.664 60.396 14.736 60.432 ;
     RECT  14.76 60.396 14.832 60.432 ;
     RECT  14.856 60.396 14.928 60.432 ;
     RECT  14.952 60.396 15.024 60.432 ;
     RECT  15.048 60.396 15.12 60.432 ;
     RECT  15.144 60.396 15.216 60.432 ;
     RECT  15.24 60.396 15.312 60.432 ;
     RECT  15.336 60.396 15.408 60.432 ;
     RECT  15.432 60.396 15.504 60.432 ;
     RECT  15.528 60.396 15.6 60.432 ;
     RECT  15.624 60.396 15.696 60.432 ;
     RECT  15.72 60.396 15.792 60.432 ;
     RECT  15.816 60.396 15.888 60.432 ;
     RECT  15.912 60.396 15.984 60.432 ;
     RECT  16.008 60.396 16.08 60.432 ;
     RECT  16.104 60.396 16.176 60.432 ;
     RECT  16.2 60.396 16.272 60.432 ;
     RECT  16.296 60.396 16.368 60.432 ;
     RECT  16.392 60.396 16.464 60.432 ;
     RECT  16.488 60.396 16.56 60.432 ;
     RECT  16.584 60.396 16.656 60.432 ;
     RECT  16.68 60.396 16.752 60.432 ;
     RECT  16.776 60.396 16.848 60.432 ;
     RECT  16.872 60.396 16.944 60.432 ;
     RECT  16.968 60.396 17.04 60.432 ;
     RECT  17.064 60.396 17.136 60.432 ;
     RECT  5.412 3.349 6.816 3.397 ;
     RECT  5.412 3.397 6.72 4.357 ;
     RECT  2.712 3.925 4.176 5.219 ;
     RECT  5.592 4.357 6.72 4.501 ;
     RECT  2.712 5.219 4.368 6.661 ;
     RECT  8.904 6.805 10.272 7.957 ;
     RECT  3.72 7.043 4.848 8.485 ;
     RECT  9.24 7.957 10.272 8.437 ;
     RECT  9.288 8.437 10.272 8.965 ;
     RECT  12.024 16.117 13.104 16.261 ;
     RECT  12.12 16.261 13.104 16.309 ;
     RECT  16.212 17.509 17.712 17.605 ;
     RECT  16.212 17.605 17.616 18.181 ;
     RECT  16.584 18.181 17.616 22.165 ;
     RECT  13.512 19.525 14.736 20.197 ;
     RECT  13.704 20.197 14.736 21.637 ;
     RECT  20.04 20.869 21.3 22.931 ;
     RECT  13.752 21.637 14.736 22.117 ;
     RECT  21.168 22.931 21.3 23.029 ;
     RECT  16.212 23.939 17.424 24.323 ;
     RECT  16.212 24.323 17.616 29.029 ;
     RECT  21.612 27.205 22.656 28.595 ;
     RECT  22.68 27.205 24 28.595 ;
     RECT  19.704 28.453 20.784 28.547 ;
     RECT  16.392 29.029 17.616 29.365 ;
     RECT  16.536 29.365 17.616 30.707 ;
     RECT  16.392 30.707 17.616 32.437 ;
     RECT  16.488 32.437 17.616 34.453 ;
     RECT  24.312 34.835 24.552 35.845 ;
     RECT  1.272 35.701 2.4 35.843 ;
     RECT  16.536 35.747 17.616 36.035 ;
     RECT  2.304 35.843 2.4 36.901 ;
     RECT  16.488 36.035 17.616 38.725 ;
     RECT  21.612 36.277 22.848 38.005 ;
     RECT  22.872 36.277 24 40.595 ;
     RECT  0.264 36.563 0.504 37.525 ;
     RECT  0.192 39.971 0.24 40.933 ;
     RECT  21.612 40.019 22.848 40.595 ;
     RECT  16.488 40.067 17.616 44.917 ;
     RECT  0.264 40.115 0.312 41.413 ;
     RECT  0.36 42.995 0.408 44.005 ;
     RECT  25.032 43.285 26.544 44.051 ;
     RECT  0.144 44.387 0.192 45.781 ;
     RECT  0.264 45.203 0.312 46.309 ;
     RECT  16.488 46.067 17.616 47.029 ;
     RECT  0.216 46.835 0.312 46.979 ;
     RECT  0.168 46.979 0.312 48.037 ;
     RECT  16.488 48.131 17.616 50.965 ;
     RECT  23.376 48.515 23.856 49.525 ;
     RECT  21.612 49.525 22.896 50.677 ;
     RECT  3.384 49.715 4.416 51.541 ;
     RECT  21.612 50.677 22.752 51.157 ;
     RECT  8.568 50.771 9.84 50.867 ;
     RECT  8.568 50.867 10.032 50.963 ;
     RECT  16.536 50.965 17.616 53.555 ;
     RECT  19.512 51.109 20.88 52.547 ;
     RECT  10.812 51.155 12 53.843 ;
     RECT  0.192 51.251 0.24 52.067 ;
     RECT  0.192 52.067 0.216 52.261 ;
     RECT  19.512 52.547 21.168 53.029 ;
     RECT  19.752 53.029 21.168 53.941 ;
     RECT  12.12 53.123 13.2 53.555 ;
     RECT  12.024 53.555 13.2 53.843 ;
     RECT  16.488 53.555 17.616 53.651 ;
     RECT  16.392 53.651 17.616 54.995 ;
     RECT  2.712 54.563 3.696 55.187 ;
     RECT  6.264 54.563 7.44 54.755 ;
     RECT  14.424 54.755 15.552 55.861 ;
     RECT  3.72 54.947 5.1 55.187 ;
     RECT  22.008 54.947 23.328 55.907 ;
     RECT  16.392 54.995 17.712 55.667 ;
     RECT  16.392 55.667 18.6 56.629 ;
     RECT  18.912 55.907 20.16 57.683 ;
     RECT  21.912 55.907 23.328 56.003 ;
     RECT  13.8 56.483 14.88 56.531 ;
     RECT  13.752 56.531 14.88 57.541 ;
     RECT  17.16 56.629 18.6 56.819 ;
     RECT  16.488 56.819 18.6 58.165 ;
     RECT  24.84 57.059 25.824 57.635 ;
     RECT  17.16 58.165 18.6 58.343 ;
  END
END ot_s81_cfg7_seq_bfp
END LIBRARY
